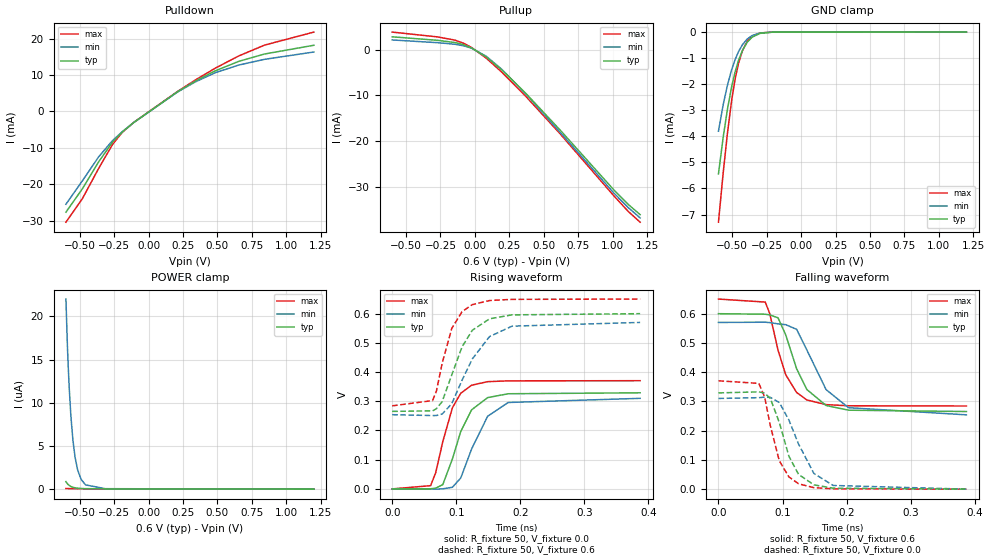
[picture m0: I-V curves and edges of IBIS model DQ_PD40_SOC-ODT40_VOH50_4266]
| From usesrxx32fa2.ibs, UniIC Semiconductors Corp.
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| DQ_PD40_SOC-ODT40_VOH50_4266
| (40 Ohm Pulldown, 40 Ohm System ODT Setting, VOH=VDDQ*0.50, 3200-4266Mbps)
[Model]   DQ_PD40_SOC-ODT40_VOH50_4266
Model_type   I/O
Vinl = 90.000mV
Vinh = 210.000mV
Vmeas = 150.000mV
Vref = 0.0mV
Cref = 0.0pF
Rref = 40.000Ohm
|   typ   min   max
|C_comp   0.834pF   0.784pF   0.884pF
C_comp_pullup   0.4170pF   0.3920pF   0.4420pF
C_comp_pulldown   0.4170pF   0.3920pF   0.4420pF
| Note: C_comp changes when the ODT circuit is enabled.
[Model Spec]
| Input threshold voltage corners
Vinl   0.0900V   0.0825V   0.1025V
Vinh   0.2100V   0.2025V   0.2225V
| Measurement voltage corners
Vmeas   0.1500V   0.1425V   0.1625V
| Timing spec test load voltage corners
Vref   0.0000V   0.0000V   0.0000V
| Dynamic Overshoot Parameters from LPDDR4_0P6 Specification
D_overshoot_ampl_h   0.30   NA   NA
D_overshoot_ampl_l   0.30   NA   NA
D_overshoot_area_h   0.1n   NA   NA
D_overshoot_area_l   0.1n   NA   NA
[Voltage Range]   0.6000V   0.5700V   0.6500V
[Pullup Reference]   0.6000V   0.5700V   0.6500V
| Junction Temperature (Ambient temp is 35C typ 95C min -40C max)
[Temperature Range]   50.0   110.0   -40.0
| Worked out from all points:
|   slope of the pulldown table from 0 to 0.09 V, typ, clamps not added: 37.5 ohm
|   slope of the pullup table from 0 to 0.09 V, typ, clamps not added: 50.7 ohm
|   GND clamp passes 1 mA (typ) near -0.45 V on its own axis
|   rising waveform, R_fixture 50, V_fixture 0.0: 20-80 % time 32.4ps typ, 36.9ps min, 27.6ps max; typ from 0 V to 0.329 V
|   falling waveform, R_fixture 50, V_fixture 0.6: 20-80 % time 36.5ps typ, 44.7ps min, 30.1ps max; typ from 0.6 V to 0.265 V
|   rising waveform, R_fixture 50, V_fixture 0.6: 20-80 % time 36.8ps typ, 46.2ps min, 27.6ps max; typ from 0.265 V to 0.6 V
|   falling waveform, R_fixture 50, V_fixture 0.0: 20-80 % time 29.8ps typ, 38.3ps min, 25.6ps max; typ from 0.329 V to 0 V
[Pulldown]
|   Voltage   I(typ)   I(min)   I(max)
-600mV    -27.61mA   -25.44mA   -30.36mA
-481.2mV  -21.24mA   -19.05mA   -23.95mA
-362.4mV  -13.81mA   -12.44mA   -15.62mA
-261.6mV  -8.403mA   -7.984mA   -9.043mA
-191.4mV  -5.65mA    -5.564mA   -5.738mA
-106.8mV  -3.009mA   -3.011mA   -2.967mA
210mV     5.393mA    5.317mA    5.481mA
343.2mV   8.401mA    8.176mA    8.713mA
483.6mV   11.12mA    10.61mA    11.85mA
652.8mV   13.71mA    12.71mA    15.19mA
841.8mV   15.75mA    14.29mA    18.19mA
1.2V      18.15mA    16.3mA     21.76mA
[GND Clamp]
|   Voltage   I(typ)   I(min)   I(max)
-600mV    -5.439mA   -3.802mA   -7.294mA
-565.8mV  -4.041mA   -2.789mA   -5.405mA
-535.2mV  -2.973mA   -2.046mA   -3.901mA
-504.6mV  -2.102mA   -1.448mA   -2.634mA
-479.4mV  -1.532mA   -1.058mA   -1.808mA
-454.2mV  -1.084mA   -747.4uA   -1.192mA
-425.4mV  -700.2uA   -481.1uA   -707uA
-391.2mV  -388.2uA   -265.6uA   -353.3uA
-355.2mV  -191.7uA   -131uA     -153uA
-297.6mV  -49.42uA   -36uA      -31.63uA
-211.2mV  -4.178uA   -3.866uA   -1.653uA
1.2V      0A         0A         0A
[Pullup]
|   Voltage   I(typ)   I(min)   I(max)
-600mV    2.791mA    2.105mA    3.822mA
-270.6mV  2.022mA    1.507mA    2.767mA
-144.6mV  1.539mA    1.164mA    2.066mA
-81.6mV   1.06mA     833.1uA    1.379mA
-24mV     363.8uA    298.2uA    458.9uA
82.2mV    -1.597mA   -1.443mA   -1.864mA
195.6mV   -4.447mA   -4.306mA   -4.93mA
368.4mV   -9.521mA   -9.648mA   -10.17mA
618.6mV   -17.57mA   -18.06mA   -18.39mA
1.007V    -30.6mA    -31.29mA   -31.89mA
1.114V    -33.85mA   -34.55mA   -35.39mA
1.2V      -36.08mA   -36.8mA    -37.73mA
[POWER Clamp]
|   Voltage   I(typ)   I(min)   I(max)
-600mV    870.6nA    22uA       72.65nA
-589.2mV  630.3nA    16.59uA    68.66nA
-583.8mV  538.6nA    14.39uA    66.96nA
-576.6mV  439.3nA    11.87uA    64.76nA
-564mV    312.7nA    8.464uA    61.06nA
-549.6mV  220nA      5.727uA    57.05nA
-533.4mV  154.6nA    3.672uA    52.81nA
-515.4mV  112.1nA    2.248uA    48.4nA
-490.2mV  80.1nA     1.143uA    42.74nA
-457.8mV  60.43nA    496.6nA    36.26nA
-313.8mV  32.76nA    54.76nA    16.39nA
1.2V      0A         0A         0A
[Ramp]
|   typ   min   max
| 20% - 80%
dV/dt_r   197.37m/32.41p   186.01m/36.87p   222.28m/27.64p
dV/dt_f   200.71m/36.55p   189.46m/44.72p   219.39m/30.09p
| 25% - 75%
|dV/dt_r   164.47m/25.64p   155.01m/29.22p   185.23m/21.78p
|dV/dt_f   167.26m/28.85p   157.89m/35.36p   182.82m/23.68p
R_load = 50
[Rising Waveform]
R_fixture = 50
V_fixture = 0.0
|   Time   V(typ)   V(min)   V(max)
0s        149.9uV    129.1uV    73.21uV
60ps      430.6uV    -393.9uV   11.15mV
68ps      2.741mV    -860.7uV   56.09mV
79ps      14.77mV    331.8uV    162mV
94ps      102.7mV    5.584mV    278mV
107ps     196.6mV    37.37mV    327.5mV
124ps     270.9mV    137mV      355.1mV
149ps     312.6mV    248.8mV    367.2mV
181ps     325.8mV    295.9mV    370mV
387ps     329.1mV    310.1mV    370.5mV
[Falling Waveform]
R_fixture   = 50
V_fixture   = 0.6
V_fixture_min = 0.57
V_fixture_max = 0.65
|   Time   V(typ)   V(min)   V(max)
0s        600mV      570mV      650mV
73ps      598.2mV    570.9mV    639.7mV
80ps      595.9mV    569.5mV    600.6mV
93ps      585.8mV    565.2mV    475.3mV
105ps     527.5mV    562.5mV    391.2mV
122ps     411.7mV    546.5mV    330.6mV
138ps     340.6mV    475.7mV    305.1mV
168ps     286.1mV    340.4mV    289.1mV
203ps     270.1mV    278.6mV    285.2mV
387ps     265.5mV    254.2mV    284.4mV
[Rising Waveform]
R_fixture   = 50
V_fixture   = 0.6
V_fixture_min = 0.57
V_fixture_max = 0.65
|   Time   V(typ)   V(min)   V(max)
0s        265.4mV    254.1mV    284.4mV
63ps      267.3mV    251.2mV    302.5mV
69ps      274.6mV    251.3mV    334.7mV
78ps      298.9mV    256.3mV    430.3mV
93ps      390.4mV    291.7mV    549.5mV
109ps     486.2mV    372mV      606.9mV
125ps     543.2mV    444.8mV    631mV
152ps     582.4mV    521.7mV    645mV
187ps     595.9mV    557.2mV    649mV
387ps     600mV      570mV      650mV
[Falling Waveform]
R_fixture = 50
V_fixture = 0.0
|   Time   V(typ)   V(min)   V(max)
0s        329.2mV    310.2mV    370.6mV
63ps      332.7mV    312.9mV    361.7mV
72ps      328.7mV    314.8mV    315.8mV
81ps      310.1mV    313.8mV    216.5mV
95ps      227.9mV    296.3mV    96.9mV
110ps     112.4mV    236.2mV    41.9mV
125ps     50.7mV     154.4mV    18.54mV
149ps     14.81mV    53.63mV    5.217mV
179ps     3.535mV    12.74mV    1.174mV
387ps     204.4uV    205.7uV    91.86uV
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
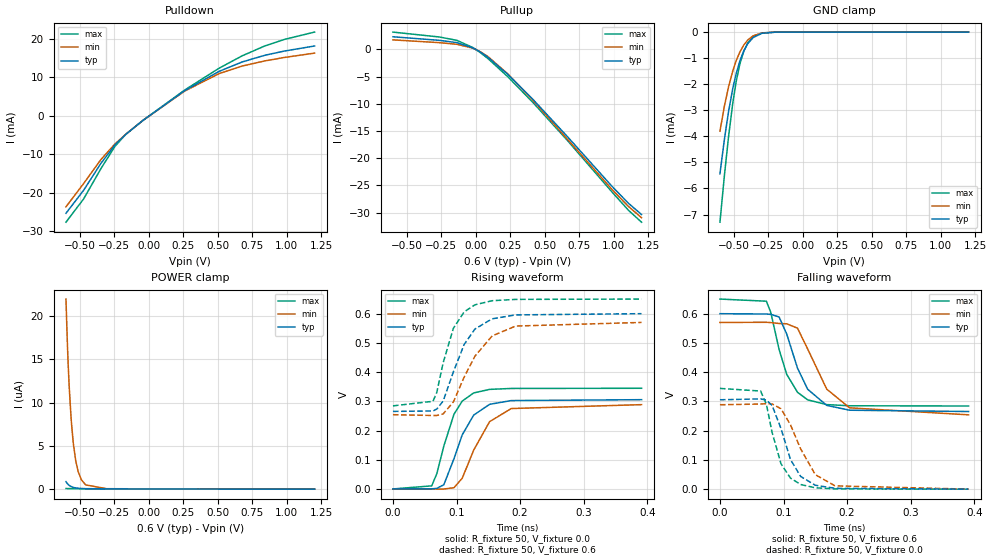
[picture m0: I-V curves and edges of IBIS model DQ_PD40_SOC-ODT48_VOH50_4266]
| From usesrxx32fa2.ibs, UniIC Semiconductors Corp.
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| DQ_PD40_SOC-ODT48_VOH50_4266
| (40 Ohm Pulldown, 48 Ohm System ODT Setting, VOH=VDDQ*0.50, 3200-4266Mbps)
[Model]   DQ_PD40_SOC-ODT48_VOH50_4266
Model_type   I/O
Vinl = 90.000mV
Vinh = 210.000mV
Vmeas = 150.000mV
Vref = 0.0mV
Cref = 0.0pF
Rref = 48.000Ohm
|   typ   min   max
|C_comp   0.834pF   0.784pF   0.884pF
C_comp_pullup   0.4170pF   0.3920pF   0.4420pF
C_comp_pulldown   0.4170pF   0.3920pF   0.4420pF
| Note: C_comp changes when the ODT circuit is enabled.
[Model Spec]
| Input threshold voltage corners
Vinl   0.0900V   0.0825V   0.1025V
Vinh   0.2100V   0.2025V   0.2225V
| Measurement voltage corners
Vmeas   0.1500V   0.1425V   0.1625V
| Timing spec test load voltage corners
Vref   0.0000V   0.0000V   0.0000V
| Dynamic Overshoot Parameters from LPDDR4_0P6 Specification
D_overshoot_ampl_h   0.30   NA   NA
D_overshoot_ampl_l   0.30   NA   NA
D_overshoot_area_h   0.1n   NA   NA
D_overshoot_area_l   0.1n   NA   NA
[Voltage Range]   0.6000V   0.5700V   0.6500V
[Pullup Reference]   0.6000V   0.5700V   0.6500V
| Junction Temperature (Ambient temp is 35C typ 95C min -40C max)
[Temperature Range]   50.0   110.0   -40.0
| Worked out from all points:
|   slope of the pulldown table from 0 to 0.09 V, typ, clamps not added: 37.5 ohm
|   slope of the pullup table from 0 to 0.09 V, typ, clamps not added: 60.5 ohm
|   GND clamp passes 1 mA (typ) near -0.45 V on its own axis
|   rising waveform, R_fixture 50, V_fixture 0.0: 20-80 % time 34.1ps typ, 38.8ps min, 29.5ps max; typ from 0 V to 0.306 V
|   falling waveform, R_fixture 50, V_fixture 0.6: 20-80 % time 36.4ps typ, 44.5ps min, 30ps max; typ from 0.6 V to 0.265 V
|   rising waveform, R_fixture 50, V_fixture 0.6: 20-80 % time 38.2ps typ, 48ps min, 29.5ps max; typ from 0.265 V to 0.6 V
|   falling waveform, R_fixture 50, V_fixture 0.0: 20-80 % time 29.7ps typ, 38.2ps min, 25.5ps max; typ from 0.306 V to 0 V
[Pulldown]
|   Voltage   I(typ)   I(min)   I(max)
-600mV    -25.3mA    -23.62mA   -27.61mA
-472.2mV  -19.33mA   -17.58mA   -21.57mA
-348mV    -12.39mA   -11.39mA   -13.77mA
-245.4mV  -7.543mA   -7.299mA   -7.923mA
-166.2mV  -4.776mA   -4.752mA   -4.766mA
-40.2mV   -1.116mA   -1.117mA   -1.099mA
260.4mV   6.575mA    6.453mA    6.729mA
508.8mV   11.56mA    10.98mA    12.38mA
676.2mV   14.01mA    12.94mA    15.6mA
838.2mV   15.72mA    14.26mA    18.14mA
982.2mV   16.84mA    15.17mA    19.87mA
1.2V      18.15mA    16.3mA     21.76mA
[GND Clamp]
|   Voltage   I(typ)   I(min)   I(max)
-600mV    -5.439mA   -3.802mA   -7.294mA
-567.6mV  -4.11mA    -2.837mA   -5.5mA
-537mV    -3.03mA    -2.085mA   -3.984mA
-506.4mV  -2.147mA   -1.48mA    -2.701mA
-483mV    -1.606mA   -1.108mA   -1.914mA
-456mV    -1.113mA   -767.4uA   -1.229mA
-427.2mV  -720.9uA   -495.1uA   -731.4uA
-398.4mV  -442.5uA   -303.2uA   -412.2uA
-358.8mV  -206.5uA   -141.1uA   -167.7uA
-295.8mV  -46.87uA   -34.39uA   -30.01uA
-196.8mV  -2.661uA   -2.56uA    -930.3nA
1.2V      0A         0A         0A
[Pullup]
|   Voltage   I(typ)   I(min)   I(max)
-600mV    2.327mA    1.755mA    3.187mA
-263.4mV  1.669mA    1.244mA    2.284mA
-137.4mV  1.249mA    947.7uA    1.674mA
-22.2mV   282.6uA    232uA      356.7uA
28.2mV    -409.2uA   -351.4uA   -496.8uA
89.4mV    -1.476mA   -1.34mA    -1.715mA
231.6mV   -4.578mA   -4.498mA   -5.021mA
417mV     -9.279mA   -9.462mA   -9.848mA
663.6mV   -16.04mA   -16.5mA    -16.75mA
987.6mV   -25.21mA   -25.79mA   -26.25mA
1.106V    -28.3mA    -28.89mA   -29.59mA
1.2V      -30.35mA   -30.94mA   -31.76mA
[POWER Clamp]
|   Voltage   I(typ)   I(min)   I(max)
-600mV    870.6nA    21.99uA    72.65nA
-589.2mV  630.3nA    16.59uA    68.66nA
-583.8mV  538.7nA    14.38uA    66.96nA
-576.6mV  439.5nA    11.87uA    64.76nA
-562.2mV  298.7nA    8.067uA    60.55nA
-547.8mV  210.3nA    5.447uA    56.57nA
-529.8mV  144.2nA    3.329uA    51.9nA
-511.8mV  105.9nA    2.039uA    47.56nA
-488.4mV  78.54nA    1.09uA     41.9nA
-457.8mV  60.53nA    496.8nA    36.26nA
-304.8mV  31.8nA     52.11nA    15.54nA
1.2V      0A         0A         0A
[Ramp]
|   typ   min   max
| 20% - 80%
dV/dt_r   183.29m/34.10p   173.12m/38.82p   206.72m/29.52p
dV/dt_f   200.72m/36.44p   189.48m/44.46p   219.38m/30.02p
| 25% - 75%
|dV/dt_r   152.74m/26.99p   144.26m/30.75p   172.26m/23.28p
|dV/dt_f   167.26m/28.75p   157.90m/35.18p   182.82m/23.65p
R_load = 50
[Rising Waveform]
R_fixture = 50
V_fixture = 0.0
|   Time   V(typ)   V(min)   V(max)
0s        120.8uV    101.4uV    60.2uV
61ps      343.6uV    -302.5uV   10.51mV
69ps      1.882mV    -766.3uV   52.42mV
80ps      14.36mV    -212.7uV   146.6mV
96ps      103.6mV    4.263mV    255.8mV
109ps     185.3mV    36.8mV     300.8mV
127ps     252.8mV    132.9mV    328.7mV
152ps     289.7mV    230.3mV    340.8mV
186ps     302.5mV    275.2mV    344mV
391ps     305.6mV    288.6mV    344.6mV
[Falling Waveform]
R_fixture   = 50
V_fixture   = 0.6
V_fixture_min = 0.57
V_fixture_max = 0.65
|   Time   V(typ)   V(min)   V(max)
0s        600mV      570mV      650mV
73ps      598.9mV    570.6mV    642.7mV
80ps      597.6mV    569.6mV    604mV
93ps      588.8mV    566.5mV    477.9mV
105ps     530.6mV    565.4mV    392.7mV
122ps     413.8mV    550.4mV    331.3mV
138ps     341.6mV    479.2mV    305.4mV
168ps     286.4mV    341.9mV    289.2mV
204ps     270mV      278.1mV    285.2mV
391ps     265.5mV    254.2mV    284.4mV
[Rising Waveform]
R_fixture   = 50
V_fixture   = 0.6
V_fixture_min = 0.57
V_fixture_max = 0.65
|   Time   V(typ)   V(min)   V(max)
0s        265.4mV    254.1mV    284.4mV
63ps      266.8mV    251.5mV    300.1mV
69ps      273.5mV    251.4mV    330.8mV
79ps      301mV      256.9mV    432.2mV
95ps      400.4mV    297.7mV    549.7mV
112ps     494.6mV    382.9mV    606.2mV
129ps     547.5mV    454.7mV    630.4mV
156ps     582.4mV    523.8mV    644.3mV
193ps     595.8mV    557.6mV    648.9mV
391ps     600mV      570mV      650mV
[Falling Waveform]
R_fixture = 50
V_fixture = 0.0
|   Time   V(typ)   V(min)   V(max)
0s        305.7mV    288.7mV    344.6mV
64ps      308.6mV    291.1mV    335.5mV
73ps      304.7mV    292.6mV    290.8mV
82ps      286.5mV    291.4mV    194.3mV
96ps      207.5mV    275.1mV    87.18mV
111ps     101.1mV    219.8mV    37.91mV
127ps     43.48mV    137.5mV    15.92mV
150ps     13.43mV    49.64mV    4.75mV
181ps     3.075mV    11.38mV    1.024mV
391ps     179.7uV    183.6uV    80.44uV
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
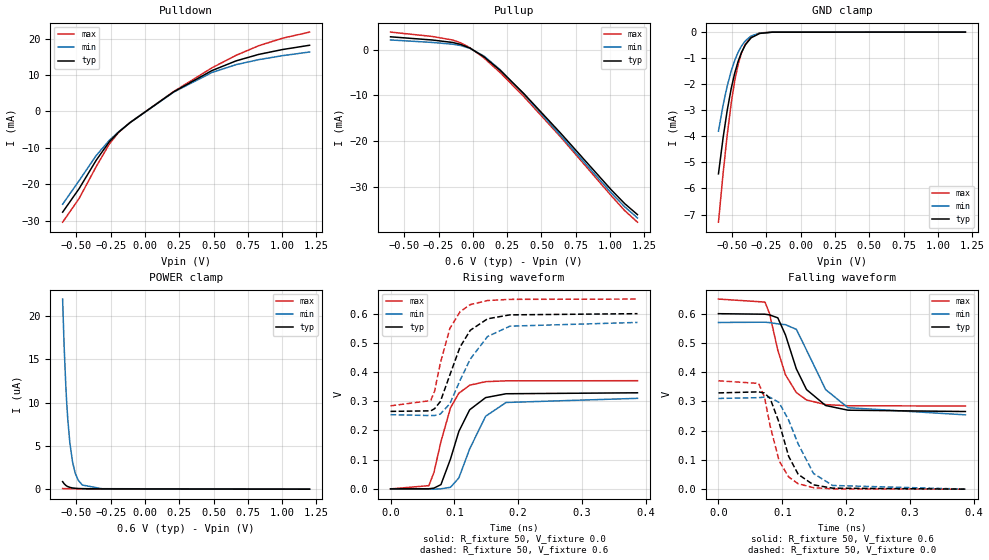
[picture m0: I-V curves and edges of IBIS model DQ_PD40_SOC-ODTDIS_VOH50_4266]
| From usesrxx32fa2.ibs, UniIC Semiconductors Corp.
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| DQ_PD40_SOC-ODTDIS_VOH50_4266
| (40 Ohm Pulldown, SOC ODT disabled setting, VOH=VDDQ*0.50 cal. point, 3200-4266Mbps)
[Model]   DQ_PD40_SOC-ODTDIS_VOH50_4266
Model_type   I/O
Vinl = 90.000mV
Vinh = 210.000mV
Vmeas = 150.000mV
Vref = 0.0mV
Cref = 0.0pF
|   typ   min   max
|C_comp   0.834pF   0.784pF   0.884pF
C_comp_pullup   0.4170pF   0.3920pF   0.4420pF
C_comp_pulldown   0.4170pF   0.3920pF   0.4420pF
| Note: C_comp changes when the ODT circuit is enabled.
[Model Spec]
| Input threshold voltage corners
Vinl   0.0900V   0.0825V   0.1025V
Vinh   0.2100V   0.2025V   0.2225V
| Measurement voltage corners
Vmeas   0.1500V   0.1425V   0.1625V
| Timing spec test load voltage corners
Vref   0.0000V   0.0000V   0.0000V
| Dynamic Overshoot Parameters from LPDDR4_0P6 Specification
D_overshoot_ampl_h   0.30   NA   NA
D_overshoot_ampl_l   0.30   NA   NA
D_overshoot_area_h   0.1n   NA   NA
D_overshoot_area_l   0.1n   NA   NA
[Voltage Range]   0.6000V   0.5700V   0.6500V
[Pullup Reference]   0.6000V   0.5700V   0.6500V
| Junction Temperature (Ambient temp is 35C typ 95C min -40C max)
[Temperature Range]   50.0   110.0   -40.0
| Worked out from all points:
|   slope of the pulldown table from 0 to 0.09 V, typ, clamps not added: 37.5 ohm
|   slope of the pullup table from 0 to 0.09 V, typ, clamps not added: 50.7 ohm
|   GND clamp passes 1 mA (typ) near -0.45 V on its own axis
|   rising waveform, R_fixture 50, V_fixture 0.0: 20-80 % time 32.4ps typ, 36.9ps min, 27.6ps max; typ from 0 V to 0.329 V
|   falling waveform, R_fixture 50, V_fixture 0.6: 20-80 % time 36.5ps typ, 44.7ps min, 30.1ps max; typ from 0.6 V to 0.265 V
|   rising waveform, R_fixture 50, V_fixture 0.6: 20-80 % time 36.8ps typ, 46.2ps min, 27.6ps max; typ from 0.265 V to 0.6 V
|   falling waveform, R_fixture 50, V_fixture 0.0: 20-80 % time 29.8ps typ, 38.3ps min, 25.6ps max; typ from 0.329 V to 0 V
[Pulldown]
|   Voltage   I(typ)   I(min)   I(max)
-600mV    -27.61mA   -25.44mA   -30.36mA
-479.4mV  -21.14mA   -18.95mA   -23.84mA
-355.2mV  -13.37mA   -12.08mA   -15.11mA
-259.8mV  -8.319mA   -7.915mA   -8.942mA
-191.4mV  -5.652mA   -5.565mA   -5.739mA
-108.6mV  -3.062mA   -3.063mA   -3.02mA
210mV     5.393mA    5.317mA    5.481mA
489mV     11.22mA    10.69mA    11.97mA
665.4mV   13.88mA    12.84mA    15.41mA
829.2mV   15.64mA    14.2mA     18.02mA
1.002V    16.97mA    15.29mA    20.07mA
1.2V      18.15mA    16.3mA     21.76mA
[GND Clamp]
|   Voltage   I(typ)   I(min)   I(max)
-600mV    -5.439mA   -3.802mA   -7.294mA
-565.8mV  -4.041mA   -2.789mA   -5.405mA
-537mV    -3.03mA    -2.086mA   -3.985mA
-506.4mV  -2.147mA   -1.48mA    -2.701mA
-481.2mV  -1.568mA   -1.083mA   -1.861mA
-456mV    -1.113mA   -767.4uA   -1.229mA
-430.8mV  -763.1uA   -524uA     -782.6uA
-403.8mV  -488.3uA   -333.4uA   -460.9uA
-362.4mV  -220.8uA   -151.7uA   -182.6uA
-299.4mV  -51.42uA   -37.48uA   -33.44uA
-207.6mV  -3.726uA   -3.456uA   -1.422uA
1.2V      0A         0A         0A
[Pullup]
|   Voltage   I(typ)   I(min)   I(max)
-600mV    2.791mA    2.105mA    3.822mA
-295.8mV  2.093mA    1.56mA     2.865mA
-148.2mV  1.559mA    1.178mA    2.095mA
-90.6mV   1.145mA    893.1uA    1.499mA
-22.2mV   337.6uA    278uA      425.8uA
80.4mV    -1.558mA   -1.404mA   -1.819mA
199.2mV   -4.546mA   -4.409mA   -5.034mA
372mV     -9.633mA   -9.765mA   -10.28mA
636.6mV   -18.17mA   -18.68mA   -19mA
1.009V    -30.66mA   -31.34mA   -31.95mA
1.106V    -33.65mA   -34.34mA   -35.17mA
1.2V      -36.08mA   -36.8mA    -37.73mA
[POWER Clamp]
|   Voltage   I(typ)   I(min)   I(max)
-600mV    870.6nA    21.99uA    72.65nA
-589.2mV  630.2nA    16.59uA    68.66nA
-576.6mV  439.6nA    11.88uA    64.76nA
-569.4mV  360.7nA    9.788uA    62.62nA
-562.2mV  298.5nA    8.066uA    60.54nA
-547.8mV  210.9nA    5.439uA    56.57nA
-528mV    139.5nA    3.169uA    51.46nA
-508.2mV  100.5nA    1.852uA    46.73nA
-486.6mV  77.14nA    1.041uA    41.97nA
-456mV    59.71nA    476.5nA    35.92nA
-313.8mV  32.75nA    54.77nA    16.39nA
1.2V      0A         0A         0A
[Ramp]
|   typ   min   max
| 20% - 80%
dV/dt_r   197.37m/32.41p   186.01m/36.87p   222.28m/27.64p
dV/dt_f   200.71m/36.55p   189.46m/44.72p   219.39m/30.09p
| 25% - 75%
|dV/dt_r   164.47m/25.64p   155.01m/29.22p   185.23m/21.78p
|dV/dt_f   167.26m/28.85p   157.89m/35.36p   182.82m/23.68p
R_load = 50
[Rising Waveform]
R_fixture = 50
V_fixture = 0.0
|   Time   V(typ)   V(min)   V(max)
0s        149.9uV    129.1uV    73.21uV
60ps      430.6uV    -393.9uV   11.15mV
68ps      2.741mV    -860.7uV   56.09mV
79ps      14.77mV    331.8uV    162mV
94ps      102.7mV    5.584mV    278mV
107ps     196.6mV    37.37mV    327.5mV
124ps     270.9mV    137mV      355.1mV
149ps     312.6mV    248.8mV    367.2mV
181ps     325.8mV    295.9mV    370mV
387ps     329.1mV    310.1mV    370.5mV
[Falling Waveform]
R_fixture   = 50
V_fixture   = 0.6
V_fixture_min = 0.57
V_fixture_max = 0.65
|   Time   V(typ)   V(min)   V(max)
0s        600mV      570mV      650mV
73ps      598.2mV    570.9mV    639.7mV
80ps      595.9mV    569.5mV    600.6mV
93ps      585.8mV    565.2mV    475.3mV
105ps     527.5mV    562.5mV    391.2mV
122ps     411.7mV    546.5mV    330.6mV
138ps     340.6mV    475.7mV    305.1mV
168ps     286.1mV    340.4mV    289.1mV
203ps     270.1mV    278.6mV    285.2mV
387ps     265.5mV    254.2mV    284.4mV
[Rising Waveform]
R_fixture   = 50
V_fixture   = 0.6
V_fixture_min = 0.57
V_fixture_max = 0.65
|   Time   V(typ)   V(min)   V(max)
0s        265.4mV    254.1mV    284.4mV
63ps      267.3mV    251.2mV    302.5mV
69ps      274.6mV    251.3mV    334.7mV
78ps      298.9mV    256.3mV    430.3mV
93ps      390.4mV    291.7mV    549.5mV
109ps     486.2mV    372mV      606.9mV
125ps     543.2mV    444.8mV    631mV
152ps     582.4mV    521.7mV    645mV
187ps     595.9mV    557.2mV    649mV
387ps     600mV      570mV      650mV
[Falling Waveform]
R_fixture = 50
V_fixture = 0.0
|   Time   V(typ)   V(min)   V(max)
0s        329.2mV    310.2mV    370.6mV
63ps      332.7mV    312.9mV    361.7mV
72ps      328.7mV    314.8mV    315.8mV
81ps      310.1mV    313.8mV    216.5mV
95ps      227.9mV    296.3mV    96.9mV
110ps     112.4mV    236.2mV    41.9mV
125ps     50.7mV     154.4mV    18.54mV
149ps     14.81mV    53.63mV    5.217mV
179ps     3.535mV    12.74mV    1.174mV
387ps     204.4uV    205.7uV    91.86uV
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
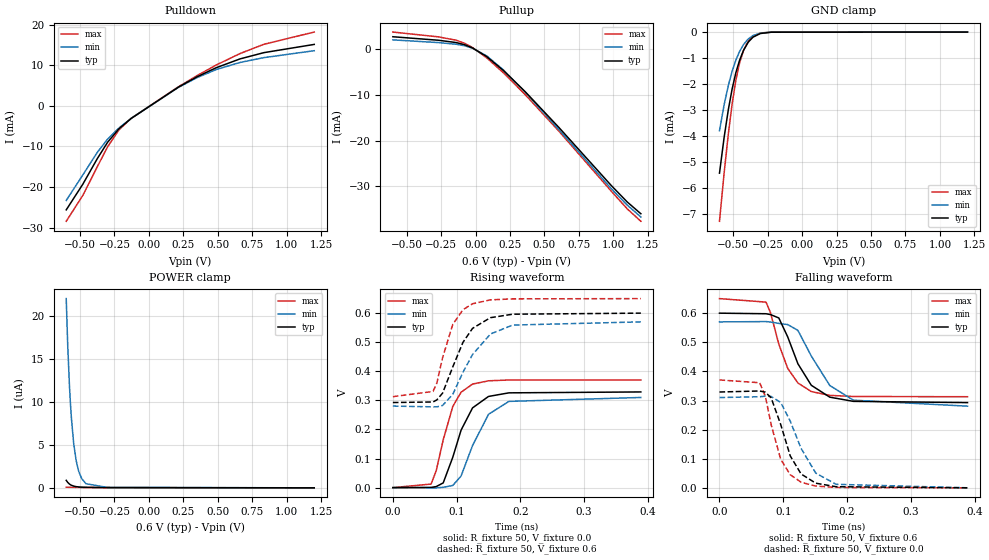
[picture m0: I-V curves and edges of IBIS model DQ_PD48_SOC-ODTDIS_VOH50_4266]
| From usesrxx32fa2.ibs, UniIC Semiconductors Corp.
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| DQ_PD48_SOC-ODTDIS_VOH50_4266
| (48 Ohm Pulldown, SOC ODT disabled setting, VOH=VDDQ*0.50 cal. point, 3200-4266Mbps)
[Model]   DQ_PD48_SOC-ODTDIS_VOH50_4266
Model_type   I/O
Vinl = 90.000mV
Vinh = 210.000mV
Vmeas = 150.000mV
Vref = 0.0mV
Cref = 0.0pF
|   typ   min   max
|C_comp   0.834pF   0.784pF   0.884pF
C_comp_pullup   0.4170pF   0.3920pF   0.4420pF
C_comp_pulldown   0.4170pF   0.3920pF   0.4420pF
| Note: C_comp changes when the ODT circuit is enabled.
[Model Spec]
| Input threshold voltage corners
Vinl   0.0900V   0.0825V   0.1025V
Vinh   0.2100V   0.2025V   0.2225V
| Measurement voltage corners
Vmeas   0.1500V   0.1425V   0.1625V
| Timing spec test load voltage corners
Vref   0.0000V   0.0000V   0.0000V
| Dynamic Overshoot Parameters from LPDDR4_0P6 Specification
D_overshoot_ampl_h   0.30   NA   NA
D_overshoot_ampl_l   0.30   NA   NA
D_overshoot_area_h   0.1n   NA   NA
D_overshoot_area_l   0.1n   NA   NA
[Voltage Range]   0.6000V   0.5700V   0.6500V
[Pullup Reference]   0.6000V   0.5700V   0.6500V
| Junction Temperature (Ambient temp is 35C typ 95C min -40C max)
[Temperature Range]   50.0   110.0   -40.0
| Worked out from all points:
|   slope of the pulldown table from 0 to 0.09 V, typ, clamps not added: 44.5 ohm
|   slope of the pullup table from 0 to 0.09 V, typ, clamps not added: 50.7 ohm
|   GND clamp passes 1 mA (typ) near -0.45 V on its own axis
|   rising waveform, R_fixture 50, V_fixture 0.0: 20-80 % time 32.5ps typ, 37.1ps min, 27.7ps max; typ from 0 V to 0.329 V
|   falling waveform, R_fixture 50, V_fixture 0.6: 20-80 % time 39.6ps typ, 48.3ps min, 32.7ps max; typ from 0.6 V to 0.293 V
|   rising waveform, R_fixture 50, V_fixture 0.6: 20-80 % time 37.3ps typ, 46.3ps min, 27.7ps max; typ from 0.293 V to 0.6 V
|   falling waveform, R_fixture 50, V_fixture 0.0: 20-80 % time 31.4ps typ, 39.2ps min, 27.4ps max; typ from 0.329 V to 0 V
[Pulldown]
|   Voltage   I(typ)   I(min)   I(max)
-600mV    -25.65mA   -23.32mA   -28.46mA
-479.4mV  -19.31mA   -17.02mA   -22.07mA
-375mV    -13.04mA   -11.49mA   -15.04mA
-299.4mV  -8.959mA   -8.191mA   -10.08mA
-216.6mV  -5.621mA   -5.438mA   -5.881mA
-128.4mV  -3.091mA   -3.081mA   -3.064mA
213.6mV   4.611mA    4.541mA    4.697mA
348.6mV   7.158mA    6.954mA    7.448mA
489mV     9.419mA    8.963mA    10.08mA
661.8mV   11.59mA    10.71mA    12.91mA
834.6mV   13.13mA    11.9mA     15.19mA
1.2V      15.16mA    13.61mA    18.21mA
[GND Clamp]
|   Voltage   I(typ)   I(min)   I(max)
-600mV    -5.439mA   -3.802mA   -7.294mA
-565.8mV  -4.041mA   -2.789mA   -5.405mA
-535.2mV  -2.973mA   -2.046mA   -3.902mA
-508.2mV  -2.194mA   -1.512mA   -2.769mA
-481.2mV  -1.568mA   -1.083mA   -1.86mA
-454.2mV  -1.088mA   -747.9uA   -1.192mA
-425.4mV  -702.6uA   -480.7uA   -707uA
-391.2mV  -389.2uA   -265.9uA   -353.1uA
-357mV    -197.6uA   -135.7uA   -159.7uA
-303mV    -56.24uA   -40.87uA   -37.05uA
-223.8mV  -6.148uA   -5.391uA   -2.657uA
1.2V      0A         0A         0A
[Pullup]
|   Voltage   I(typ)   I(min)   I(max)
-600mV    2.791mA    2.105mA    3.822mA
-270.6mV  2.023mA    1.507mA    2.767mA
-139.2mV  1.508mA    1.143mA    2.02mA
-78mV     1.023mA    806.9uA    1.33mA
-22.2mV   337.9uA    277.3uA    425.9uA
82.2mV    -1.597mA   -1.442mA   -1.864mA
201mV     -4.595mA   -4.46mA    -5.086mA
359.4mV   -9.244mA   -9.355mA   -9.884mA
604.2mV   -17.1mA    -17.57mA   -17.91mA
984mV     -29.84mA   -30.53mA   -31.08mA
1.101V    -33.49mA   -34.18mA   -35mA
1.2V      -36.08mA   -36.8mA    -37.73mA
[POWER Clamp]
|   Voltage   I(typ)   I(min)   I(max)
-600mV    870.7nA    21.98uA    72.65nA
-589.2mV  630.1nA    16.59uA    68.66nA
-576.6mV  439.6nA    11.87uA    64.76nA
-569.4mV  360.8nA    9.779uA    62.62nA
-562.2mV  298.7nA    8.065uA    60.55nA
-546mV    201.7nA    5.181uA    56.09nA
-528mV    139.1nA    3.168uA    51.45nA
-510mV    103.3nA    1.942uA    47.14nA
-486.6mV  77.64nA    1.039uA    41.97nA
-456mV    59.93nA    475.7nA    35.93nA
-303mV    31.59nA    51.64nA    15.37nA
1.2V      0A         0A         0A
[Ramp]
|   typ   min   max
| 20% - 80%
dV/dt_r   197.35m/32.51p   186.00m/37.10p   222.27m/27.70p
dV/dt_f   184.34m/39.59p   173.65m/48.26p   202.23m/32.68p
| 25% - 75%
|dV/dt_r   164.46m/25.72p   155.00m/29.39p   185.23m/21.83p
|dV/dt_f   153.62m/31.29p   144.71m/38.17p   168.53m/25.78p
R_load = 50
[Rising Waveform]
R_fixture = 50
V_fixture = 0.0
|   Time   V(typ)   V(min)   V(max)
0s        173.2uV    154.4uV    83.28uV
60ps      848uV      -386.9uV   12.42mV
68ps      3.662mV    -590.1uV   58.27mV
79ps      16.4mV     1.227mV    164.5mV
94ps      104.6mV    7.602mV    279.2mV
107ps     197.7mV    40mV       328.1mV
125ps     274.3mV    144.8mV    356.2mV
150ps     313.6mV    252.1mV    367.4mV
182ps     326mV      296.6mV    370.1mV
389ps     329.1mV    310.1mV    370.5mV
[Falling Waveform]
R_fixture   = 50
V_fixture   = 0.6
V_fixture_min = 0.57
V_fixture_max = 0.65
|   Time   V(typ)   V(min)   V(max)
0s        600mV      570mV      650mV
73ps      598mV      571.1mV    637.9mV
80ps      595.2mV    569.7mV    601.9mV
93ps      583.6mV    564.9mV    493.9mV
107ps     518.6mV    560.8mV    410.4mV
123ps     426.2mV    540.8mV    360.2mV
144ps     352.3mV    452.8mV    330.8mV
173ps     311.5mV    351.6mV    317.6mV
210ps     297.1mV    301.1mV    313.8mV
389ps     292.8mV    280.6mV    313mV
[Rising Waveform]
R_fixture   = 50
V_fixture   = 0.6
V_fixture_min = 0.57
V_fixture_max = 0.65
|   Time   V(typ)   V(min)   V(max)
0s        292.7mV    280.5mV    312.9mV
63ps      294.6mV    277.8mV    330.8mV
69ps      301.7mV    277.8mV    359.7mV
78ps      325.1mV    282.7mV    446.8mV
94ps      415.3mV    320.8mV    561.5mV
110ps     499.8mV    396.9mV    611.9mV
125ps     547.7mV    457.7mV    632.3mV
153ps     584.4mV    528.2mV    645.6mV
188ps     596.4mV    559mV      649.1mV
389ps     600mV      570mV      650mV
[Falling Waveform]
R_fixture = 50
V_fixture = 0.0
|   Time   V(typ)   V(min)   V(max)
0s        329.2mV    310.2mV    370.6mV
63ps      332.8mV    313mV      361.1mV
72ps      328.5mV    314.9mV    314.4mV
81ps      309.3mV    313.9mV    217.4mV
96ps      217.8mV    293.3mV    98.04mV
111ps     109.7mV    229.2mV    45.28mV
128ps     47.68mV    135.5mV    19.22mV
151ps     16.07mV    50.71mV    6.199mV
183ps     3.876mV    12.16mV    1.396mV
389ps     224.3uV    225.2uV    101.5uV
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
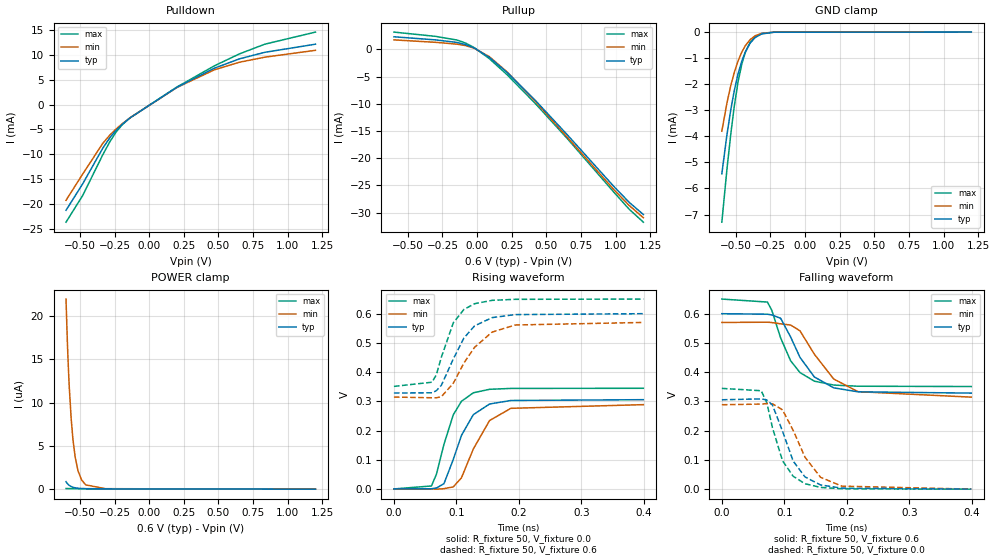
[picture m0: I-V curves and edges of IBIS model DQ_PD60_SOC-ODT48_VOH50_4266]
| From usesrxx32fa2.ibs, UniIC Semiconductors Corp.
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| DQ_PD60_SOC-ODT48_VOH50_4266
| (60 Ohm Pulldown, 48 Ohm System ODT Setting, VOH=VDDQ*0.50, 3200-4266Mbps)
[Model]   DQ_PD60_SOC-ODT48_VOH50_4266
Model_type   I/O
Vinl = 90.000mV
Vinh = 210.000mV
Vmeas = 150.000mV
Vref = 0.0mV
Cref = 0.0pF
Rref = 48.000Ohm
|   typ   min   max
|C_comp   0.834pF   0.784pF   0.884pF
C_comp_pullup   0.4170pF   0.3920pF   0.4420pF
C_comp_pulldown   0.4170pF   0.3920pF   0.4420pF
| Note: C_comp changes when the ODT circuit is enabled.
[Model Spec]
| Input threshold voltage corners
Vinl   0.0900V   0.0825V   0.1025V
Vinh   0.2100V   0.2025V   0.2225V
| Measurement voltage corners
Vmeas   0.1500V   0.1425V   0.1625V
| Timing spec test load voltage corners
Vref   0.0000V   0.0000V   0.0000V
| Dynamic Overshoot Parameters from LPDDR4_0P6 Specification
D_overshoot_ampl_h   0.30   NA   NA
D_overshoot_ampl_l   0.30   NA   NA
D_overshoot_area_h   0.1n   NA   NA
D_overshoot_area_l   0.1n   NA   NA
[Voltage Range]   0.6000V   0.5700V   0.6500V
[Pullup Reference]   0.6000V   0.5700V   0.6500V
| Junction Temperature (Ambient temp is 35C typ 95C min -40C max)
[Temperature Range]   50.0   110.0   -40.0
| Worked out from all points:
|   slope of the pulldown table from 0 to 0.09 V, typ, clamps not added: 55.7 ohm
|   slope of the pullup table from 0 to 0.09 V, typ, clamps not added: 60.5 ohm
|   GND clamp passes 1 mA (typ) near -0.45 V on its own axis
|   rising waveform, R_fixture 50, V_fixture 0.0: 20-80 % time 34.3ps typ, 39.3ps min, 29.6ps max; typ from 0 V to 0.306 V
|   falling waveform, R_fixture 50, V_fixture 0.6: 20-80 % time 43.7ps typ, 53ps min, 36.2ps max; typ from 0.6 V to 0.328 V
|   rising waveform, R_fixture 50, V_fixture 0.6: 20-80 % time 39.9ps typ, 48.6ps min, 30.3ps max; typ from 0.328 V to 0.6 V
|   falling waveform, R_fixture 50, V_fixture 0.0: 20-80 % time 34ps typ, 41.3ps min, 30ps max; typ from 0.306 V to 0 V
[Pulldown]
|   Voltage   I(typ)   I(min)   I(max)
-600mV    -21.23mA   -19.22mA   -23.61mA
-479.4mV  -15.9mA    -13.94mA   -18.25mA
-335.4mV  -8.793mA   -7.814mA   -10.12mA
-283.2mV  -6.646mA   -6.112mA   -7.435mA
-240mV    -5.194mA   -4.934mA   -5.578mA
-196.8mV  -4.008mA   -3.909mA   -4.122mA
-137.4mV  -2.663mA   -2.648mA   -2.642mA
199.2mV   3.451mA    3.406mA    3.504mA
471mV     7.312mA    6.985mA    7.781mA
652.8mV   9.185mA    8.506mA    10.19mA
834.6mV   10.49mA    9.515mA    12.12mA
1.2V      12.12mA    10.89mA    14.55mA
[GND Clamp]
|   Voltage   I(typ)   I(min)   I(max)
-600mV    -5.439mA   -3.802mA   -7.294mA
-564mV    -3.973mA   -2.741mA   -5.311mA
-535.2mV  -2.975mA   -2.046mA   -3.902mA
-510mV    -2.241mA   -1.544mA   -2.838mA
-483mV    -1.605mA   -1.109mA   -1.913mA
-456mV    -1.113mA   -767.3uA   -1.229mA
-430.8mV  -762.9uA   -524.4uA   -782.4uA
-394.8mV  -414.9uA   -283.6uA   -381.8uA
-358.8mV  -206.4uA   -141uA     -167.1uA
-312mV    -70.46uA   -50.33uA   -48.12uA
-223.8mV  -6.283uA   -5.389uA   -2.674uA
1.2V      0A         0A         0A
[Pullup]
|   Voltage   I(typ)   I(min)   I(max)
-600mV    2.327mA    1.755mA    3.187mA
-297.6mV  1.749mA    1.304mA    2.395mA
-142.8mV  1.276mA    964.9uA    1.713mA
-83.4mV   899.7uA    706.2uA    1.174mA
-20.4mV   260.7uA    213.5uA    329uA
89.4mV    -1.476mA   -1.34mA    -1.715mA
217.2mV   -4.237mA   -4.141mA   -4.666mA
418.8mV   -9.327mA   -9.512mA   -9.897mA
654.6mV   -15.79mA   -16.24mA   -16.49mA
985.8mV   -25.16mA   -25.74mA   -26.2mA
1.097V    -28.09mA   -28.67mA   -29.36mA
1.2V      -30.35mA   -30.94mA   -31.76mA
[POWER Clamp]
|   Voltage   I(typ)   I(min)   I(max)
-600mV    870.6nA    21.99uA    72.65nA
-589.2mV  630.1nA    16.59uA    68.66nA
-582mV    511.7nA    13.71uA    66.41nA
-576.6mV  439.1nA    11.87uA    64.76nA
-562.2mV  298.4nA    8.051uA    60.55nA
-549.6mV  219.4nA    5.724uA    57.05nA
-533.4mV  155.3nA    3.674uA    52.81nA
-513.6mV  109.2nA    2.142uA    47.97nA
-488.4mV  78.75nA    1.09uA     42.35nA
-457.8mV  60.5nA     497.5nA    36.26nA
-315.6mV  32.96nA    55.41nA    16.56nA
1.2V      0A         0A         0A
[Ramp]
|   typ   min   max
| 20% - 80%
dV/dt_r   183.26m/34.33p   173.09m/39.27p   206.70m/29.62p
dV/dt_f   162.93m/43.74p   153.15m/52.98p   179.39m/36.21p
| 25% - 75%
|dV/dt_r   152.72m/27.17p   144.24m/31.10p   172.25m/23.38p
|dV/dt_f   135.78m/34.56p   127.63m/41.93p   149.49m/28.57p
R_load = 50
[Rising Waveform]
R_fixture = 50
V_fixture = 0.0
|   Time   V(typ)   V(min)   V(max)
0s        166.3uV    150uV      79.77uV
60ps      646.4uV    -446.3uV   10.21mV
68ps      3.205mV    -749uV     50.23mV
80ps      17.92mV    948.6uV    152.5mV
95ps      101.3mV    7.137mV    254mV
108ps     183.1mV    38.05mV    299.9mV
127ps     254.2mV    136.7mV    329.2mV
153ps     290.8mV    234.1mV    341.1mV
187ps     302.8mV    276mV      344.1mV
399ps     305.6mV    288.6mV    344.6mV
[Falling Waveform]
R_fixture   = 50
V_fixture   = 0.6
V_fixture_min = 0.57
V_fixture_max = 0.65
|   Time   V(typ)   V(min)   V(max)
0s        600mV      570mV      650mV
73ps      598.2mV    570.9mV    639.7mV
80ps      595.7mV    569.7mV    611.1mV
94ps      584.4mV    565.4mV    517.3mV
110ps     520.5mV    561.3mV    439.2mV
125ps     450.8mV    541.5mV    398.7mV
148ps     383.7mV    461.4mV    369.3mV
179ps     346.5mV    376.5mV    356mV
218ps     332.8mV    333.4mV    352mV
399ps     328.5mV    314.7mV    351mV
[Rising Waveform]
R_fixture   = 50
V_fixture   = 0.6
V_fixture_min = 0.57
V_fixture_max = 0.65
|   Time   V(typ)   V(min)   V(max)
0s        328.4mV    314.6mV    351mV
61ps      329.2mV    312.1mV    365.4mV
68ps      336.6mV    312mV      391.5mV
76ps      355.2mV    316mV      451.5mV
95ps      445mV      361.8mV    568.7mV
112ps     516.7mV    431.3mV    614.5mV
129ps     558.2mV    484.8mV    634.1mV
157ps     586.5mV    536.9mV    645.6mV
194ps     596.8mV    561.2mV    649.1mV
399ps     600mV      570mV      650mV
[Falling Waveform]
R_fixture = 50
V_fixture = 0.0
|   Time   V(typ)   V(min)   V(max)
0s        305.7mV    288.7mV    344.6mV
63ps      308.8mV    291mV      336.6mV
72ps      305mV      292.7mV    295.4mV
81ps      287.7mV    291.9mV    210mV
97ps      198.7mV    271.4mV    97.62mV
114ps     96.56mV    201.7mV    44.37mV
133ps     41.95mV    109.4mV    18.67mV
158ps     14.46mV    40.54mV    6.083mV
192ps     3.628mV    10.38mV    1.415mV
399ps     230uV      229.7uV    107.2uV
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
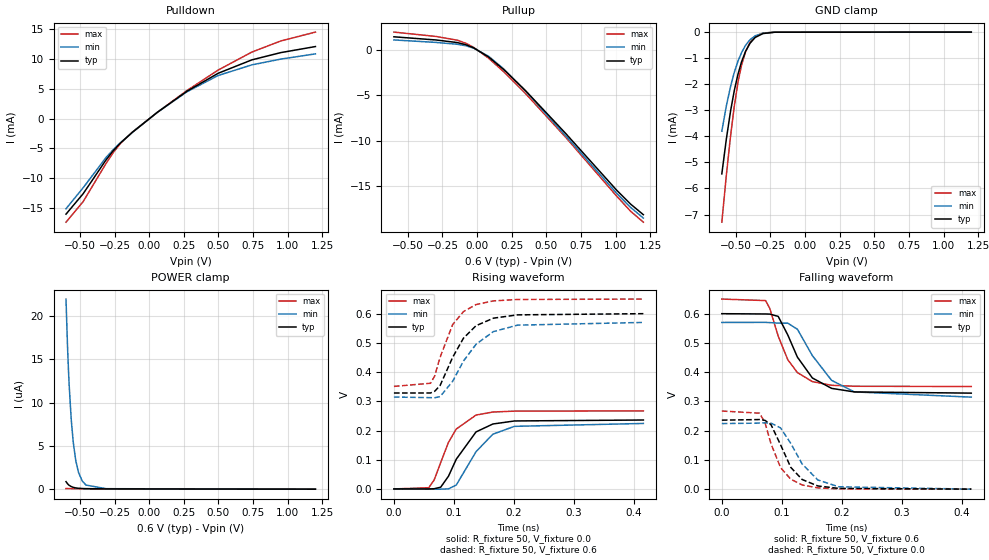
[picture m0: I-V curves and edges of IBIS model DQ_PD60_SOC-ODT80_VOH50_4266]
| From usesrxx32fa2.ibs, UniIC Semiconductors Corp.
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| DQ_PD60_SOC-ODT80_VOH50_4266
| (60 Ohm Pulldown, 80 Ohm System ODT Setting, VOH=VDDQ*0.50, 3200-4266Mbps)
[Model]   DQ_PD60_SOC-ODT80_VOH50_4266
Model_type   I/O
Vinl = 90.000mV
Vinh = 210.000mV
Vmeas = 150.000mV
Vref = 0.0mV
Cref = 0.0pF
Rref = 80.000Ohm
|   typ   min   max
|C_comp   0.834pF   0.784pF   0.884pF
C_comp_pullup   0.4170pF   0.3920pF   0.4420pF
C_comp_pulldown   0.4170pF   0.3920pF   0.4420pF
| Note: C_comp changes when the ODT circuit is enabled.
[Model Spec]
| Input threshold voltage corners
Vinl   0.0900V   0.0825V   0.1025V
Vinh   0.2100V   0.2025V   0.2225V
| Measurement voltage corners
Vmeas   0.1500V   0.1425V   0.1625V
| Timing spec test load voltage corners
Vref   0.0000V   0.0000V   0.0000V
| Dynamic Overshoot Parameters from LPDDR4_0P6 Specification
D_overshoot_ampl_h   0.30   NA   NA
D_overshoot_ampl_l   0.30   NA   NA
D_overshoot_area_h   0.1n   NA   NA
D_overshoot_area_l   0.1n   NA   NA
[Voltage Range]   0.6000V   0.5700V   0.6500V
[Pullup Reference]   0.6000V   0.5700V   0.6500V
| Junction Temperature (Ambient temp is 35C typ 95C min -40C max)
[Temperature Range]   50.0   110.0   -40.0
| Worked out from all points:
|   slope of the pulldown table from 0 to 0.09 V, typ, clamps not added: 55.7 ohm
|   slope of the pullup table from 0 to 0.09 V, typ, clamps not added: 101 ohm
|   GND clamp passes 1 mA (typ) near -0.45 V on its own axis
|   rising waveform, R_fixture 50, V_fixture 0.0: 20-80 % time 41.3ps typ, 44.9ps min, 35.7ps max; typ from 0 V to 0.236 V
|   falling waveform, R_fixture 50, V_fixture 0.6: 20-80 % time 43.4ps typ, 52.4ps min, 36.1ps max; typ from 0.6 V to 0.328 V
|   rising waveform, R_fixture 50, V_fixture 0.6: 20-80 % time 44.9ps typ, 52.6ps min, 35.8ps max; typ from 0.328 V to 0.6 V
|   falling waveform, R_fixture 50, V_fixture 0.0: 20-80 % time 34.6ps typ, 42.4ps min, 30.8ps max; typ from 0.236 V to 0 V
[Pulldown]
|   Voltage   I(typ)   I(min)   I(max)
-600mV    -16.05mA   -15.14mA   -17.4mA
-475.8mV  -12.6mA    -11.6mA    -13.93mA
-312mV    -6.961mA   -6.548mA   -7.571mA
-258mV    -5.364mA   -5.183mA   -5.656mA
-205.8mV  -4.067mA   -4.015mA   -4.134mA
-121.2mV  -2.294mA   -2.299mA   -2.265mA
58.8mV    1.061mA    1.057mA    1.06mA
273mV     4.612mA    4.52mA     4.732mA
498mV     7.628mA    7.255mA    8.165mA
741mV     9.88mA     9.041mA    11.19mA
949.8mV   11.1mA     10.01mA    13.06mA
1.2V      12.12mA    10.89mA    14.55mA
[GND Clamp]
|   Voltage   I(typ)   I(min)   I(max)
-600mV    -5.439mA   -3.802mA   -7.294mA
-567.6mV  -4.11mA    -2.837mA   -5.5mA
-537mV    -3.031mA   -2.085mA   -3.984mA
-510mV    -2.241mA   -1.544mA   -2.838mA
-483mV    -1.608mA   -1.109mA   -1.913mA
-457.8mV  -1.142mA   -788.4uA   -1.267mA
-429mV    -742uA     -509.3uA   -756.6uA
-396.6mV  -428.1uA   -294.7uA   -396.9uA
-358.8mV  -204.6uA   -141.1uA   -167.2uA
-303mV    -56.34uA   -40.78uA   -37uA
-218.4mV  -5.265uA   -4.667uA   -2.174uA
1.2V      0A         0A         0A
[Pullup]
|   Voltage   I(typ)   I(min)   I(max)
-600mV    1.396mA    1.053mA    1.912mA
-295.8mV  1.047mA    780.4uA    1.433mA
-142.8mV  765.2uA    579uA      1.027mA
-79.8mV   521.8uA    410.5uA    679.1uA
-24mV     182.4uA    149.4uA    230.2uA
84mV      -822.3uA   -743.5uA   -958.7uA
193.8mV   -2.211mA   -2.14mA    -2.452mA
346.8mV   -4.455mA   -4.502mA   -4.771mA
638.4mV   -9.173mA   -9.435mA   -9.591mA
1.007V    -15.4mA    -15.74mA   -16.05mA
1.108V    -16.93mA   -17.29mA   -17.71mA
1.2V      -18.09mA   -18.46mA   -18.91mA
[POWER Clamp]
|   Voltage   I(typ)   I(min)   I(max)
-600mV    870.7nA    21.99uA    72.65nA
-589.2mV  630.1nA    16.59uA    68.66nA
-582mV    511.9nA    13.71uA    66.41nA
-576.6mV  439.4nA    11.88uA    64.76nA
-562.2mV  298.6nA    8.053uA    60.55nA
-547.8mV  210.2nA    5.449uA    56.56nA
-529.8mV  144.1nA    3.334uA    51.9nA
-510mV    103.4nA    1.947uA    47.14nA
-483mV    74.6nA     948.3nA    41.22nA
-456mV    59.79nA    475.8nA    35.92nA
-310.2mV  32.36nA    53.68nA    16.04nA
1.2V      0A         0A         0A
[Ramp]
|   typ   min   max
| 20% - 80%
dV/dt_r   141.54m/41.27p   134.48m/44.92p   160.27m/35.74p
dV/dt_f   162.95m/43.39p   153.17m/52.36p   179.40m/36.13p
| 25% - 75%
|dV/dt_r   117.95m/32.72p   112.07m/35.60p   133.56m/28.23p
|dV/dt_f   135.79m/34.33p   127.64m/41.49p   149.50m/28.54p
R_load = 50
[Rising Waveform]
R_fixture = 50
V_fixture = 0.0
|   Time   V(typ)   V(min)   V(max)
0s        90.58uV    74.56uV    46.63uV
58ps      -56.01uV   -24.62uV   4.162mV
67ps      630.6uV    -611.1uV   30.25mV
78ps      5.934mV    -757.7uV   90.34mV
91ps      43.58mV    324.7uV    159.6mV
104ps     101.9mV    13.47mV    205.1mV
137ps     195.3mV    127.7mV    253mV
165ps     222.3mV    187.4mV    263.3mV
201ps     232.7mV    214.3mV    266.4mV
416ps     236mV      224.2mV    267.2mV
[Falling Waveform]
R_fixture   = 50
V_fixture   = 0.6
V_fixture_min = 0.57
V_fixture_max = 0.65
|   Time   V(typ)   V(min)   V(max)
0s        600mV      570mV      650mV
73ps      599mV      570.3mV    644.8mV
80ps      598.6mV    569.5mV    617.8mV
94ps      590.8mV    567.7mV    523.3mV
110ps     527.2mV    567.5mV    442.6mV
126ps     451.6mV    546.9mV    398.6mV
151ps     380.2mV    456.7mV    367.7mV
183ps     344.7mV    372.2mV    355.3mV
221ps     332.5mV    332.6mV    351.9mV
416ps     328.4mV    314.7mV    351mV
[Rising Waveform]
R_fixture   = 50
V_fixture   = 0.6
V_fixture_min = 0.57
V_fixture_max = 0.65
|   Time   V(typ)   V(min)   V(max)
0s        328.4mV    314.6mV    351mV
61ps      328.5mV    312.5mV    361.8mV
68ps      334.3mV    312.2mV    386.5mV
77ps      354.1mV    316mV      450.7mV
98ps      450.7mV    368.7mV    562.7mV
116ps     516.1mV    437.8mV    607.3mV
137ps     558.9mV    495.4mV    631.2mV
166ps     584.6mV    538.7mV    643.8mV
206ps     595.9mV    560.7mV    648.6mV
416ps     600mV      570mV      650mV
[Falling Waveform]
R_fixture = 50
V_fixture = 0.0
|   Time   V(typ)   V(min)   V(max)
0s        236mV      224.3mV    267.2mV
63ps      238.1mV    225.9mV    259.8mV
72ps      235.3mV    226.9mV    227.4mV
82ps      220.6mV    225.9mV    154.9mV
98ps      151.6mV    209.4mV    73.7mV
115ps     74.53mV    156.5mV    34.02mV
134ps     33.01mV    85.94mV    14.41mV
160ps     11.1mV     31.63mV    4.507mV
195ps     2.731mV    8.145mV    991.9uV
416ps     157uV      166.6uV    67.21uV
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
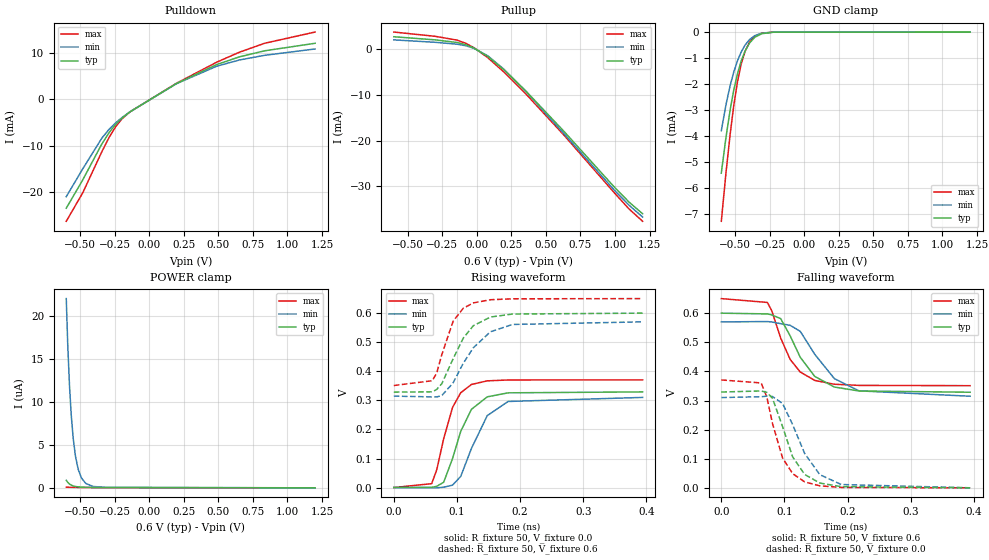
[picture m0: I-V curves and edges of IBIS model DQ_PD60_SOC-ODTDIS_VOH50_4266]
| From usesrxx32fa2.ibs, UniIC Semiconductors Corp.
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| DQ_PD60_SOC-ODTDIS_VOH50_4266
| (60 Ohm Pulldown, SOC ODT disabled setting, VOH=VDDQ*0.50 cal. point, 3200-4266Mbps)
[Model]   DQ_PD60_SOC-ODTDIS_VOH50_4266
Model_type   I/O
Vinl = 90.000mV
Vinh = 210.000mV
Vmeas = 150.000mV
Vref = 0.0mV
Cref = 0.0pF
|   typ   min   max
|C_comp   0.834pF   0.784pF   0.884pF
C_comp_pullup   0.4170pF   0.3920pF   0.4420pF
C_comp_pulldown   0.4170pF   0.3920pF   0.4420pF
| Note: C_comp changes when the ODT circuit is enabled.
[Model Spec]
| Input threshold voltage corners
Vinl   0.0900V   0.0825V   0.1025V
Vinh   0.2100V   0.2025V   0.2225V
| Measurement voltage corners
Vmeas   0.1500V   0.1425V   0.1625V
| Timing spec test load voltage corners
Vref   0.0000V   0.0000V   0.0000V
| Dynamic Overshoot Parameters from LPDDR4_0P6 Specification
D_overshoot_ampl_h   0.30   NA   NA
D_overshoot_ampl_l   0.30   NA   NA
D_overshoot_area_h   0.1n   NA   NA
D_overshoot_area_l   0.1n   NA   NA
[Voltage Range]   0.6000V   0.5700V   0.6500V
[Pullup Reference]   0.6000V   0.5700V   0.6500V
| Junction Temperature (Ambient temp is 35C typ 95C min -40C max)
[Temperature Range]   50.0   110.0   -40.0
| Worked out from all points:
|   slope of the pulldown table from 0 to 0.09 V, typ, clamps not added: 55.6 ohm
|   slope of the pullup table from 0 to 0.09 V, typ, clamps not added: 50.7 ohm
|   GND clamp passes 1 mA (typ) near -0.45 V on its own axis
|   rising waveform, R_fixture 50, V_fixture 0.0: 20-80 % time 32.7ps typ, 37.3ps min, 27.7ps max; typ from 0 V to 0.329 V
|   falling waveform, R_fixture 50, V_fixture 0.6: 20-80 % time 43.9ps typ, 53.4ps min, 36.3ps max; typ from 0.6 V to 0.328 V
|   rising waveform, R_fixture 50, V_fixture 0.6: 20-80 % time 38.6ps typ, 46.7ps min, 28.4ps max; typ from 0.328 V to 0.6 V
|   falling waveform, R_fixture 50, V_fixture 0.0: 20-80 % time 34ps typ, 41.2ps min, 30ps max; typ from 0.329 V to 0 V
[Pulldown]
|   Voltage   I(typ)   I(min)   I(max)
-600mV    -23.55mA   -21.06mA   -26.38mA
-481.2mV  -17.45mA   -15.06mA   -20.25mA
-342.6mV  -9.652mA   -8.396mA   -11.33mA
-288.6mV  -7.134mA   -6.436mA   -8.157mA
-243.6mV  -5.454mA   -5.113mA   -5.967mA
-196.8mV  -4.077mA   -3.952mA   -4.227mA
-139.2mV  -2.724mA   -2.701mA   -2.709mA
197.4mV   3.422mA    3.377mA    3.474mA
489mV     7.524mA    7.167mA    8.038mA
652.8mV   9.185mA    8.506mA    10.19mA
834.6mV   10.49mA    9.515mA    12.12mA
1.2V      12.12mA    10.89mA    14.55mA
[GND Clamp]
|   Voltage   I(typ)   I(min)   I(max)
-600mV    -5.439mA   -3.802mA   -7.294mA
-565.8mV  -4.041mA   -2.789mA   -5.405mA
-535.2mV  -2.973mA   -2.045mA   -3.902mA
-510mV    -2.24mA    -1.545mA   -2.838mA
-483mV    -1.605mA   -1.108mA   -1.914mA
-456mV    -1.114mA   -767.8uA   -1.23mA
-429mV    -742.8uA   -509.3uA   -757.3uA
-396.6mV  -429.3uA   -295.2uA   -396.7uA
-358.8mV  -205.4uA   -141.1uA   -167.6uA
-308.4mV  -64.28uA   -46.29uA   -43.28uA
-222mV    -5.836uA   -5.163uA   -2.495uA
1.2V      0A         0A         0A
[Pullup]
|   Voltage   I(typ)   I(min)   I(max)
-600mV    2.791mA    2.105mA    3.822mA
-299.4mV  2.102mA    1.567mA    2.878mA
-142.8mV  1.529mA    1.157mA    2.05mA
-79.8mV   1.041mA    820uA      1.354mA
-20.4mV   310.6uA    256.2uA    392.9uA
80.4mV    -1.557mA   -1.404mA   -1.819mA
195.6mV   -4.447mA   -4.307mA   -4.93mA
352.2mV   -9.023mA   -9.121mA   -9.658mA
633mV     -18.05mA   -18.56mA   -18.88mA
993mV     -30.14mA   -30.82mA   -31.39mA
1.101V    -33.49mA   -34.18mA   -35mA
1.2V      -36.08mA   -36.8mA    -37.73mA
[POWER Clamp]
|   Voltage   I(typ)   I(min)   I(max)
-600mV    870.6nA    21.99uA    72.65nA
-589.2mV  630.1nA    16.59uA    68.66nA
-576.6mV  439.1nA    11.87uA    64.76nA
-564mV    312.9nA    8.453uA    61.06nA
-549.6mV  219.5nA    5.715uA    57.05nA
-533.4mV  154.6nA    3.672uA    52.81nA
-513.6mV  109nA      2.144uA    47.98nA
-490.2mV  80.15nA    1.144uA    42.74nA
-459.6mV  61.26nA    519.5nA    36.6nA
-405.6mV  45.9nA     157.1nA    27.53nA
-317.4mV  33.15nA    55.98nA    16.74nA
1.2V      0A         0A         0A
[Ramp]
|   typ   min   max
| 20% - 80%
dV/dt_r   197.34m/32.66p   185.98m/37.33p   222.26m/27.74p
dV/dt_f   162.94m/43.94p   153.15m/53.41p   179.40m/36.34p
| 25% - 75%
|dV/dt_r   164.45m/25.85p   154.98m/29.56p   185.22m/21.90p
|dV/dt_f   135.79m/34.73p   127.63m/42.22p   149.50m/28.70p
R_load = 50
[Rising Waveform]
R_fixture = 50
V_fixture = 0.0
|   Time   V(typ)   V(min)   V(max)
0s        202.1uV    184.1uV    95.94uV
60ps      880.3uV    -619.9uV   13.47mV
68ps      4.328mV    -873.9uV   61.04mV
79ps      18.28mV    1.364mV    168.1mV
93ps      99.66mV    8.303mV    275.6mV
106ps     193.5mV    38.46mV    326.3mV
123ps     269.3mV    134.9mV    354.7mV
148ps     312.1mV    247.5mV    367.1mV
181ps     325.9mV    296.2mV    370.1mV
394ps     329.1mV    310.1mV    370.5mV
[Falling Waveform]
R_fixture   = 50
V_fixture   = 0.6
V_fixture_min = 0.57
V_fixture_max = 0.65
|   Time   V(typ)   V(min)   V(max)
0s        600mV      570mV      650mV
73ps      597.4mV    571.2mV    636.8mV
80ps      594mV      569.7mV    607.7mV
94ps      581.3mV    563.9mV    514.5mV
109ps     522.2mV    558.3mV    441.3mV
125ps     448.5mV    537.6mV    397.9mV
148ps     382.7mV    458.6mV    369mV
179ps     346.3mV    375.3mV    355.9mV
218ps     332.7mV    333.2mV    351.9mV
394ps     328.4mV    314.7mV    351mV
[Rising Waveform]
R_fixture   = 50
V_fixture   = 0.6
V_fixture_min = 0.57
V_fixture_max = 0.65
|   Time   V(typ)   V(min)   V(max)
0s        328.4mV    314.6mV    351mV
61ps      329.4mV    311.9mV    367.6mV
68ps      337.7mV    311.8mV    394.6mV
76ps      357.2mV    316.3mV    456.8mV
94ps      443.3mV    360.3mV    572.5mV
110ps     514mV      427.6mV    616.7mV
126ps     556.8mV    481mV      635.3mV
153ps     586.6mV    535.9mV    646.1mV
188ps     596.9mV    561.1mV    649.3mV
394ps     600mV      570mV      650mV
[Falling Waveform]
R_fixture = 50
V_fixture = 0.0
|   Time   V(typ)   V(min)   V(max)
0s        329.2mV    310.2mV    370.6mV
63ps      332.8mV    313mV      360.4mV
72ps      328.1mV    315mV      313mV
81ps      308.1mV    313.9mV    221.3mV
97ps      210.4mV    289.6mV    102.6mV
113ps     106.3mV    217mV      48.81mV
132ps     46.11mV    118mV      20.5mV
156ps     16.49mV    45.28mV    6.982mV
190ps     4.144mV    11.47mV    1.593mV
394ps     251.7uV    253.4uV    115.9uV
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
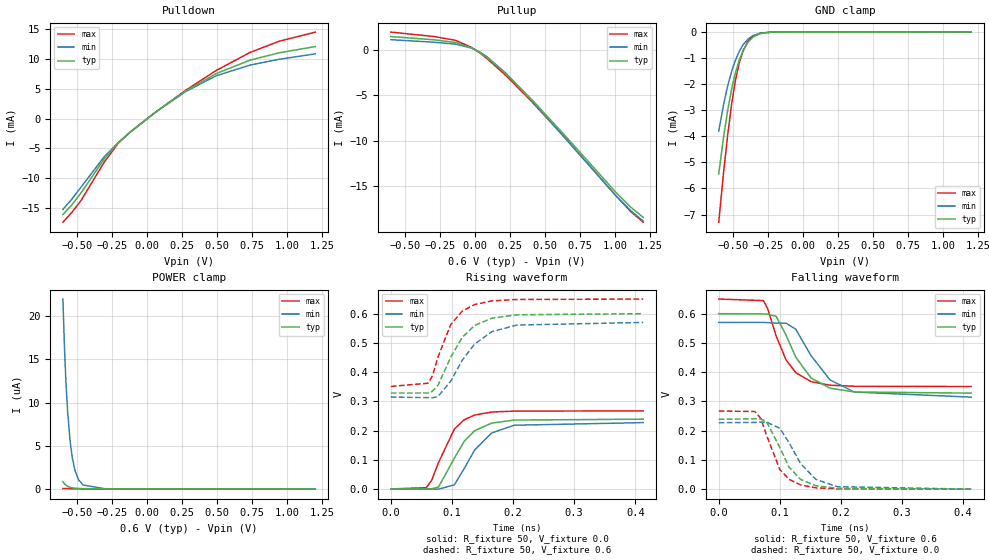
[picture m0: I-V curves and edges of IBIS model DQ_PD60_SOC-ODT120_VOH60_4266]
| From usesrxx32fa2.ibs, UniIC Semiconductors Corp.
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| DQ_PD60_SOC-ODT120_VOH60_4266
| (60 Ohm Pulldown, 120 Ohm System ODT Setting, VOH=VDDQ*0.60, 3200-4266Mbps)
[Model]   DQ_PD60_SOC-ODT120_VOH60_4266
Model_type   I/O
Vinl = 120.000mV
Vinh = 240.000mV
Vmeas = 180.000mV
Vref = 0.0mV
Cref = 0.0pF
Rref = 120.000Ohm
|   typ   min   max
|C_comp   0.834pF   0.784pF   0.884pF
C_comp_pullup   0.4170pF   0.3920pF   0.4420pF
C_comp_pulldown   0.4170pF   0.3920pF   0.4420pF
| Note: C_comp changes when the ODT circuit is enabled.
[Model Spec]
| Input threshold voltage corners
Vinl   0.1200V   0.1110V   0.1350V
Vinh   0.2400V   0.2310V   0.2550V
| Measurement voltage corners
Vmeas   0.1800V   0.1710V   0.1950V
| Timing spec test load voltage corners
Vref   0.0000V   0.0000V   0.0000V
| Dynamic Overshoot Parameters from LPDDR4_0P6 Specification
D_overshoot_ampl_h   0.30   NA   NA
D_overshoot_ampl_l   0.30   NA   NA
D_overshoot_area_h   0.1n   NA   NA
D_overshoot_area_l   0.1n   NA   NA
[Voltage Range]   0.6000V   0.5700V   0.6500V
[Pullup Reference]   0.6000V   0.5700V   0.6500V
| Junction Temperature (Ambient temp is 35C typ 95C min -40C max)
[Temperature Range]   50.0   110.0   -40.0
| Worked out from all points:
|   slope of the pulldown table from 0 to 0.09 V, typ, clamps not added: 55.7 ohm
|   slope of the pullup table from 0 to 0.09 V, typ, clamps not added: 98.7 ohm
|   GND clamp passes 1 mA (typ) near -0.45 V on its own axis
|   rising waveform, R_fixture 50, V_fixture 0.0: 20-80 % time 40.7ps typ, 44.2ps min, 35.7ps max; typ from 0 V to 0.239 V
|   falling waveform, R_fixture 50, V_fixture 0.6: 20-80 % time 43.4ps typ, 52.4ps min, 36.1ps max; typ from 0.6 V to 0.328 V
|   rising waveform, R_fixture 50, V_fixture 0.6: 20-80 % time 44.6ps typ, 52.3ps min, 35.8ps max; typ from 0.328 V to 0.6 V
|   falling waveform, R_fixture 50, V_fixture 0.0: 20-80 % time 34.6ps typ, 42.3ps min, 30.8ps max; typ from 0.239 V to 0 V
[Pulldown]
|   Voltage   I(typ)   I(min)   I(max)
-600mV    -16.12mA   -15.25mA   -17.4mA
-537mV    -14.51mA   -13.55mA   -15.77mA
-472.2mV  -12.53mA   -11.56mA   -13.81mA
-304.8mV  -6.754mA   -6.379mA   -7.299mA
-204mV    -4.031mA   -3.983mA   -4.088mA
-115.8mV  -2.189mA   -2.195mA   -2.159mA
60.6mV    1.093mA    1.089mA    1.093mA
274.8mV   4.639mA    4.546mA    4.761mA
492.6mV   7.566mA    7.202mA    8.089mA
735.6mV   9.842mA    9.011mA    11.14mA
942.6mV   11.07mA    9.98mA     13.01mA
1.2V      12.12mA    10.89mA    14.55mA
[GND Clamp]
|   Voltage   I(typ)   I(min)   I(max)
-600mV    -5.44mA    -3.802mA   -7.294mA
-565.8mV  -4.041mA   -2.789mA   -5.405mA
-537mV    -3.03mA    -2.085mA   -3.984mA
-508.2mV  -2.193mA   -1.511mA   -2.769mA
-481.2mV  -1.57mA    -1.083mA   -1.86mA
-454.2mV  -1.086mA   -747.4uA   -1.192mA
-425.4mV  -704.3uA   -480.6uA   -706.9uA
-391.2mV  -391.2uA   -265.6uA   -353.1uA
-357mV    -199.5uA   -135.7uA   -159.8uA
-303mV    -56.21uA   -40.79uA   -37.01uA
-225.6mV  -4.707uA   -5.69uA    -2.857uA
1.2V      0A         0A         0A
[Pullup]
|   Voltage   I(typ)   I(min)   I(max)
-600mV    1.424mA    1.081mA    1.912mA
-294mV    1.07mA     804.2uA    1.43mA
-139.2mV  774.5uA    593.1uA    1.011mA
-25.8mV   199.8uA    165.1uA    246.5uA
30mV      -268.2uA   -232.7uA   -317.5uA
84mV      -841.3uA   -766.2uA   -958.8uA
220.8mV   -2.643mA   -2.598mA   -2.845mA
399mV     -5.379mA   -5.486mA   -5.603mA
636.6mV   -9.328mA   -9.6mA     -9.561mA
1.009V    -15.71mA   -16.07mA   -16.08mA
1.114V    -17.31mA   -17.68mA   -17.79mA
1.2V      -18.38mA   -18.78mA   -18.91mA
[POWER Clamp]
|   Voltage   I(typ)   I(min)   I(max)
-600mV    870.7nA    21.99uA    72.65nA
-589.2mV  630.1nA    16.59uA    68.66nA
-583.8mV  538.5nA    14.38uA    66.97nA
-576.6mV  439.2nA    11.87uA    64.76nA
-565.8mV  327.7nA    8.875uA    61.58nA
-549.6mV  219.4nA    5.716uA    57.05nA
-533.4mV  154.6nA    3.676uA    52.81nA
-513.6mV  108.9nA    2.142uA    47.98nA
-488.4mV  78.72nA    1.091uA    42.35nA
-456mV    59.7nA     475.2nA    35.93nA
-297.6mV  31.03nA    50.26nA    14.88nA
1.2V      0A         0A         0A
[Ramp]
|   typ   min   max
| 20% - 80%
dV/dt_r   143.20m/40.73p   136.23m/44.17p   160.27m/35.74p
dV/dt_f   162.95m/43.37p   153.17m/52.36p   179.40m/36.13p
| 25% - 75%
|dV/dt_r   119.34m/32.28p   113.53m/35.00p   133.56m/28.23p
|dV/dt_f   135.79m/34.32p   127.64m/41.49p   149.50m/28.54p
R_load = 50
[Rising Waveform]
R_fixture = 50
V_fixture = 0.0
|   Time   V(typ)   V(min)   V(max)
0s        93.21uV    79.48uV    46.63uV
58ps      -54.09uV   -17.94uV   4.162mV
67ps      631.6uV    -607.2uV   30.25mV
78ps      6.096mV    -756.5uV   90.34mV
104ps     105.4mV    14.11mV    205.1mV
120ps     162.9mV    69.44mV    236.5mV
137ps     199mV      132.6mV    253mV
165ps     225.5mV    191.6mV    263.3mV
202ps     235.8mV    218.1mV    266.5mV
413ps     238.8mV    227.1mV    267.2mV
[Falling Waveform]
R_fixture   = 50
V_fixture   = 0.6
V_fixture_min = 0.57
V_fixture_max = 0.65
|   Time   V(typ)   V(min)   V(max)
0s        600mV      570mV      650mV
73ps      599.1mV    570.3mV    644.8mV
80ps      598.6mV    569.5mV    617.8mV
94ps      590.8mV    567.7mV    523.3mV
110ps     527.3mV    567.6mV    442.6mV
126ps     451.6mV    546.9mV    398.6mV
151ps     380.2mV    456.8mV    367.7mV
182ps     345.3mV    373.9mV    355.5mV
222ps     332.3mV    332mV      351.8mV
413ps     328.4mV    314.7mV    351mV
[Rising Waveform]
R_fixture   = 50
V_fixture   = 0.6
V_fixture_min = 0.57
V_fixture_max = 0.65
|   Time   V(typ)   V(min)   V(max)
0s        328.4mV    314.6mV    351mV
61ps      328.5mV    312.5mV    361.8mV
68ps      334.3mV    312.2mV    386.5mV
77ps      354.1mV    316mV      450.7mV
98ps      450.7mV    368.7mV    562.7mV
117ps     519.4mV    441mV      608.9mV
137ps     559.4mV    495.7mV    631.2mV
165ps     584.4mV    538.2mV    643.6mV
206ps     596.1mV    561mV      648.6mV
413ps     600mV      570mV      650mV
[Falling Waveform]
R_fixture = 50
V_fixture = 0.0
|   Time   V(typ)   V(min)   V(max)
0s        238.8mV    227.2mV    267.2mV
59ps      240.8mV    228.2mV    265.6mV
69ps      239.6mV    229.6mV    241.8mV
78ps      231.6mV    229.6mV    185.6mV
100ps     142.5mV    208.1mV    67.26mV
115ps     75.67mV    159.1mV    34.02mV
134ps     33.49mV    87.33mV    14.41mV
159ps     11.73mV    33.41mV    4.706mV
194ps     2.847mV    8.562mV    1.035mV
413ps     162.2uV    172.4uV    67.23uV
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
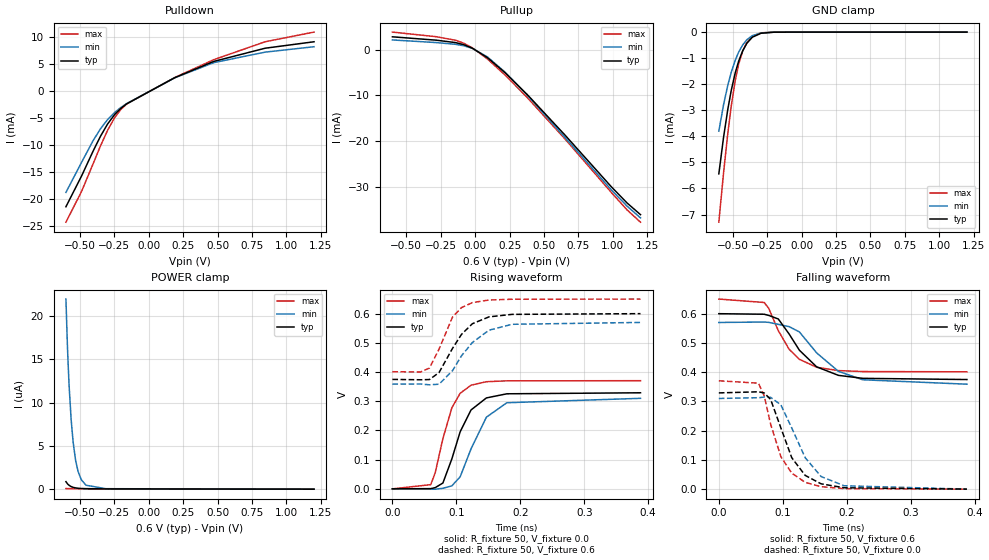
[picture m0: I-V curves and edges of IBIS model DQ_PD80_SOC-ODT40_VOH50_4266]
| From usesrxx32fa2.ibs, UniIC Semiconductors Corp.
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| DQ_PD80_SOC-ODT40_VOH50_4266
| (80 Ohm Pulldown, 40 Ohm System ODT Setting, VOH=VDDQ*0.50, 3200-4266Mbps)
[Model]   DQ_PD80_SOC-ODT40_VOH50_4266
Model_type   I/O
Vinl = 90.000mV
Vinh = 210.000mV
Vmeas = 150.000mV
Vref = 0.0mV
Cref = 0.0pF
Rref = 40.000Ohm
|   typ   min   max
|C_comp   0.834pF   0.784pF   0.884pF
C_comp_pullup   0.4170pF   0.3920pF   0.4420pF
C_comp_pulldown   0.4170pF   0.3920pF   0.4420pF
| Note: C_comp changes when the ODT circuit is enabled.
[Model Spec]
| Input threshold voltage corners
Vinl   0.0900V   0.0825V   0.1025V
Vinh   0.2100V   0.2025V   0.2225V
| Measurement voltage corners
Vmeas   0.1500V   0.1425V   0.1625V
| Timing spec test load voltage corners
Vref   0.0000V   0.0000V   0.0000V
| Dynamic Overshoot Parameters from LPDDR4_0P6 Specification
D_overshoot_ampl_h   0.30   NA   NA
D_overshoot_ampl_l   0.30   NA   NA
D_overshoot_area_h   0.1n   NA   NA
D_overshoot_area_l   0.1n   NA   NA
[Voltage Range]   0.6000V   0.5700V   0.6500V
[Pullup Reference]   0.6000V   0.5700V   0.6500V
| Junction Temperature (Ambient temp is 35C typ 95C min -40C max)
[Temperature Range]   50.0   110.0   -40.0
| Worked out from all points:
|   slope of the pulldown table from 0 to 0.09 V, typ, clamps not added: 75.3 ohm
|   slope of the pullup table from 0 to 0.09 V, typ, clamps not added: 50.7 ohm
|   GND clamp passes 1 mA (typ) near -0.45 V on its own axis
|   rising waveform, R_fixture 50, V_fixture 0.0: 20-80 % time 32.7ps typ, 37.6ps min, 27.7ps max; typ from 0 V to 0.329 V
|   falling waveform, R_fixture 50, V_fixture 0.6: 20-80 % time 48.6ps typ, 58.3ps min, 40.1ps max; typ from 0.6 V to 0.375 V
|   rising waveform, R_fixture 50, V_fixture 0.6: 20-80 % time 39.8ps typ, 45.9ps min, 29.7ps max; typ from 0.375 V to 0.6 V
|   falling waveform, R_fixture 50, V_fixture 0.0: 20-80 % time 36.9ps typ, 43.5ps min, 33.1ps max; typ from 0.329 V to 0 V
[Pulldown]
|   Voltage   I(typ)   I(min)   I(max)
-600mV    -21.37mA   -18.73mA   -24.22mA
-486.6mV  -15.7mA    -13.18mA   -18.54mA
-403.8mV  -11.16mA   -9.221mA   -13.51mA
-349.8mV  -8.393mA   -7.008mA   -10.18mA
-297.6mV  -6.104mA   -5.283mA   -7.266mA
-247.2mV  -4.387mA   -3.998mA   -4.958mA
-204mV    -3.282mA   -3.118mA   -3.489mA
-159mV    -2.389mA   -2.337mA   -2.413mA
190.2mV   2.441mA    2.415mA    2.467mA
472.8mV   5.433mA    5.206mA    5.755mA
845.4mV   7.865mA    7.145mA    9.059mA
1.2V      9.057mA    8.141mA    10.84mA
[GND Clamp]
|   Voltage   I(typ)   I(min)   I(max)
-600mV    -5.439mA   -3.802mA   -7.294mA
-565.8mV  -4.041mA   -2.789mA   -5.405mA
-535.2mV  -2.973mA   -2.045mA   -3.903mA
-510mV    -2.24mA    -1.545mA   -2.839mA
-481.2mV  -1.568mA   -1.083mA   -1.861mA
-456mV    -1.113mA   -767.6uA   -1.23mA
-427.2mV  -721.2uA   -495.3uA   -731.8uA
-396.6mV  -428.4uA   -293uA     -396.8uA
-357mV    -197.1uA   -136.8uA   -160uA
-294mV    -44.67uA   -33.01uA   -28.56uA
-196.8mV  -2.656uA   -2.559uA   -932.7nA
1.2V      0A         0A         0A
[Pullup]
|   Voltage   I(typ)   I(min)   I(max)
-600mV    2.791mA    2.105mA    3.822mA
-281.4mV  2.053mA    1.53mA     2.81mA
-141mV    1.519mA    1.15mA     2.035mA
-81.6mV   1.06mA     832.9uA    1.379mA
-20.4mV   311.1uA    256.1uA    392.9uA
89.4mV    -1.76mA    -1.598mA   -2.045mA
219mV     -5.095mA   -4.981mA   -5.609mA
379.2mV   -9.856mA   -10mA      -10.51mA
654.6mV   -18.77mA   -19.3mA    -19.62mA
989.4mV   -30.02mA   -30.7mA    -31.27mA
1.103V    -33.54mA   -34.23mA   -35.06mA
1.2V      -36.08mA   -36.8mA    -37.73mA
[POWER Clamp]
|   Voltage   I(typ)   I(min)   I(max)
-600mV    870.6nA    21.99uA    72.65nA
-589.2mV  630.2nA    16.59uA    68.66nA
-583.8mV  538.6nA    14.38uA    66.97nA
-576.6mV  439.6nA    11.87uA    64.76nA
-562.2mV  299.2nA    8.051uA    60.55nA
-547.8mV  210.6nA    5.446uA    56.57nA
-529.8mV  143.9nA    3.327uA    51.91nA
-511.8mV  105.9nA    2.045uA    47.56nA
-488.4mV  78.55nA    1.091uA    42.35nA
-454.2mV  58.99nA    454.8nA    35.6nA
-310.2mV  32.36nA    53.65nA    16.04nA
1.2V      0A         0A         0A
[Ramp]
|   typ   min   max
| 20% - 80%
dV/dt_r   197.32m/32.74p   185.96m/37.61p   222.25m/27.69p
dV/dt_f   135.05m/48.58p   126.59m/58.26p   149.25m/40.12p
| 25% - 75%
|dV/dt_r   164.43m/25.91p   154.97m/29.78p   185.21m/21.89p
|dV/dt_f   112.54m/38.38p   105.49m/45.98p   124.38m/31.64p
R_load = 50
[Rising Waveform]
R_fixture = 50
V_fixture = 0.0
|   Time   V(typ)   V(min)   V(max)
0s        233.6uV    215.7uV    109.5uV
60ps      848.3uV    -752.8uV   14.52mV
67ps      4.316mV    -944.1uV   55.44mV
79ps      20.15mV    2.063mV    172.2mV
93ps      102.7mV    10.38mV    277.8mV
106ps     195.6mV    41.43mV    327.4mV
123ps     270.3mV    137.1mV    355.1mV
147ps     311.5mV    245.5mV    367mV
179ps     325.6mV    295mV      370mV
388ps     329.1mV    310.1mV    370.5mV
[Falling Waveform]
R_fixture   = 50
V_fixture   = 0.6
V_fixture_min = 0.57
V_fixture_max = 0.65
|   Time   V(typ)   V(min)   V(max)
0s        600mV      570mV      650mV
71ps      598.1mV    571.5mV    638.3mV
78ps      594.1mV    570.3mV    618.3mV
93ps      581.9mV    563.5mV    542mV
110ps     530.3mV    555.7mV    478.1mV
126ps     475.1mV    537.6mV    444mV
153ps     418.2mV    466mV      416.8mV
187ps     389.2mV    403mV      405.5mV
225ps     379mV      374.1mV    402.2mV
388ps     374.9mV    359mV      401.3mV
[Rising Waveform]
R_fixture   = 50
V_fixture   = 0.6
V_fixture_min = 0.57
V_fixture_max = 0.65
|   Time   V(typ)   V(min)   V(max)
0s        374.9mV    358.8mV    401.2mV
44ps      373.6mV    359.1mV    400.3mV
58ps      374.4mV    356.4mV    413.8mV
73ps      398.5mV    358.5mV    478.7mV
94ps      481mV      404.6mV    588.2mV
108ps     528.8mV    455.4mV    620.6mV
125ps     565.5mV    501.1mV    637.8mV
151ps     589mV      543.3mV    646.7mV
187ps     597.6mV    563.6mV    649.4mV
388ps     600mV      570mV      650mV
[Falling Waveform]
R_fixture = 50
V_fixture = 0.0
|   Time   V(typ)   V(min)   V(max)
0s        329.2mV    310.2mV    370.6mV
62ps      333mV      312.8mV    362.5mV
71ps      328.9mV    315mV      319mV
81ps      306.9mV    313.9mV    222.3mV
97ps      209.7mV    288.4mV    111.3mV
114ps     107.8mV    209.5mV    55.02mV
135ps     47.24mV    107.8mV    23.42mV
160ps     18.36mV    43.23mV    8.573mV
196ps     4.934mV    11.77mV    2.096mV
388ps     286.1uV    299.2uV    143.5uV
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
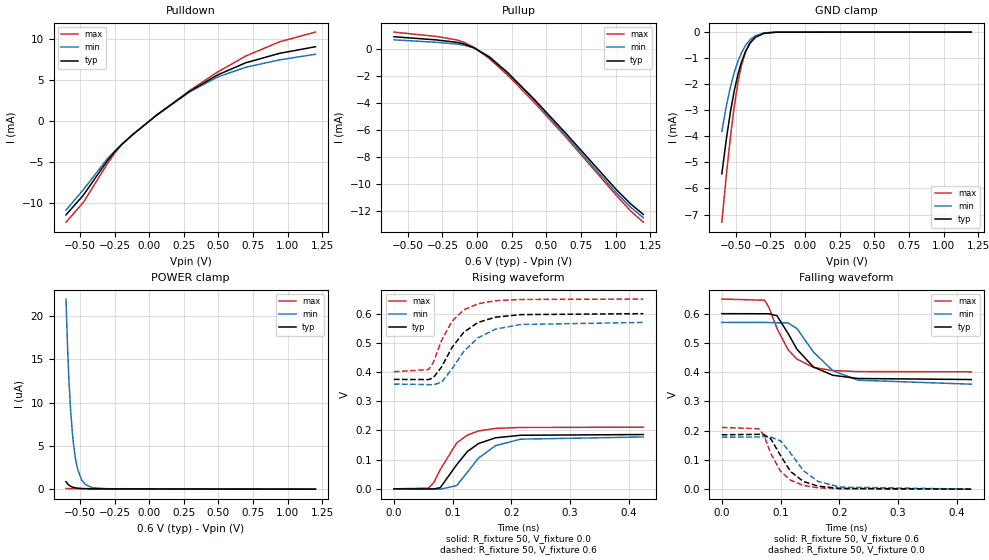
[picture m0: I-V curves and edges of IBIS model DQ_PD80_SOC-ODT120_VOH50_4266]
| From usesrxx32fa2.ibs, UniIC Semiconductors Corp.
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| DQ_PD80_SOC-ODT120_VOH50_4266
| (80 Ohm Pulldown, 120 Ohm System ODT Setting, VOH=VDDQ*0.50, 3200-4266Mbps)
[Model]   DQ_PD80_SOC-ODT120_VOH50_4266
Model_type   I/O
Vinl = 90.000mV
Vinh = 210.000mV
Vmeas = 150.000mV
Vref = 0.0mV
Cref = 0.0pF
Rref = 120.000Ohm
|   typ   min   max
|C_comp   0.834pF   0.784pF   0.884pF
C_comp_pullup   0.4170pF   0.3920pF   0.4420pF
C_comp_pulldown   0.4170pF   0.3920pF   0.4420pF
| Note: C_comp changes when the ODT circuit is enabled.
[Model Spec]
| Input threshold voltage corners
Vinl   0.0900V   0.0825V   0.1025V
Vinh   0.2100V   0.2025V   0.2225V
| Measurement voltage corners
Vmeas   0.1500V   0.1425V   0.1625V
| Timing spec test load voltage corners
Vref   0.0000V   0.0000V   0.0000V
| Dynamic Overshoot Parameters from LPDDR4_0P6 Specification
D_overshoot_ampl_h   0.30   NA   NA
D_overshoot_ampl_l   0.30   NA   NA
D_overshoot_area_h   0.1n   NA   NA
D_overshoot_area_l   0.1n   NA   NA
[Voltage Range]   0.6000V   0.5700V   0.6500V
[Pullup Reference]   0.6000V   0.5700V   0.6500V
| Junction Temperature (Ambient temp is 35C typ 95C min -40C max)
[Temperature Range]   50.0   110.0   -40.0
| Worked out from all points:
|   slope of the pulldown table from 0 to 0.09 V, typ, clamps not added: 75.5 ohm
|   slope of the pullup table from 0 to 0.09 V, typ, clamps not added: 150 ohm
|   GND clamp passes 1 mA (typ) near -0.45 V on its own axis
|   rising waveform, R_fixture 50, V_fixture 0.0: 20-80 % time 45.4ps typ, 49.8ps min, 40ps max; typ from 0 V to 0.186 V
|   falling waveform, R_fixture 50, V_fixture 0.6: 20-80 % time 47.6ps typ, 56.3ps min, 39.8ps max; typ from 0.6 V to 0.375 V
|   rising waveform, R_fixture 50, V_fixture 0.6: 20-80 % time 48.5ps typ, 55.3ps min, 40.2ps max; typ from 0.375 V to 0.6 V
|   falling waveform, R_fixture 50, V_fixture 0.0: 20-80 % time 38ps typ, 45.1ps min, 34.1ps max; typ from 0.186 V to 0 V
[Pulldown]
|   Voltage   I(typ)   I(min)   I(max)
-600mV    -11.43mA   -10.85mA   -12.32mA
-474mV    -9.009mA   -8.345mA   -9.893mA
-303mV    -4.867mA   -4.62mA    -5.233mA
-249mV    -3.752mA   -3.652mA   -3.905mA
-196.8mV  -2.836mA   -2.814mA   -2.855mA
-117.6mV  -1.637mA   -1.642mA   -1.611mA
55.2mV    735.8uA    734.1uA    732.6uA
292.8mV   3.63mA     3.559mA    3.721mA
492.6mV   5.607mA    5.355mA    5.964mA
697.8mV   7.106mA    6.559mA    7.924mA
940.8mV   8.25mA     7.454mA    9.655mA
1.2V      9.057mA    8.141mA    10.84mA
[GND Clamp]
|   Voltage   I(typ)   I(min)   I(max)
-600mV    -5.439mA   -3.802mA   -7.294mA
-565.8mV  -4.041mA   -2.788mA   -5.405mA
-537mV    -3.031mA   -2.087mA   -3.984mA
-510mV    -2.241mA   -1.544mA   -2.838mA
-483mV    -1.606mA   -1.11mA    -1.914mA
-459.6mV  -1.171mA   -808.3uA   -1.307mA
-429mV    -742uA     -511uA     -756.4uA
-394.8mV  -414.9uA   -284.9uA   -382.3uA
-357mV    -197uA     -136.2uA   -159.7uA
-294mV    -44.82uA   -33.15uA   -28.47uA
-202.2mV  -3.155uA   -2.98uA    -1.155uA
1.2V      0A         0A         0A
[Pullup]
|   Voltage   I(typ)   I(min)   I(max)
-600mV    931.5uA    702.4uA    1.276mA
-294mV    697.1uA    519.5uA    954.8uA
-146.4mV  518.2uA    391.4uA    696.9uA
-88.8mV   378.4uA    295.4uA    495.5uA
-20.4mV   104.9uA    86.17uA    132.3uA
87.6mV    -581uA     -526.9uA   -676.4uA
220.8mV   -1.745mA   -1.71mA    -1.92mA
406.2mV   -3.636mA   -3.708mA   -3.862mA
642mV     -6.244mA   -6.429mA   -6.524mA
1.007V    -10.42mA   -10.66mA   -10.85mA
1.11V     -11.47mA   -11.72mA   -12mA
1.2V      -12.24mA   -12.48mA   -12.81mA
[POWER Clamp]
|   Voltage   I(typ)   I(min)   I(max)
-600mV    870.6nA    21.99uA    72.65nA
-589.2mV  630.3nA    16.59uA    68.66nA
-578.4mV  462.3nA    12.46uA    65.31nA
-565.8mV  328.1nA    8.874uA    61.58nA
-549.6mV  219.5nA    5.721uA    57.05nA
-531.6mV  149.5nA    3.496uA    52.35nA
-515.4mV  112.2nA    2.254uA    48.4nA
-486.6mV  77.17nA    1.042uA    41.98nA
-461.4mV  61.98nA    543.9nA    36.94nA
-411mV    46.97nA    175nA      28.34nA
-310.2mV  32.36nA    53.65nA    16.04nA
1.2V      0A         0A         0A
[Ramp]
|   typ   min   max
| 20% - 80%
dV/dt_r   111.53m/45.44p   106.51m/49.82p   126.61m/39.97p
dV/dt_f   135.04m/47.57p   126.62m/56.34p   149.25m/39.75p
| 25% - 75%
|dV/dt_r   92.94m/36.04p   88.76m/39.49p   105.51m/31.63p
|dV/dt_f   112.54m/37.70p   105.52m/44.70p   124.37m/31.45p
R_load = 50
[Rising Waveform]
R_fixture = 50
V_fixture = 0.0
|   Time   V(typ)   V(min)   V(max)
0s        64.53uV    50.91uV    33.91uV
59ps      -452.3uV   -36.09uV   2.428mV
68ps      -284.2uV   -651.9uV   22.03mV
79ps      4.091mV    -1.112mV   66.18mV
107ps     82.77mV    11.04mV    157.2mV
125ps     127.4mV    56.42mV    184.1mV
144ps     155.1mV    105mV      198.3mV
173ps     174.7mV    147.8mV    207mV
216ps     183.5mV    170.2mV    210.3mV
425ps     186mV      177.6mV    211mV
[Falling Waveform]
R_fixture   = 50
V_fixture   = 0.6
V_fixture_min = 0.57
V_fixture_max = 0.65
|   Time   V(typ)   V(min)   V(max)
0s        600mV      570mV      650mV
73ps      599.8mV    570.2mV    646mV
80ps      599.6mV    569.7mV    622.9mV
94ps      593mV      568.7mV    549.2mV
113ps     531.9mV    568.4mV    476.5mV
128ps     478.3mV    549.1mV    444.5mV
156ps     417.9mV    469.1mV    416.3mV
189ps     389.5mV    405.2mV    405.6mV
232ps     378.4mV    372.6mV    402.1mV
425ps     374.9mV    359mV      401.3mV
[Rising Waveform]
R_fixture   = 50
V_fixture   = 0.6
V_fixture_min = 0.57
V_fixture_max = 0.65
|   Time   V(typ)   V(min)   V(max)
0s        374.9mV    358.8mV    401.2mV
59ps      374.2mV    357mV      408.5mV
67ps      380.3mV    356.5mV    432.5mV
81ps      416.8mV    364.6mV    507.5mV
99ps      484.2mV    411.2mV    574.3mV
119ps     536.2mV    470.6mV    612.7mV
143ps     569.7mV    516.9mV    633.8mV
173ps     588mV      546.9mV    644.2mV
216ps     596.7mV    563mV      648.7mV
425ps     600mV      570mV      650mV
[Falling Waveform]
R_fixture = 50
V_fixture = 0.0
|   Time   V(typ)   V(min)   V(max)
0s        186mV      177.7mV    211.1mV
63ps      187.5mV    178.6mV    206.6mV
72ps      185.8mV    179.3mV    183.4mV
83ps      173.5mV    178.6mV    123.5mV
100ps     115.3mV    165mV      61.19mV
117ps     60.54mV    123.7mV    30.81mV
139ps     26.32mV    63.24mV    12.71mV
164ps     10.35mV    26.52mV    4.722mV
202ps     2.618mV    7.113mV    1.091mV
425ps     138.1uV    151.3uV    62.45uV
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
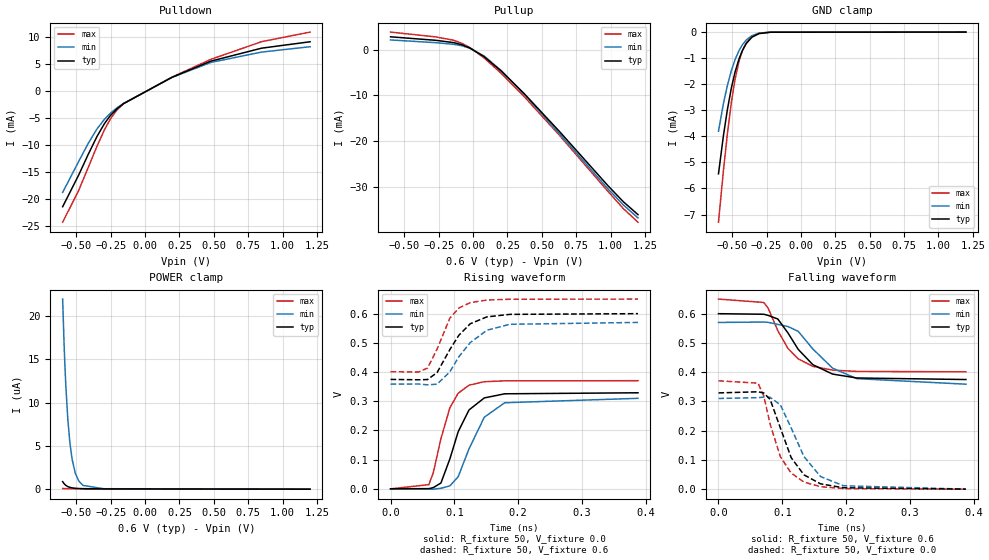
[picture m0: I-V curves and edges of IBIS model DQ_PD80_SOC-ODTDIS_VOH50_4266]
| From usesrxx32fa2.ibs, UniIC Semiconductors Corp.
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| DQ_PD80_SOC-ODTDIS_VOH50_4266
| (80 Ohm Pulldown, SOC ODT disabled setting, VOH=VDDQ*0.50 cal. point, 3200-4266Mbps)
[Model]   DQ_PD80_SOC-ODTDIS_VOH50_4266
Model_type   I/O
Vinl = 90.000mV
Vinh = 210.000mV
Vmeas = 150.000mV
Vref = 0.0mV
Cref = 0.0pF
|   typ   min   max
|C_comp   0.834pF   0.784pF   0.884pF
C_comp_pullup   0.4170pF   0.3920pF   0.4420pF
C_comp_pulldown   0.4170pF   0.3920pF   0.4420pF
| Note: C_comp changes when the ODT circuit is enabled.
[Model Spec]
| Input threshold voltage corners
Vinl   0.0900V   0.0825V   0.1025V
Vinh   0.2100V   0.2025V   0.2225V
| Measurement voltage corners
Vmeas   0.1500V   0.1425V   0.1625V
| Timing spec test load voltage corners
Vref   0.0000V   0.0000V   0.0000V
| Dynamic Overshoot Parameters from LPDDR4_0P6 Specification
D_overshoot_ampl_h   0.30   NA   NA
D_overshoot_ampl_l   0.30   NA   NA
D_overshoot_area_h   0.1n   NA   NA
D_overshoot_area_l   0.1n   NA   NA
[Voltage Range]   0.6000V   0.5700V   0.6500V
[Pullup Reference]   0.6000V   0.5700V   0.6500V
| Junction Temperature (Ambient temp is 35C typ 95C min -40C max)
[Temperature Range]   50.0   110.0   -40.0
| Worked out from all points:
|   slope of the pulldown table from 0 to 0.09 V, typ, clamps not added: 75.3 ohm
|   slope of the pullup table from 0 to 0.09 V, typ, clamps not added: 50.8 ohm
|   GND clamp passes 1 mA (typ) near -0.45 V on its own axis
|   rising waveform, R_fixture 50, V_fixture 0.0: 20-80 % time 32.7ps typ, 37.6ps min, 27.7ps max; typ from 0 V to 0.329 V
|   falling waveform, R_fixture 50, V_fixture 0.6: 20-80 % time 48.6ps typ, 58.3ps min, 40.1ps max; typ from 0.6 V to 0.375 V
|   rising waveform, R_fixture 50, V_fixture 0.6: 20-80 % time 39.8ps typ, 45.9ps min, 29.7ps max; typ from 0.375 V to 0.6 V
|   falling waveform, R_fixture 50, V_fixture 0.0: 20-80 % time 36.9ps typ, 43.5ps min, 33ps max; typ from 0.329 V to 0 V
[Pulldown]
|   Voltage   I(typ)   I(min)   I(max)
-600mV    -21.37mA   -18.73mA   -24.22mA
-484.8mV  -15.6mA    -13.09mA   -18.44mA
-412.8mV  -11.65mA   -9.626mA   -14.07mA
-349.8mV  -8.393mA   -7.01mA    -10.18mA
-295.8mV  -6.034mA   -5.234mA   -7.174mA
-252.6mV  -4.547mA   -4.12mA    -5.177mA
-205.8mV  -3.323mA   -3.152mA   -3.542mA
-157.2mV  -2.358mA   -2.307mA   -2.377mA
195.6mV   2.507mA    2.478mA    2.534mA
478.2mV   5.482mA    5.247mA    5.812mA
847.2mV   7.873mA    7.151mA    9.072mA
1.2V      9.057mA    8.141mA    10.84mA
[GND Clamp]
|   Voltage   I(typ)   I(min)   I(max)
-600mV    -5.439mA   -3.802mA   -7.294mA
-564mV    -3.973mA   -2.741mA   -5.311mA
-535.2mV  -2.973mA   -2.046mA   -3.902mA
-506.4mV  -2.147mA   -1.48mA    -2.701mA
-479.4mV  -1.532mA   -1.058mA   -1.809mA
-450.6mV  -1.029mA   -709.7uA   -1.119mA
-425.4mV  -700uA     -481.2uA   -708uA
-398.4mV  -442.3uA   -304uA     -412uA
-357mV    -196.8uA   -136.6uA   -159.8uA
-304.8mV  -58.63uA   -42.65uA   -38.93uA
-222mV    -5.877uA   -5.145uA   -2.507uA
1.2V      0A         0A         0A
[Pullup]
|   Voltage   I(typ)   I(min)   I(max)
-600mV    2.791mA    2.105mA    3.822mA
-270.6mV  2.022mA    1.507mA    2.767mA
-142.8mV  1.529mA    1.157mA    2.05mA
-79.8mV   1.042mA    819.2uA    1.355mA
-22.2mV   338.2uA    277.3uA    426uA
82.2mV    -1.598mA   -1.442mA   -1.864mA
206.4mV   -4.744mA   -4.615mA   -5.242mA
370.2mV   -9.577mA   -9.707mA   -10.22mA
625.8mV   -17.81mA   -18.31mA   -18.64mA
984mV     -29.84mA   -30.53mA   -31.08mA
1.094V    -33.28mA   -33.97mA   -34.78mA
1.2V      -36.08mA   -36.8mA    -37.73mA
[POWER Clamp]
|   Voltage   I(typ)   I(min)   I(max)
-600mV    870.5nA    21.98uA    72.65nA
-589.2mV  630.2nA    16.59uA    68.66nA
-583.8mV  538.6nA    14.38uA    66.97nA
-576.6mV  439.3nA    11.88uA    64.76nA
-562.2mV  298.7nA    8.049uA    60.55nA
-547.8mV  210.7nA    5.443uA    56.57nA
-531.6mV  149.3nA    3.493uA    52.36nA
-508.2mV  100.6nA    1.854uA    46.73nA
-483mV    74.39nA    946.2nA    41.23nA
-452.4mV  58.3nA     436.7nA    35.27nA
-303mV    31.59nA    51.63nA    15.37nA
1.2V      0A         0A         0A
[Ramp]
|   typ   min   max
| 20% - 80%
dV/dt_r   197.32m/32.74p   185.96m/37.61p   222.25m/27.68p
dV/dt_f   135.05m/48.58p   126.59m/58.26p   149.26m/40.12p
| 25% - 75%
|dV/dt_r   164.43m/25.91p   154.97m/29.78p   185.21m/21.87p
|dV/dt_f   112.54m/38.38p   105.49m/45.98p   124.38m/31.67p
R_load = 50
[Rising Waveform]
R_fixture = 50
V_fixture = 0.0
|   Time   V(typ)   V(min)   V(max)
0s        233.6uV    215.7uV    109.5uV
60ps      848.3uV    -752.8uV   14.52mV
67ps      4.316mV    -944.1uV   55.44mV
79ps      20.15mV    2.063mV    172.2mV
93ps      102.7mV    10.38mV    277.9mV
106ps     195.6mV    41.43mV    327.5mV
123ps     270.3mV    137.1mV    355.1mV
147ps     311.5mV    245.5mV    367mV
179ps     325.6mV    295mV      370mV
388ps     329.1mV    310.1mV    370.5mV
[Falling Waveform]
R_fixture   = 50
V_fixture   = 0.6
V_fixture_min = 0.57
V_fixture_max = 0.65
|   Time   V(typ)   V(min)   V(max)
0s        600mV      570mV      650mV
71ps      598.1mV    571.5mV    638.3mV
78ps      594.1mV    570.3mV    618.3mV
93ps      581.9mV    563.5mV    542mV
109ps     534mV      556.1mV    481mV
125ps     478.1mV    539.6mV    445.6mV
148ps     425.6mV    479.3mV    420mV
179ps     393.5mV    413.7mV    407.1mV
217ps     380.2mV    377.9mV    402.7mV
388ps     374.9mV    359mV      401.3mV
[Rising Waveform]
R_fixture   = 50
V_fixture   = 0.6
V_fixture_min = 0.57
V_fixture_max = 0.65
|   Time   V(typ)   V(min)   V(max)
0s        374.9mV    358.8mV    401.2mV
44ps      373.6mV    359.1mV    400.3mV
58ps      374.4mV    356.4mV    413.8mV
73ps      398.5mV    358.5mV    478.7mV
93ps      477.2mV    401mV      584.8mV
107ps     525.8mV    452.2mV    619.1mV
125ps     565.5mV    501.1mV    637.8mV
151ps     589mV      543.3mV    646.6mV
187ps     597.6mV    563.6mV    649.4mV
388ps     600mV      570mV      650mV
[Falling Waveform]
R_fixture = 50
V_fixture = 0.0
|   Time   V(typ)   V(min)   V(max)
0s        329.2mV    310.2mV    370.6mV
62ps      333mV      312.8mV    362.5mV
71ps      328.9mV    315mV      319mV
81ps      306.9mV    313.9mV    222.3mV
97ps      209.7mV    288.4mV    111.2mV
114ps     107.8mV    209.5mV    55.11mV
134ps     49.11mV    111.7mV    24.4mV
160ps     18.36mV    43.23mV    8.607mV
196ps     4.934mV    11.77mV    2.13mV
388ps     286.1uV    299.2uV    137.2uV
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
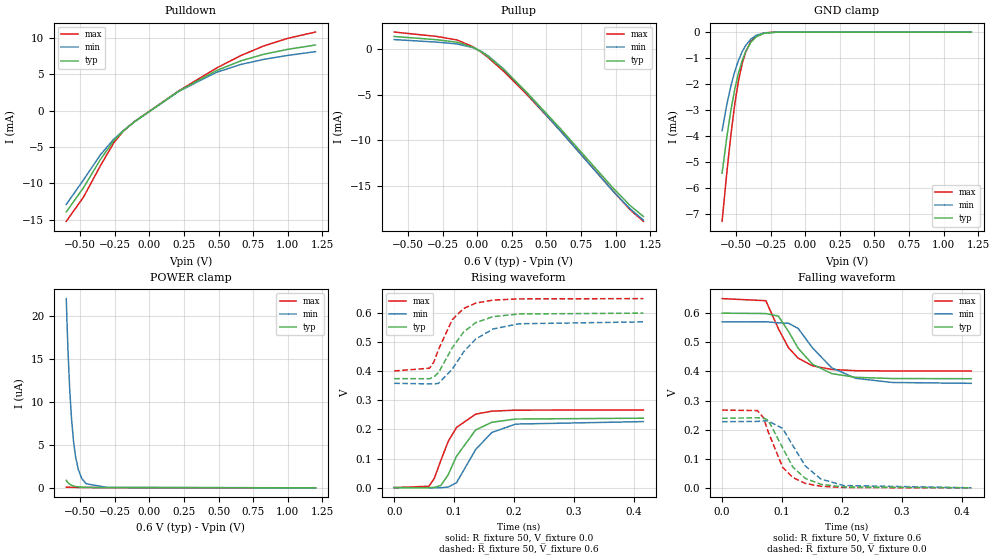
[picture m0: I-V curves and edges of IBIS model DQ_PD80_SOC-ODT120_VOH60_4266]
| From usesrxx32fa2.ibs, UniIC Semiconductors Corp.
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| DQ_PD80_SOC-ODT120_VOH60_4266
| (80 Ohm Pulldown, 120 Ohm System ODT Setting, VOH=VDDQ*0.60, 3200-4266Mbps)
[Model]   DQ_PD80_SOC-ODT120_VOH60_4266
Model_type   I/O
Vinl = 120.000mV
Vinh = 240.000mV
Vmeas = 180.000mV
Vref = 0.0mV
Cref = 0.0pF
Rref = 120.000Ohm
|   typ   min   max
|C_comp   0.834pF   0.784pF   0.884pF
C_comp_pullup   0.4170pF   0.3920pF   0.4420pF
C_comp_pulldown   0.4170pF   0.3920pF   0.4420pF
| Note: C_comp changes when the ODT circuit is enabled.
[Model Spec]
| Input threshold voltage corners
Vinl   0.1200V   0.1110V   0.1350V
Vinh   0.2400V   0.2310V   0.2550V
| Measurement voltage corners
Vmeas   0.1800V   0.1710V   0.1950V
| Timing spec test load voltage corners
Vref   0.0000V   0.0000V   0.0000V
| Dynamic Overshoot Parameters from LPDDR4_0P6 Specification
D_overshoot_ampl_h   0.30   NA   NA
D_overshoot_ampl_l   0.30   NA   NA
D_overshoot_area_h   0.1n   NA   NA
D_overshoot_area_l   0.1n   NA   NA
[Voltage Range]   0.6000V   0.5700V   0.6500V
[Pullup Reference]   0.6000V   0.5700V   0.6500V
| Junction Temperature (Ambient temp is 35C typ 95C min -40C max)
[Temperature Range]   50.0   110.0   -40.0
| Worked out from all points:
|   slope of the pulldown table from 0 to 0.09 V, typ, clamps not added: 75.5 ohm
|   slope of the pullup table from 0 to 0.09 V, typ, clamps not added: 98.7 ohm
|   GND clamp passes 1 mA (typ) near -0.45 V on its own axis
|   rising waveform, R_fixture 50, V_fixture 0.0: 20-80 % time 40.8ps typ, 44.3ps min, 35.6ps max; typ from 0 V to 0.239 V
|   falling waveform, R_fixture 50, V_fixture 0.6: 20-80 % time 47.8ps typ, 56.8ps min, 39.9ps max; typ from 0.6 V to 0.375 V
|   rising waveform, R_fixture 50, V_fixture 0.6: 20-80 % time 45.6ps typ, 52.2ps min, 36.4ps max; typ from 0.375 V to 0.6 V
|   falling waveform, R_fixture 50, V_fixture 0.0: 20-80 % time 37.8ps typ, 45.1ps min, 34ps max; typ from 0.239 V to 0 V
[Pulldown]
|   Voltage   I(typ)   I(min)   I(max)
-600mV    -13.91mA   -12.88mA   -15.2mA
-475.8mV  -10.59mA   -9.506mA   -11.88mA
-353.4mV  -6.703mA   -6.048mA   -7.554mA
-258mV    -4.132mA   -3.929mA   -4.43mA
-187.8mV  -2.757mA   -2.718mA   -2.786mA
-106.8mV  -1.497mA   -1.499mA   -1.47mA
213.6mV   2.722mA    2.687mA    2.758mA
485.4mV   5.545mA    5.302mA    5.888mA
661.8mV   6.883mA    6.387mA    7.609mA
827.4mV   7.784mA    7.081mA    8.935mA
1V        8.46mA     7.628mA    9.975mA
1.2V      9.057mA    8.141mA    10.84mA
[GND Clamp]
|   Voltage   I(typ)   I(min)   I(max)
-600mV    -5.44mA    -3.802mA   -7.294mA
-565.8mV  -4.041mA   -2.789mA   -5.405mA
-535.2mV  -2.974mA   -2.046mA   -3.902mA
-508.2mV  -2.193mA   -1.512mA   -2.769mA
-483mV    -1.605mA   -1.109mA   -1.915mA
-454.2mV  -1.085mA   -747.8uA   -1.192mA
-429mV    -741.5uA   -509.2uA   -757uA
-393mV    -401.3uA   -275.4uA   -367.1uA
-357mV    -197uA     -136.3uA   -159.9uA
-297.6mV  -49.18uA   -35.88uA   -31.66uA
-204mV    -3.333uA   -3.118uA   -1.232uA
1.2V      0A         0A         0A
[Pullup]
|   Voltage   I(typ)   I(min)   I(max)
-600mV    1.424mA    1.081mA    1.912mA
-292.2mV  1.067mA    802.4uA    1.427mA
-146.4mV  795.8uA    607.5uA    1.042mA
-29.4mV   224.7uA    186.2uA    279.1uA
24.6mV    -217.2uA   -187.4uA   -258.1uA
78.6mV    -779.4uA   -706.8uA   -891.3uA
192mV     -2.234mA   -2.171mA   -2.426mA
350.4mV   -4.606mA   -4.669mA   -4.828mA
602.4mV   -8.747mA   -9.001mA   -8.977mA
978.6mV   -15.21mA   -15.56mA   -15.54mA
1.103V    -17.16mA   -17.52mA   -17.63mA
1.2V      -18.38mA   -18.78mA   -18.91mA
[POWER Clamp]
|   Voltage   I(typ)   I(min)   I(max)
-600mV    870.6nA    21.99uA    72.65nA
-594.6mV  739.5nA    19.11uA    70.4nA
-587.4mV  597.7nA    15.82uA    68.09nA
-574.8mV  417.7nA    11.31uA    64.22nA
-562.2mV  298.6nA    8.057uA    60.54nA
-547.8mV  210.4nA    5.445uA    56.57nA
-533.4mV  154.6nA    3.675uA    52.81nA
-513.6mV  109.1nA    2.142uA    47.98nA
-488.4mV  78.67nA    1.089uA    42.35nA
-456mV    59.73nA    475.4nA    35.93nA
-308.4mV  32.15nA    53.09nA    15.87nA
1.2V      0A         0A         0A
[Ramp]
|   typ   min   max
| 20% - 80%
dV/dt_r   143.19m/40.77p   136.22m/44.33p   160.26m/35.59p
dV/dt_f   135.04m/47.80p   126.62m/56.78p   149.25m/39.92p
| 25% - 75%
|dV/dt_r   119.33m/32.30p   113.52m/35.11p   133.55m/28.15p
|dV/dt_f   112.54m/37.83p   105.52m/45.01p   124.38m/31.57p
R_load = 50
[Rising Waveform]
R_fixture = 50
V_fixture = 0.0
|   Time   V(typ)   V(min)   V(max)
0s        109.8uV    97.18uV    53.03uV
58ps      -142uV     -147.7uV   4.836mV
67ps      1.058mV    -624.2uV   32.35mV
78ps      7.576mV    -155.9uV   94.26mV
90ps      43.87mV    1.778mV    158.2mV
104ps     108mV      16.88mV    207mV
136ps     198.4mV    131.2mV    252.8mV
163ps     224.8mV    189.8mV    263mV
203ps     236mV      218.6mV    266.5mV
416ps     238.8mV    227.1mV    267.2mV
[Falling Waveform]
R_fixture   = 50
V_fixture   = 0.6
V_fixture_min = 0.57
V_fixture_max = 0.65
|   Time   V(typ)   V(min)   V(max)
0s        600mV      570mV      650mV
73ps      598.7mV    570.5mV    642.8mV
94ps      589.7mV    566.8mV    546.4mV
111ps     536.6mV    565.2mV    480.7mV
127ps     479.3mV    547.5mV    445.4mV
151ps     424.4mV    480.4mV    419.1mV
183ps     392.4mV    412.3mV    406.6mV
223ps     379.6mV    376.3mV    402.4mV
284ps     375.5mV    361.9mV    401.4mV
416ps     374.9mV    359mV      401.3mV
[Rising Waveform]
R_fixture   = 50
V_fixture   = 0.6
V_fixture_min = 0.57
V_fixture_max = 0.65
|   Time   V(typ)   V(min)   V(max)
0s        374.9mV    358.8mV    401.2mV
59ps      374.5mV    356.8mV    410.7mV
66ps      380.3mV    356.3mV    431.1mV
74ps      395.7mV    358.7mV    475.1mV
97ps      481.3mV    407.5mV    577.9mV
116ps     535.2mV    467.3mV    616.1mV
136ps     567.3mV    510.7mV    634.5mV
165ps     587.9mV    545.5mV    644.9mV
208ps     597.1mV    563.5mV    649mV
416ps     600mV      570mV      650mV
[Falling Waveform]
R_fixture = 50
V_fixture = 0.0
|   Time   V(typ)   V(min)   V(max)
0s        238.8mV    227.2mV    267.2mV
59ps      240.9mV    228.2mV    265.4mV
69ps      239.6mV    229.7mV    240.5mV
77ps      232.3mV    229.8mV    192mV
101ps     137.6mV    204mV      70.8mV
118ps     71.62mV    145.5mV    35.54mV
139ps     32.11mV    75.02mV    15.24mV
165ps     12.12mV    30.04mV    5.39mV
203ps     3.098mV    7.974mV    1.247mV
416ps     185.1uV    199.7uV    82.36uV
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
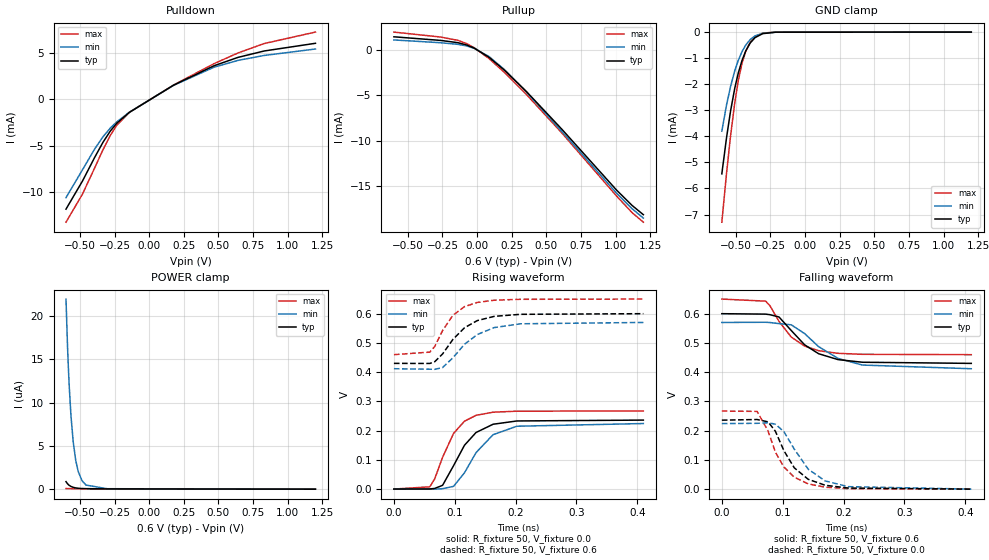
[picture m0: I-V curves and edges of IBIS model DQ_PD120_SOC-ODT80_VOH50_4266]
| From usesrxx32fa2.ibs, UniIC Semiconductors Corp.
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| DQ_PD120_SOC-ODT80_VOH50_4266
| (120 Ohm Pulldown, 80 Ohm System ODT Setting, VOH=VDDQ*0.50, 3200-4266Mbps)
[Model]   DQ_PD120_SOC-ODT80_VOH50_4266
Model_type   I/O
Vinl = 90.000mV
Vinh = 210.000mV
Vmeas = 150.000mV
Vref = 0.0mV
Cref = 0.0pF
Rref = 80.000Ohm
|   typ   min   max
|C_comp   0.834pF   0.784pF   0.884pF
C_comp_pullup   0.4170pF   0.3920pF   0.4420pF
C_comp_pulldown   0.4170pF   0.3920pF   0.4420pF
| Note: C_comp changes when the ODT circuit is enabled.
[Model Spec]
| Input threshold voltage corners
Vinl   0.0900V   0.0825V   0.1025V
Vinh   0.2100V   0.2025V   0.2225V
| Measurement voltage corners
Vmeas   0.1500V   0.1425V   0.1625V
| Timing spec test load voltage corners
Vref   0.0000V   0.0000V   0.0000V
| Dynamic Overshoot Parameters from LPDDR4_0P6 Specification
D_overshoot_ampl_h   0.30   NA   NA
D_overshoot_ampl_l   0.30   NA   NA
D_overshoot_area_h   0.1n   NA   NA
D_overshoot_area_l   0.1n   NA   NA
[Voltage Range]   0.6000V   0.5700V   0.6500V
[Pullup Reference]   0.6000V   0.5700V   0.6500V
| Junction Temperature (Ambient temp is 35C typ 95C min -40C max)
[Temperature Range]   50.0   110.0   -40.0
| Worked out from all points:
|   slope of the pulldown table from 0 to 0.09 V, typ, clamps not added: 111 ohm
|   slope of the pullup table from 0 to 0.09 V, typ, clamps not added: 101 ohm
|   GND clamp passes 1 mA (typ) near -0.45 V on its own axis
|   rising waveform, R_fixture 50, V_fixture 0.0: 20-80 % time 41.5ps typ, 45.5ps min, 35.8ps max; typ from 0 V to 0.236 V
|   falling waveform, R_fixture 50, V_fixture 0.6: 20-80 % time 53ps typ, 62.5ps min, 44.7ps max; typ from 0.6 V to 0.43 V
|   rising waveform, R_fixture 50, V_fixture 0.6: 20-80 % time 45.8ps typ, 51ps min, 36.8ps max; typ from 0.43 V to 0.6 V
|   falling waveform, R_fixture 50, V_fixture 0.0: 20-80 % time 41.6ps typ, 47.6ps min, 38ps max; typ from 0.236 V to 0 V
[Pulldown]
|   Voltage   I(typ)   I(min)   I(max)
-600mV    -11.85mA   -10.61mA   -13.26mA
-481.2mV  -8.819mA   -7.605mA   -10.23mA
-393mV    -6.26mA    -5.349mA   -7.394mA
-333.6mV  -4.642mA   -4.044mA   -5.449mA
-279.6mV  -3.405mA   -3.086mA   -3.876mA
-234.6mV  -2.59mA    -2.44mA    -2.81mA
-142.8mV  -1.401mA   -1.387mA   -1.395mA
175.8mV   1.532mA    1.515mA    1.549mA
469.2mV   3.641mA    3.482mA    3.868mA
642mV     4.541mA    4.215mA    5.019mA
831mV     5.231mA    4.748mA    6.035mA
1.2V      6.059mA    5.442mA    7.269mA
[GND Clamp]
|   Voltage   I(typ)   I(min)   I(max)
-600mV    -5.439mA   -3.802mA   -7.294mA
-565.8mV  -4.041mA   -2.789mA   -5.405mA
-537mV    -3.03mA    -2.085mA   -3.984mA
-506.4mV  -2.146mA   -1.48mA    -2.701mA
-481.2mV  -1.569mA   -1.083mA   -1.86mA
-454.2mV  -1.086mA   -747.9uA   -1.192mA
-427.2mV  -720.3uA   -495uA     -731.8uA
-394.8mV  -415uA     -283.9uA   -381.8uA
-360.6mV  -213.3uA   -146.4uA   -174.5uA
-304.8mV  -58.9uA    -42.75uA   -38.92uA
-211.2mV  -4.181uA   -3.798uA   -1.644uA
1.2V      0A         0A         0A
[Pullup]
|   Voltage   I(typ)   I(min)   I(max)
-600mV    1.396mA    1.053mA    1.912mA
-263.4mV  1.001mA    746.2uA    1.37mA
-137.4mV  749.3uA    568.6uA    1.004mA
-76.2mV   503.4uA    397.1uA    653.8uA
-20.4mV   156.2uA    128.4uA    197uA
87.6mV    -863.2uA   -782.8uA   -1.004mA
199.2mV   -2.285mA   -2.217mA   -2.53mA
352.2mV   -4.538mA   -4.59mA    -4.856mA
609.6mV   -8.692mA   -8.938mA   -9.099mA
1.007V    -15.4mA    -15.74mA   -16.05mA
1.119V    -17.08mA   -17.44mA   -17.87mA
1.2V      -18.09mA   -18.46mA   -18.91mA
[POWER Clamp]
|   Voltage   I(typ)   I(min)   I(max)
-600mV    870.7nA    21.99uA    72.65nA
-589.2mV  630.1nA    16.59uA    68.66nA
-583.8mV  538.5nA    14.38uA    66.96nA
-576.6mV  439nA      11.88uA    64.76nA
-564mV    313.1nA    8.457uA    61.06nA
-547.8mV  210.4nA    5.442uA    56.57nA
-529.8mV  144.1nA    3.327uA    51.91nA
-511.8mV  105.9nA    2.042uA    47.56nA
-484.8mV  75.69nA    991.3nA    41.6nA
-456mV    59.75nA    475.7nA    35.93nA
-303mV    31.59nA    51.69nA    15.37nA
1.2V      0A         0A         0A
[Ramp]
|   typ   min   max
| 20% - 80%
dV/dt_r   141.51m/41.55p   134.45m/45.45p   160.26m/35.75p
dV/dt_f   101.96m/53.03p   94.91m/62.45p   114.04m/44.74p
| 25% - 75%
|dV/dt_r   117.92m/32.91p   112.04m/35.99p   133.55m/28.24p
|dV/dt_f   84.97m/42.00p   79.09m/49.47p   95.03m/35.34p
R_load = 50
[Rising Waveform]
R_fixture = 50
V_fixture = 0.0
|   Time   V(typ)   V(min)   V(max)
0s        132.7uV    120.2uV    64.4uV
59ps      437.5uV    -216.7uV   7.737mV
67ps      2.17mV     -281.9uV   34.83mV
80ps      12.91mV    1.381mV    108.7mV
98ps      79.98mV    9.313mV    190.5mV
116ps     150mV      55.8mV     232.3mV
135ps     193.6mV    124.8mV    252.3mV
163ps     221.8mV    186.1mV    263mV
202ps     233mV      215mV      266.5mV
410ps     236mV      224.2mV    267.2mV
[Falling Waveform]
R_fixture   = 50
V_fixture   = 0.6
V_fixture_min = 0.57
V_fixture_max = 0.65
|   Time   V(typ)   V(min)   V(max)
0s        600mV      570mV      650mV
72ps      598.5mV    570.7mV    642.9mV
79ps      596.6mV    569.8mV    627.4mV
94ps      588.7mV    566.1mV    573.5mV
114ps     542.7mV    562mV      520.3mV
136ps     493.7mV    532.1mV    489.3mV
159ps     463.2mV    487.6mV    473.5mV
191ps     443mV      447mV      464.5mV
231ps     434mV      424.4mV    461.1mV
410ps     430.1mV    411.8mV    459.9mV
[Rising Waveform]
R_fixture   = 50
V_fixture   = 0.6
V_fixture_min = 0.57
V_fixture_max = 0.65
|   Time   V(typ)   V(min)   V(max)
0s        430mV      411.7mV    459.9mV
59ps      429.7mV    410.1mV    468.5mV
67ps      435.6mV    409.6mV    487.5mV
80ps      462.3mV    415.7mV    542.3mV
97ps      512.1mV    449.2mV    594.6mV
116ps     551.8mV    495.3mV    624mV
137ps     576.4mV    528.7mV    638.5mV
165ps     590.9mV    552.5mV    646.1mV
208ps     597.8mV    565.4mV    649.2mV
410ps     600mV      570mV      650mV
[Falling Waveform]
R_fixture = 50
V_fixture = 0.0
|   Time   V(typ)   V(min)   V(max)
0s        236mV      224.3mV    267.2mV
58ps      238.2mV    225.2mV    266mV
76ps      230.2mV    227.2mV    198.8mV
88ps      198.1mV    222.2mV    126.6mV
102ps     131.8mV    196.9mV    75.82mV
119ps     73.2mV     137.3mV    41.18mV
142ps     33.78mV    68.35mV    18.13mV
170ps     13.32mV    28.14mV    6.737mV
208ps     3.934mV    8.66mV     1.837mV
410ps     219.3uV    231.7uV    97.36uV
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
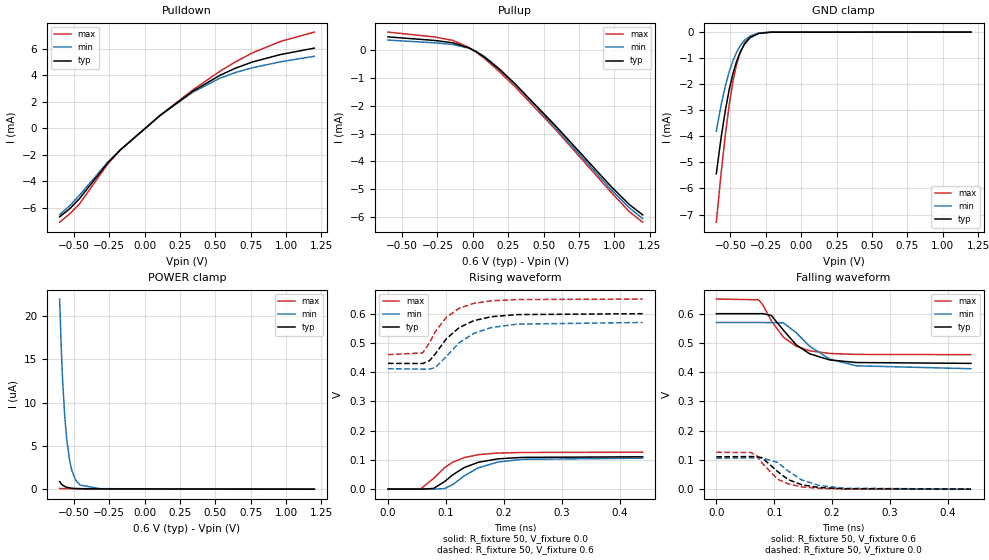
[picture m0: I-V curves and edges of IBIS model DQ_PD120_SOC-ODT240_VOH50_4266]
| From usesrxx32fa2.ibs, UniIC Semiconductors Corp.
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| DQ_PD120_SOC-ODT240_VOH50_4266
| (120 Ohm Pulldown, 240 Ohm System ODT Setting, VOH=VDDQ*0.50, 3200-4266Mbps)
[Model]   DQ_PD120_SOC-ODT240_VOH50_4266
Model_type   I/O
Vinl = 90.000mV
Vinh = 210.000mV
Vmeas = 150.000mV
Vref = 0.0mV
Cref = 0.0pF
Rref = 240.000Ohm
|   typ   min   max
|C_comp   0.834pF   0.784pF   0.884pF
C_comp_pullup   0.4170pF   0.3920pF   0.4420pF
C_comp_pulldown   0.4170pF   0.3920pF   0.4420pF
| Note: C_comp changes when the ODT circuit is enabled.
[Model Spec]
| Input threshold voltage corners
Vinl   0.0900V   0.0825V   0.1025V
Vinh   0.2100V   0.2025V   0.2225V
| Measurement voltage corners
Vmeas   0.1500V   0.1425V   0.1625V
| Timing spec test load voltage corners
Vref   0.0000V   0.0000V   0.0000V
| Dynamic Overshoot Parameters from LPDDR4_0P6 Specification
D_overshoot_ampl_h   0.30   NA   NA
D_overshoot_ampl_l   0.30   NA   NA
D_overshoot_area_h   0.1n   NA   NA
D_overshoot_area_l   0.1n   NA   NA
[Voltage Range]   0.6000V   0.5700V   0.6500V
[Pullup Reference]   0.6000V   0.5700V   0.6500V
| Junction Temperature (Ambient temp is 35C typ 95C min -40C max)
[Temperature Range]   50.0   110.0   -40.0
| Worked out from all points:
|   slope of the pulldown table from 0 to 0.09 V, typ, clamps not added: 112 ohm
|   slope of the pullup table from 0 to 0.09 V, typ, clamps not added: 306 ohm
|   GND clamp passes 1 mA (typ) near -0.45 V on its own axis
|   rising waveform, R_fixture 50, V_fixture 0.0: 20-80 % time 54.7ps typ, 57.4ps min, 47.9ps max; typ from 0 V to 0.11 V
|   falling waveform, R_fixture 50, V_fixture 0.6: 20-80 % time 52.3ps typ, 61.2ps min, 44.3ps max; typ from 0.6 V to 0.43 V
|   rising waveform, R_fixture 50, V_fixture 0.6: 20-80 % time 53ps typ, 58.1ps min, 45.8ps max; typ from 0.43 V to 0.6 V
|   falling waveform, R_fixture 50, V_fixture 0.0: 20-80 % time 42.9ps typ, 49.8ps min, 39.3ps max; typ from 0.111 V to 0 V
[Pulldown]
|   Voltage   I(typ)   I(min)   I(max)
-600mV    -6.68mA    -6.511mA   -7.084mA
-528mV    -6.062mA   -5.838mA   -6.45mA
-461.4mV  -5.326mA   -5.068mA   -5.725mA
-263.4mV  -2.651mA   -2.596mA   -2.741mA
-169.8mV  -1.616mA   -1.618mA   -1.604mA
111mV     986.5uA    980.1uA    989.7uA
339.6mV   2.792mA    2.719mA    2.893mA
532.2mV   4mA        3.784mA    4.309mA
643.8mV   4.549mA    4.221mA    5.03mA
762.6mV   5.013mA    4.578mA    5.701mA
960.6mV   5.574mA    5.025mA    6.564mA
1.2V      6.059mA    5.442mA    7.269mA
[GND Clamp]
|   Voltage   I(typ)   I(min)   I(max)
-600mV    -5.439mA   -3.802mA   -7.294mA
-565.8mV  -4.041mA   -2.789mA   -5.405mA
-535.2mV  -2.973mA   -2.047mA   -3.902mA
-508.2mV  -2.193mA   -1.512mA   -2.769mA
-481.2mV  -1.57mA    -1.083mA   -1.86mA
-457.8mV  -1.144mA   -787.6uA   -1.267mA
-432.6mV  -785.8uA   -539.1uA   -809.2uA
-400.2mV  -457.7uA   -313.3uA   -428.4uA
-360.6mV  -212.3uA   -146.3uA   -174.6uA
-299.4mV  -51.37uA   -37.48uA   -33.45uA
-211.2mV  -4.167uA   -3.815uA   -1.644uA
1.2V      0A         0A         0A
[Pullup]
|   Voltage   I(typ)   I(min)   I(max)
-600mV    465uA      350.7uA    636.6uA
-270.6mV  336.9uA    251.1uA    460.8uA
-141mV    252.9uA    191.6uA    338.7uA
-27.6mV   68.93uA    56.42uA    87.09uA
22.8mV    -64.73uA   -55.34uA   -78.88uA
80.4mV    -258.4uA   -232.9uA   -301.9uA
184.8mV   -688.8uA   -663.5uA   -766.6uA
300mV     -1.233mA   -1.234mA   -1.333mA
580.8mV   -2.704mA   -2.776mA   -2.837mA
978.6mV   -4.91mA    -5.02mA    -5.117mA
1.105V    -5.543mA   -5.66mA    -5.799mA
1.2V      -5.919mA   -6.049mA   -6.179mA
[POWER Clamp]
|   Voltage   I(typ)   I(min)   I(max)
-600mV    870.6nA    21.99uA    72.65nA
-589.2mV  630.2nA    16.59uA    68.66nA
-582mV    511.7nA    13.71uA    66.41nA
-576.6mV  439.3nA    11.87uA    64.76nA
-564mV    313.1nA    8.456uA    61.06nA
-549.6mV  219.2nA    5.717uA    57.05nA
-529.8mV  144.4nA    3.338uA    51.9nA
-513.6mV  109nA      2.144uA    47.98nA
-486.6mV  77.28nA    1.04uA     41.97nA
-456mV    59.86nA    475.7nA    35.93nA
-313.8mV  32.75nA    54.78nA    16.39nA
1.2V      0A         0A         0A
[Ramp]
|   typ   min   max
| 20% - 80%
dV/dt_r   66.27m/54.67p   63.57m/57.37p   75.63m/47.90p
dV/dt_f   101.97m/52.32p   94.94m/61.22p   114.04m/44.26p
| 25% - 75%
|dV/dt_r   55.23m/43.36p   52.98m/45.45p   63.03m/37.90p
|dV/dt_f   84.97m/41.51p   79.11m/48.62p   95.04m/35.04p
R_load = 50
[Rising Waveform]
R_fixture = 50
V_fixture = 0.0
|   Time   V(typ)   V(min)   V(max)
0s        33.96uV    24.08uV    19.79uV
57ps      -62.13uV   113.2uV    1.435mV
79ps      2.283mV    -273.4uV   36.71mV
98ps      26.02mV    1.793mV    73.68mV
112ps     48.9mV     15.68mV    91.97mV
132ps     73.87mV    45.66mV    107.9mV
156ps     91.66mV    72.73mV    117.7mV
190ps     103.4mV    92.47mV    123.3mV
232ps     108.4mV    101.7mV    125.3mV
440ps     110.5mV    106mV      126.1mV
[Falling Waveform]
R_fixture   = 50
V_fixture   = 0.6
V_fixture_min = 0.57
V_fixture_max = 0.65
|   Time   V(typ)   V(min)   V(max)
0s        600mV      570mV      650mV
73ps      600mV      570mV      647.6mV
80ps      600.2mV    569.7mV    631.2mV
95ps      594mV      569.5mV    575.8mV
116ps     543.3mV    568.5mV    519.4mV
138ps     493.6mV    535.2mV    488.8mV
161ps     463mV      488.9mV    473.1mV
196ps     441.8mV    444.8mV    464mV
242ps     433mV      421.8mV    460.8mV
440ps     430.1mV    411.8mV    459.9mV
[Rising Waveform]
R_fixture   = 50
V_fixture   = 0.6
V_fixture_min = 0.57
V_fixture_max = 0.65
|   Time   V(typ)   V(min)   V(max)
0s        430mV      411.7mV    459.9mV
60ps      429.6mV    410.3mV    465.9mV
72ps      439.5mV    410.4mV    501.4mV
82ps      463mV      416mV      539.3mV
101ps     514.5mV    454.1mV    588mV
123ps     552.4mV    500.3mV    618.4mV
148ps     576mV      532.4mV    635.2mV
178ps     589.5mV    552.3mV    644mV
223ps     596.9mV    564.3mV    648.4mV
440ps     600mV      570mV      650mV
[Falling Waveform]
R_fixture = 50
V_fixture = 0.0
|   Time   V(typ)   V(min)   V(max)
0s        110.6mV    106.1mV    126.1mV
60ps      111.5mV    106.6mV    125.2mV
70ps      111mV      107.1mV    113.9mV
79ps      107.6mV    106.9mV    89.3mV
106ps     60.11mV    91.29mV    34.04mV
124ps     32.96mV    62.34mV    18.03mV
147ps     15.43mV    31.92mV    7.971mV
178ps     5.618mV    12.41mV    2.695mV
222ps     1.396mV    3.302mV    606.3uV
440ps     102.4uV    112.9uV    36.23uV
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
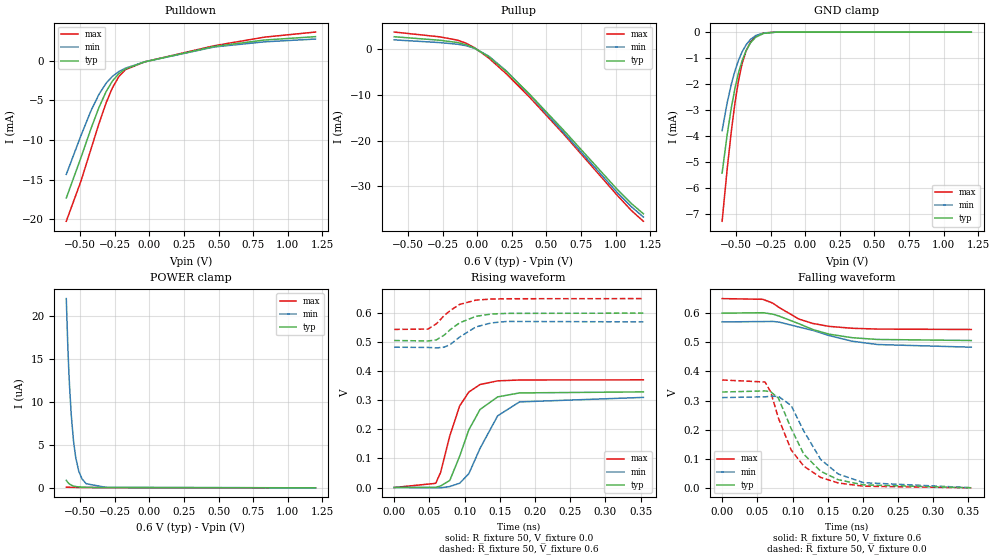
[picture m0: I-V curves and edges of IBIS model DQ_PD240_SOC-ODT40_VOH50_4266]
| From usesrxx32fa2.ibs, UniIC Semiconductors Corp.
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| DQ_PD240_SOC-ODT40_VOH50_4266
| (240 Ohm Pulldown, 40 Ohm System ODT Setting, VOH=VDDQ*0.50, 3200-4266Mbps)
[Model]   DQ_PD240_SOC-ODT40_VOH50_4266
Model_type   I/O
Vinl = 90.000mV
Vinh = 210.000mV
Vmeas = 150.000mV
Vref = 0.0mV
Cref = 0.0pF
Rref = 40.000Ohm
|   typ   min   max
|C_comp   0.834pF   0.784pF   0.884pF
C_comp_pullup   0.4170pF   0.3920pF   0.4420pF
C_comp_pulldown   0.4170pF   0.3920pF   0.4420pF
| Note: C_comp changes when the ODT circuit is enabled.
[Model Spec]
| Input threshold voltage corners
Vinl   0.0900V   0.0825V   0.1025V
Vinh   0.2100V   0.2025V   0.2225V
| Measurement voltage corners
Vmeas   0.1500V   0.1425V   0.1625V
| Timing spec test load voltage corners
Vref   0.0000V   0.0000V   0.0000V
| Dynamic Overshoot Parameters from LPDDR4_0P6 Specification
D_overshoot_ampl_h   0.30   NA   NA
D_overshoot_ampl_l   0.30   NA   NA
D_overshoot_area_h   0.1n   NA   NA
D_overshoot_area_l   0.1n   NA   NA
[Voltage Range]   0.6000V   0.5700V   0.6500V
[Pullup Reference]   0.6000V   0.5700V   0.6500V
| Junction Temperature (Ambient temp is 35C typ 95C min -40C max)
[Temperature Range]   50.0   110.0   -40.0
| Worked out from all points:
|   slope of the pulldown table from 0 to 0.09 V, typ, clamps not added: 227 ohm
|   slope of the pullup table from 0 to 0.09 V, typ, clamps not added: 50.8 ohm
|   GND clamp passes 1 mA (typ) near -0.45 V on its own axis
|   rising waveform, R_fixture 50, V_fixture 0.0: 20-80 % time 33.1ps typ, 38.3ps min, 27.8ps max; typ from 0 V to 0.329 V
|   falling waveform, R_fixture 50, V_fixture 0.6: 20-80 % time 65.4ps typ, 84.2ps min, 52.1ps max; typ from 0.6 V to 0.506 V
|   rising waveform, R_fixture 50, V_fixture 0.6: 20-80 % time 34.9ps typ, 31.8ps min, 31.3ps max; typ from 0.506 V to 0.6 V
|   falling waveform, R_fixture 50, V_fixture 0.0: 20-80 % time 45.9ps typ, 49.5ps min, 42.7ps max; typ from 0.329 V to 0.001 V
[Pulldown]
|   Voltage   I(typ)   I(min)   I(max)
-600mV    -17.3mA    -14.33mA   -20.23mA
-493.8mV  -12.21mA   -9.436mA   -15.16mA
-421.8mV  -8.581mA   -6.325mA   -11.16mA
-364.2mV  -5.913mA   -4.262mA   -7.947mA
-312mV    -3.899mA   -2.849mA   -5.32mA
-267mV    -2.585mA   -1.992mA   -3.445mA
-220.2mV  -1.653mA   -1.384mA   -2.024mA
-173.4mV  -1.066mA   -965.4uA   -1.161mA
-33mV     -163.7uA   -162.3uA   -154.5uA
469.2mV   1.775mA    1.709mA    1.866mA
831mV     2.58mA     2.354mA    2.943mA
1.2V      3.005mA    2.705mA    3.586mA
[GND Clamp]
|   Voltage   I(typ)   I(min)   I(max)
-600mV    -5.439mA   -3.802mA   -7.294mA
-564mV    -3.973mA   -2.741mA   -5.311mA
-533.4mV  -2.918mA   -2.006mA   -3.82mA
-506.4mV  -2.148mA   -1.481mA   -2.701mA
-481.2mV  -1.568mA   -1.083mA   -1.86mA
-456mV    -1.112mA   -767.2uA   -1.23mA
-427.2mV  -721.3uA   -495.1uA   -731.3uA
-394.8mV  -415uA     -284uA     -381.8uA
-357mV    -196.9uA   -135.8uA   -159.9uA
-299.4mV  -51.36uA   -37.53uA   -33.47uA
-207.6mV  -3.725uA   -3.451uA   -1.425uA
1.2V      0A         0A         0A
[Pullup]
|   Voltage   I(typ)   I(min)   I(max)
-600mV    2.791mA    2.105mA    3.822mA
-270.6mV  2.022mA    1.507mA    2.767mA
-141mV    1.518mA    1.15mA     2.035mA
-79.8mV   1.042mA    819.6uA    1.355mA
-20.4mV   311.6uA    255.3uA    392.8uA
84mV      -1.637mA   -1.481mA   -1.909mA
210mV     -4.845mA   -4.719mA   -5.346mA
372mV     -9.632mA   -9.765mA   -10.28mA
627.6mV   -17.87mA   -18.37mA   -18.7mA
1.009V    -30.66mA   -31.34mA   -31.95mA
1.114V    -33.85mA   -34.55mA   -35.39mA
1.2V      -36.08mA   -36.8mA    -37.73mA
[POWER Clamp]
|   Voltage   I(typ)   I(min)   I(max)
-600mV    870.6nA    21.99uA    72.65nA
-589.2mV  630.2nA    16.59uA    68.66nA
-582mV    511.8nA    13.71uA    66.41nA
-576.6mV  440.1nA    11.88uA    64.76nA
-564mV    312.9nA    8.461uA    61.06nA
-547.8mV  210.8nA    5.442uA    56.57nA
-531.6mV  149.5nA    3.503uA    52.35nA
-510mV    103.2nA    1.945uA    47.14nA
-486.6mV  77.15nA    1.04uA     41.97nA
-456mV    59.7nA     475.8nA    35.93nA
-312mV    32.56nA    54.2nA     16.21nA
1.2V      0A         0A         0A
[Ramp]
|   typ   min   max
| 20% - 80%
dV/dt_r   197.25m/33.12p   185.89m/38.25p   222.23m/27.81p
dV/dt_f   56.38m/65.43p   52.06m/84.18p   63.59m/52.14p
| 25% - 75%
|dV/dt_r   164.38m/26.18p   154.91m/30.24p   185.19m/22.04p
|dV/dt_f   46.98m/51.34p   43.38m/64.98p   52.99m/41.11p
R_load = 50
[Rising Waveform]
R_fixture = 50
V_fixture = 0.0
|   Time   V(typ)   V(min)   V(max)
0s        339uV      323.3uV    157.3uV
59ps      1.028mV    -909.1uV   14.43mV
66ps      5.385mV    -1.029mV   52.64mV
79ps      24.6mV     3.496mV    178.1mV
93ps      107.7mV    14.84mV    280.7mV
106ps     198.5mV    47.43mV    328.7mV
122ps     268.7mV    135mV      354.5mV
147ps     311.9mV    246.8mV    367mV
178ps     325.5mV    294.6mV    370mV
354ps     329.1mV    310.1mV    370.5mV
[Falling Waveform]
R_fixture   = 50
V_fixture   = 0.6
V_fixture_min = 0.57
V_fixture_max = 0.65
|   Time   V(typ)   V(min)   V(max)
0s        600mV      570mV      650mV
58ps      601.5mV    571.2mV    647.6mV
72ps      596.7mV    571.6mV    634.3mV
81ps      589.9mV    569.4mV    619.5mV
109ps     563.9mV    552.3mV    579.8mV
129ps     543.7mV    540.9mV    564.6mV
152ps     527.9mV    523.1mV    554.7mV
185ps     515.7mV    503.6mV    548.1mV
221ps     509.7mV    492.3mV    545.4mV
354ps     506.1mV    483.2mV    544mV
[Rising Waveform]
R_fixture   = 50
V_fixture   = 0.6
V_fixture_min = 0.57
V_fixture_max = 0.65
|   Time   V(typ)   V(min)   V(max)
0s        505.9mV    482.8mV    544mV
48ps      504.2mV    482mV      545.2mV
60ps      508.1mV    480.3mV    563.5mV
71ps      524.4mV    482.8mV    591.6mV
80ps      544mV      492.8mV    609.6mV
93ps      566.8mV    517.7mV    630mV
116ps     589mV      552.5mV    644.8mV
138ps     596.9mV    566.4mV    648.5mV
160ps     599.2mV    571.4mV    649.5mV
354ps     600mV      570mV      650mV
[Falling Waveform]
R_fixture = 50
V_fixture = 0.0
|   Time   V(typ)   V(min)   V(max)
0s        329.2mV    310.2mV    370.6mV
61ps      333.1mV    312.7mV    363.6mV
69ps      330.1mV    314.9mV    330mV
80ps      308.3mV    314.3mV    239.1mV
98ps      204.4mV    283.2mV    130.7mV
116ps     115.9mV    195.4mV    74.77mV
140ps     57.14mV    97.72mV    36.06mV
165ps     28.08mV    47.72mV    16.94mV
201ps     10.31mV    17.87mV    5.83mV
354ps     517uV      697.4uV    244.9uV
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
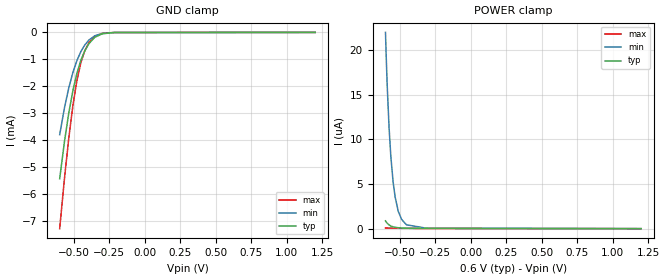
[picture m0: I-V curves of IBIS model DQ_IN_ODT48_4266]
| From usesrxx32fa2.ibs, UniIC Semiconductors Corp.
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| DQ_IN_ODT48_4266 (with 48ohm ODT, 3200-4266Mbps)
[Model]   DQ_IN_ODT48_4266
Model_type   Input
Vinl = 90.000mV
Vinh = 210.000mV
|   typ   min   max
|C_comp   0.802pF   0.757pF   0.855pF
C_comp_power_clamp   0.4010pF   0.3785pF   0.4275pF
C_comp_gnd_clamp   0.4010pF   0.3785pF   0.4275pF
| Note: C_comp changes when the ODT circuit is enabled.
[Model Spec]
| Input threshold voltage corners
Vinl   0.0900V   0.0825V   0.1025V
Vinh   0.2100V   0.2025V   0.2225V
| Dynamic Overshoot Parameters from LPDDR4_0P6 Specification
D_overshoot_ampl_h   0.30   NA   NA
D_overshoot_ampl_l   0.30   NA   NA
D_overshoot_area_h   0.1n   NA   NA
D_overshoot_area_l   0.1n   NA   NA
[Voltage Range]   0.6000V   0.5700V   0.6500V
[POWER Clamp Reference]   0.6000V   0.5700V   0.6500V
| Junction Temperature (Ambient temp is 35C typ 95C min -40C max)
[Temperature Range]   50.0   110.0   -40.0
[Add Submodel]
| Submodel Name   Mode
48ohm_ODT_4266   Non-Driving
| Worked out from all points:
|   GND clamp passes 1 mA (typ) near -0.45 V on its own axis
[GND Clamp]
|   Voltage   I(typ)   I(min)   I(max)
-600mV    -5.439mA   -3.802mA   -7.294mA
-565.8mV  -4.041mA   -2.789mA   -5.405mA
-535.2mV  -2.974mA   -2.047mA   -3.902mA
-506.4mV  -2.152mA   -1.482mA   -2.703mA
-479.4mV  -1.537mA   -1.059mA   -1.808mA
-450.6mV  -1.033mA   -711.1uA   -1.12mA
-423.6mV  -695.4uA   -471.2uA   -684.1uA
-394.8mV  -424.3uA   -288.5uA   -382uA
-353.4mV  -182.8uA   -128.8uA   -147.5uA
-299.4mV  -51.65uA   -38.43uA   -34.14uA
-216.6mV  -5.513uA   -4.976uA   -2.103uA
1.2V      0A         0A         0A
[POWER Clamp]
|   Voltage   I(typ)   I(min)   I(max)
-600mV    870.4nA    21.99uA    72.65nA
-594.6mV  739.5nA    19.12uA    70.4nA
-587.4mV  597.7nA    15.83uA    68.09nA
-574.8mV  418.2nA    11.33uA    64.22nA
-562.2mV  298.4nA    8.054uA    60.55nA
-546mV    202.1nA    5.191uA    56.09nA
-531.6mV  149nA      3.513uA    52.36nA
-510mV    104.3nA    1.943uA    47.15nA
-486.6mV  77.21nA    1.041uA    41.99nA
-452.4mV  58.41nA    435.2nA    35.27nA
-313.8mV  32.8nA     54.25nA    16.41nA
1.2V      0A         0A         0A
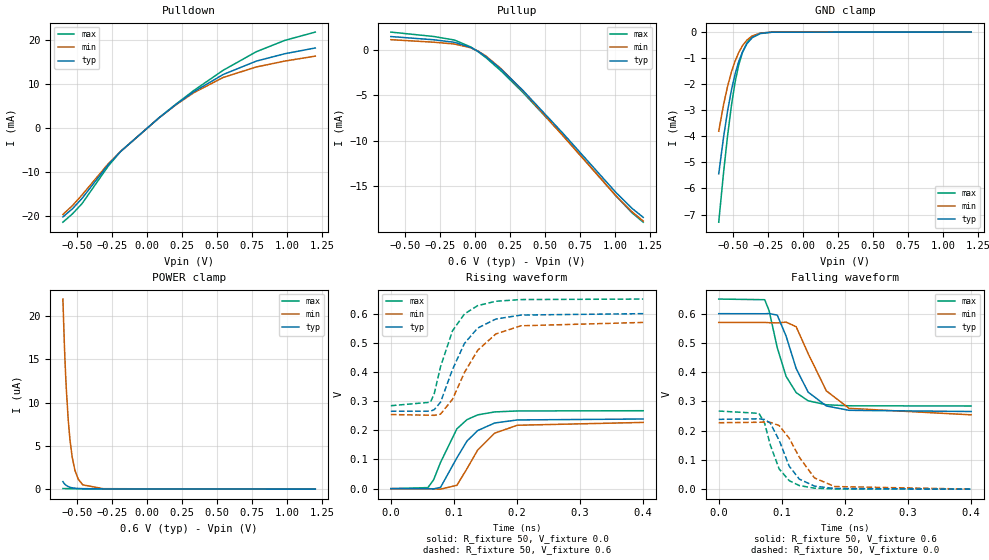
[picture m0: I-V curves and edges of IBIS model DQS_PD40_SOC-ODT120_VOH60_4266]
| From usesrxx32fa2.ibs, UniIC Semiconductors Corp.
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| DQS_PD40_SOC-ODT120_VOH60_4266
| (40 Ohm Pulldown, 120 Ohm System ODT Setting, VOH=VDDQ*0.60, 3200-4266Mbps)
[Model]   DQS_PD40_SOC-ODT120_VOH60_4266
Model_type   I/O
Vinl = 120.000mV
Vinh = 240.000mV
Vmeas = 180.000mV
Vref = 0.0mV
Cref = 0.0pF
Rref = 120.000Ohm
|   typ   min   max
|C_comp   0.849pF   0.799pF   0.899pF
C_comp_pullup   0.4245pF   0.3995pF   0.4495pF
C_comp_pulldown   0.4245pF   0.3995pF   0.4495pF
| Note: C_comp changes when the ODT circuit is enabled.
[Model Spec]
| Input threshold voltage corners
Vinl   0.1200V   0.1110V   0.1350V
Vinh   0.2400V   0.2310V   0.2550V
| Measurement voltage corners
Vmeas   0.1800V   0.1710V   0.1950V
| Timing spec test load voltage corners
Vref   0.0000V   0.0000V   0.0000V
| Dynamic Overshoot Parameters from LPDDR4_0P6 Specification
D_overshoot_ampl_h   0.30   NA   NA
D_overshoot_ampl_l   0.30   NA   NA
D_overshoot_area_h   0.1n   NA   NA
D_overshoot_area_l   0.1n   NA   NA
[Voltage Range]   0.6000V   0.5700V   0.6500V
[Pullup Reference]   0.6000V   0.5700V   0.6500V
| Junction Temperature (Ambient temp is 35C typ 95C min -40C max)
[Temperature Range]   50.0   110.0   -40.0
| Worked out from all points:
|   slope of the pulldown table from 0 to 0.09 V, typ, clamps not added: 37.5 ohm
|   slope of the pullup table from 0 to 0.09 V, typ, clamps not added: 98.8 ohm
|   GND clamp passes 1 mA (typ) near -0.45 V on its own axis
|   rising waveform, R_fixture 50, V_fixture 0.0: 20-80 % time 40.5ps typ, 43.8ps min, 35.6ps max; typ from 0 V to 0.239 V
|   falling waveform, R_fixture 50, V_fixture 0.6: 20-80 % time 36.2ps typ, 44.1ps min, 30ps max; typ from 0.6 V to 0.265 V
|   rising waveform, R_fixture 50, V_fixture 0.6: 20-80 % time 43.4ps typ, 51.4ps min, 35.3ps max; typ from 0.265 V to 0.6 V
|   falling waveform, R_fixture 50, V_fixture 0.0: 20-80 % time 29.9ps typ, 38.7ps min, 26.1ps max; typ from 0.239 V to 0 V
[Pulldown]
|   Voltage   I(typ)   I(min)   I(max)
-600mV    -20.24mA   -19.69mA   -21.44mA
-531.6mV  -18.38mA   -17.67mA   -19.54mA
-463.2mV  -16.02mA   -15.23mA   -17.21mA
-277.8mV  -8.41mA    -8.204mA   -8.74mA
-187.8mV  -5.353mA   -5.348mA   -5.342mA
85.8mV    2.286mA    2.274mA    2.29mA
208.2mV   5.35mA     5.275mA    5.436mA
334.2mV   8.21mA     7.998mA    8.502mA
543mV     12.12mA    11.45mA    13.08mA
778.8mV   15.16mA    13.83mA    17.29mA
982.2mV   16.84mA    15.17mA    19.87mA
1.2V      18.15mA    16.3mA     21.76mA
[GND Clamp]
|   Voltage   I(typ)   I(min)   I(max)
-600mV    -5.44mA    -3.803mA   -7.294mA
-565.8mV  -4.041mA   -2.789mA   -5.405mA
-537mV    -3.03mA    -2.085mA   -3.984mA
-508.2mV  -2.193mA   -1.512mA   -2.769mA
-483mV    -1.605mA   -1.109mA   -1.913mA
-457.8mV  -1.142mA   -787.2uA   -1.268mA
-430.8mV  -762.7uA   -524.7uA   -782.5uA
-398.4mV  -442.1uA   -303.3uA   -412.3uA
-360.6mV  -212.5uA   -146.5uA   -174.5uA
-303mV    -56.14uA   -41.15uA   -36.98uA
-222mV    -5.817uA   -5.175uA   -2.515uA
1.2V      0A         0A         0A
[Pullup]
|   Voltage   I(typ)   I(min)   I(max)
-600mV    1.424mA    1.081mA    1.912mA
-294mV    1.07mA     804.2uA    1.43mA
-146.4mV  795.9uA    607.5uA    1.042mA
-31.2mV   238.8uA    196.5uA    295.1uA
22.8mV    -200.2uA   -172.5uA   -238.5uA
78.6mV    -779.8uA   -706.9uA   -891.3uA
184.8mV   -2.134mA   -2.067mA   -2.323mA
341.4mV   -4.464mA   -4.52mA    -4.686mA
624mV     -9.113mA   -9.379mA   -9.345mA
1.007V    -15.68mA   -16.04mA   -16.05mA
1.119V    -17.38mA   -17.75mA   -17.87mA
1.2V      -18.38mA   -18.78mA   -18.91mA
[POWER Clamp]
|   Voltage   I(typ)   I(min)   I(max)
-600mV    870.6nA    21.99uA    72.65nA
-589.2mV  630.1nA    16.59uA    68.66nA
-583.8mV  538.4nA    14.39uA    66.96nA
-576.6mV  439.4nA    11.87uA    64.76nA
-562.2mV  298.4nA    8.051uA    60.55nA
-549.6mV  219.5nA    5.718uA    57.05nA
-533.4mV  154.5nA    3.675uA    52.81nA
-513.6mV  108.8nA    2.145uA    47.98nA
-490.2mV  80.05nA    1.143uA    42.74nA
-457.8mV  60.46nA    497.2nA    36.26nA
-312mV    32.54nA    54.26nA    16.21nA
1.2V      0A         0A         0A
[Ramp]
|   typ   min   max
| 20% - 80%
dV/dt_r   143.22m/40.52p   136.25m/43.84p   160.28m/35.63p
dV/dt_f   200.71m/36.19p   189.48m/44.07p   219.38m/30.00p
| 25% - 75%
|dV/dt_r   119.35m/32.10p   113.54m/34.74p   133.56m/28.14p
|dV/dt_f   167.26m/28.61p   157.90m/34.91p   182.82m/23.63p
R_load = 50
[Rising Waveform]
R_fixture = 50
V_fixture = 0.0
|   Time   V(typ)   V(min)   V(max)
0s        60.54uV    43uV       33.21uV
59ps      -373.8uV   137.5uV    3.629mV
68ps      -725.6uV   -686.5uV   30.43mV
79ps      4.474mV    -1.725mV   90.14mV
105ps     105.8mV    11.49mV    205.2mV
121ps     163.3mV    68.5mV     236.6mV
138ps     199.2mV    132.3mV    253mV
165ps     225.1mV    190.3mV    263.1mV
201ps     235.6mV    217.4mV    266.4mV
401ps     238.8mV    227.1mV    267.2mV
[Falling Waveform]
R_fixture   = 50
V_fixture   = 0.6
V_fixture_min = 0.57
V_fixture_max = 0.65
|   Time   V(typ)   V(min)   V(max)
0s        600mV      570mV      650mV
73ps      599.8mV    570.1mV    647.8mV
80ps      600.6mV    569.3mV    610.5mV
93ps      595.1mV    568.6mV    483.5mV
107ps     523.6mV    571.1mV    385.8mV
123ps     412.7mV    555.5mV    330.2mV
142ps     331.9mV    463.8mV    302.2mV
171ps     284.5mV    336.1mV    288.6mV
207ps     269.6mV    276.4mV    285.1mV
401ps     265.5mV    254.2mV    284.4mV
[Rising Waveform]
R_fixture   = 50
V_fixture   = 0.6
V_fixture_min = 0.57
V_fixture_max = 0.65
|   Time   V(typ)   V(min)   V(max)
0s        265.4mV    254.1mV    284.4mV
63ps      265.7mV    251.8mV    296.3mV
69ps      271mV      251.4mV    325.8mV
79ps      296.3mV    255.5mV    418mV
98ps      408.7mV    306.4mV    541.2mV
117ps     497.9mV    398.3mV    599mV
138ps     550.6mV    474.3mV    627.5mV
167ps     581.6mV    530.6mV    642.5mV
207ps     595.2mV    558.4mV    648.3mV
401ps     600mV      569.9mV    650mV
[Falling Waveform]
R_fixture = 50
V_fixture = 0.0
|   Time   V(typ)   V(min)   V(max)
0s        238.8mV    227.2mV    267.2mV
64ps      240.6mV    228.8mV    259.3mV
73ps      238.1mV    229.6mV    224.8mV
82ps      225.8mV    228.6mV    150.6mV
96ps      167.2mV    217.5mV    69.3mV
112ps     78.59mV    174.1mV    29.07mV
128ps     34.57mV    109.3mV    12.37mV
152ps     10.48mV    38.8mV     3.517mV
184ps     2.343mV    8.998mV    737.4uV
401ps     132.4uV    138.4uV    54.98uV
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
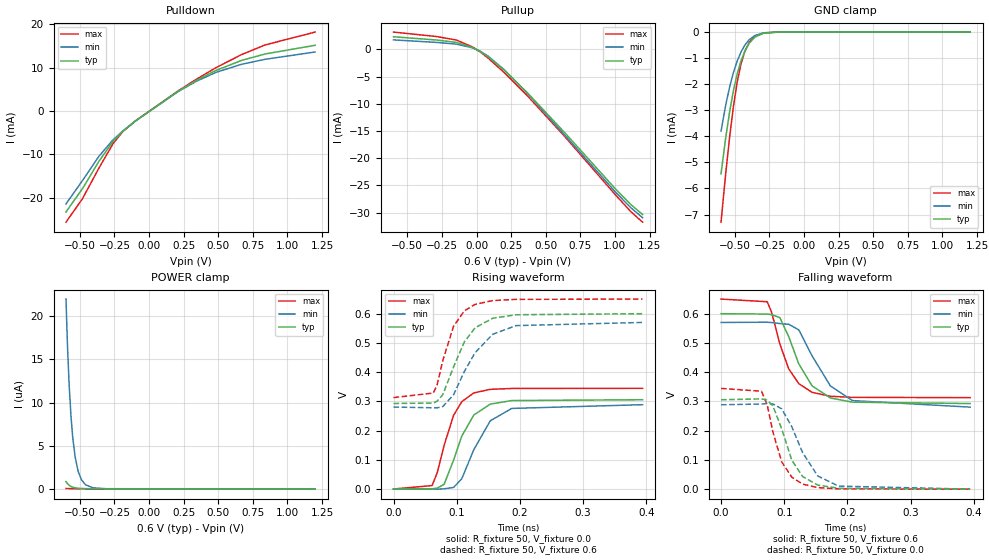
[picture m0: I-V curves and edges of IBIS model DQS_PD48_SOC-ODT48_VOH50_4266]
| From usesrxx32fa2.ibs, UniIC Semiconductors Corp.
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| DQS_PD48_SOC-ODT48_VOH50_4266
| (48 Ohm Pulldown, 48 Ohm System ODT Setting, VOH=VDDQ*0.50, 3200-4266Mbps)
[Model]   DQS_PD48_SOC-ODT48_VOH50_4266
Model_type   I/O
Vinl = 90.000mV
Vinh = 210.000mV
Vmeas = 150.000mV
Vref = 0.0mV
Cref = 0.0pF
Rref = 48.000Ohm
|   typ   min   max
|C_comp   0.849pF   0.799pF   0.899pF
C_comp_pullup   0.4245pF   0.3995pF   0.4495pF
C_comp_pulldown   0.4245pF   0.3995pF   0.4495pF
| Note: C_comp changes when the ODT circuit is enabled.
[Model Spec]
| Input threshold voltage corners
Vinl   0.0900V   0.0825V   0.1025V
Vinh   0.2100V   0.2025V   0.2225V
| Measurement voltage corners
Vmeas   0.1500V   0.1425V   0.1625V
| Timing spec test load voltage corners
Vref   0.0000V   0.0000V   0.0000V
| Dynamic Overshoot Parameters from LPDDR4_0P6 Specification
D_overshoot_ampl_h   0.30   NA   NA
D_overshoot_ampl_l   0.30   NA   NA
D_overshoot_area_h   0.1n   NA   NA
D_overshoot_area_l   0.1n   NA   NA
[Voltage Range]   0.6000V   0.5700V   0.6500V
[Pullup Reference]   0.6000V   0.5700V   0.6500V
| Junction Temperature (Ambient temp is 35C typ 95C min -40C max)
[Temperature Range]   50.0   110.0   -40.0
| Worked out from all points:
|   slope of the pulldown table from 0 to 0.09 V, typ, clamps not added: 44.5 ohm
|   slope of the pullup table from 0 to 0.09 V, typ, clamps not added: 60.5 ohm
|   GND clamp passes 1 mA (typ) near -0.45 V on its own axis
|   rising waveform, R_fixture 50, V_fixture 0.0: 20-80 % time 34.2ps typ, 39ps min, 29.6ps max; typ from 0 V to 0.306 V
|   falling waveform, R_fixture 50, V_fixture 0.6: 20-80 % time 39.4ps typ, 48ps min, 32.6ps max; typ from 0.6 V to 0.293 V
|   rising waveform, R_fixture 50, V_fixture 0.6: 20-80 % time 38.7ps typ, 48.1ps min, 29.7ps max; typ from 0.293 V to 0.6 V
|   falling waveform, R_fixture 50, V_fixture 0.0: 20-80 % time 31.4ps typ, 39.1ps min, 27.3ps max; typ from 0.306 V to 0 V
[Pulldown]
|   Voltage   I(typ)   I(min)   I(max)
-600mV    -23.34mA   -21.49mA   -25.7mA
-481.2mV  -17.97mA   -16.1mA    -20.29mA
-362.4mV  -11.67mA   -10.5mA    -13.23mA
-259.8mV  -7.016mA   -6.67mA    -7.556mA
-191.4mV  -4.761mA   -4.687mA   -4.842mA
-101.4mV  -2.403mA   -2.405mA   -2.371mA
211.8mV   4.574mA    4.506mA    4.659mA
341.4mV   7.031mA    6.836mA    7.306mA
485.4mV   9.367mA    8.919mA    10.01mA
667.2mV   11.65mA    10.76mA    12.99mA
840mV     13.16mA    11.93mA    15.25mA
1.2V      15.16mA    13.61mA    18.21mA
[GND Clamp]
|   Voltage   I(typ)   I(min)   I(max)
-600mV    -5.439mA   -3.802mA   -7.294mA
-565.8mV  -4.041mA   -2.789mA   -5.405mA
-537mV    -3.031mA   -2.086mA   -3.984mA
-510mV    -2.24mA    -1.544mA   -2.839mA
-483mV    -1.605mA   -1.109mA   -1.913mA
-456mV    -1.113mA   -767.7uA   -1.229mA
-427.2mV  -721.3uA   -494.8uA   -731.4uA
-396.6mV  -430.1uA   -293.5uA   -396.8uA
-357mV    -198.3uA   -136.9uA   -160.3uA
-294mV    -44.88uA   -33.19uA   -28.5uA
-196.8mV  -2.671uA   -2.546uA   -938.3nA
1.2V      0A         0A         0A
[Pullup]
|   Voltage   I(typ)   I(min)   I(max)
-600mV    2.327mA    1.755mA    3.187mA
-292.2mV  1.737mA    1.295mA    2.378mA
-144.6mV  1.285mA    971uA      1.725mA
-27.6mV   346.4uA    283.6uA    438.7uA
24.6mV    -353.8uA   -302.6uA   -431.1uA
84mV      -1.373mA   -1.241mA   -1.601mA
199.2mV   -3.817mA   -3.704mA   -4.227mA
368.4mV   -8.002mA   -8.115mA   -8.545mA
634.8mV   -15.23mA   -15.67mA   -15.93mA
1.009V    -25.79mA   -26.37mA   -26.88mA
1.115V    -28.52mA   -29.1mA    -29.82mA
1.2V      -30.35mA   -30.94mA   -31.76mA
[POWER Clamp]
|   Voltage   I(typ)   I(min)   I(max)
-600mV    870.5nA    21.99uA    72.65nA
-589.2mV  630.1nA    16.59uA    68.66nA
-576.6mV  440.2nA    11.88uA    64.76nA
-564mV    313.2nA    8.452uA    61.06nA
-551.4mV  229.3nA    6.008uA    57.54nA
-533.4mV  154.8nA    3.68uA     52.81nA
-511.8mV  106.1nA    2.043uA    47.56nA
-488.4mV  78.55nA    1.09uA     42.35nA
-459.6mV  61.21nA    519.6nA    36.6nA
-405.6mV  45.92nA    157.9nA    27.53nA
-310.2mV  32.36nA    53.66nA    16.04nA
1.2V      0A         0A         0A
[Ramp]
|   typ   min   max
| 20% - 80%
dV/dt_r   183.28m/34.20p   173.10m/39.04p   206.71m/29.57p
dV/dt_f   184.34m/39.44p   173.65m/48.03p   202.23m/32.62p
| 25% - 75%
|dV/dt_r   152.73m/27.06p   144.25m/30.94p   172.26m/23.33p
|dV/dt_f   153.62m/31.16p   144.71m/37.95p   168.53m/25.70p
R_load = 50
[Rising Waveform]
R_fixture = 50
V_fixture = 0.0
|   Time   V(typ)   V(min)   V(max)
0s        141.2uV    123.8uV    68.85uV
61ps      814.2uV    -270.8uV   11.84mV
69ps      2.862mV    -451.4uV   54.65mV
80ps      16mV       732.3uV    149mV
95ps      98.49mV    5.528mV    252.1mV
108ps     181.2mV    35.22mV    298.9mV
127ps     253.3mV    134.6mV    328.9mV
153ps     290.5mV    233.3mV    341.1mV
187ps     302.7mV    275.8mV    344.1mV
394ps     305.6mV    288.6mV    344.6mV
[Falling Waveform]
R_fixture   = 50
V_fixture   = 0.6
V_fixture_min = 0.57
V_fixture_max = 0.65
|   Time   V(typ)   V(min)   V(max)
0s        600mV      570mV      650mV
73ps      598.7mV    570.8mV    640.8mV
80ps      596.9mV    569.7mV    605.2mV
93ps      586.7mV    566.3mV    496.6mV
107ps     521.8mV    563.8mV    411.8mV
123ps     428.4mV    544.8mV    360.8mV
144ps     353.3mV    455.9mV    331.1mV
173ps     311.8mV    353mV      317.7mV
208ps     297.5mV    302.9mV    313.9mV
394ps     292.8mV    280.6mV    313mV
[Rising Waveform]
R_fixture   = 50
V_fixture   = 0.6
V_fixture_min = 0.57
V_fixture_max = 0.65
|   Time   V(typ)   V(min)   V(max)
0s        292.7mV    280.5mV    312.9mV
63ps      294.2mV    278mV      328.5mV
69ps      300.6mV    277.9mV    356.1mV
78ps      323mV      282.2mV    439.7mV
95ps      417.9mV    322.5mV    557mV
112ps     503.1mV    401.9mV    609.4mV
129ps     551.6mV    466.4mV    631.8mV
157ps     584.4mV    529.7mV    644.9mV
194ps     596.3mV    559.2mV    649mV
394ps     600mV      570mV      650mV
[Falling Waveform]
R_fixture = 50
V_fixture = 0.0
|   Time   V(typ)   V(min)   V(max)
0s        305.7mV    288.7mV    344.6mV
64ps      308.7mV    291.1mV    334.9mV
73ps      304.5mV    292.7mV    289.1mV
82ps      285.6mV    291.5mV    195.8mV
96ps      205.7mV    274.7mV    93.33mV
112ps     98.97mV    213.3mV    41.07mV
129ps     43.33mV    125.3mV    17.47mV
153ps     14.04mV    45.03mV    5.363mV
186ps     3.263mV    10.52mV    1.145mV
394ps     198.4uV    202.6uV    87.61uV
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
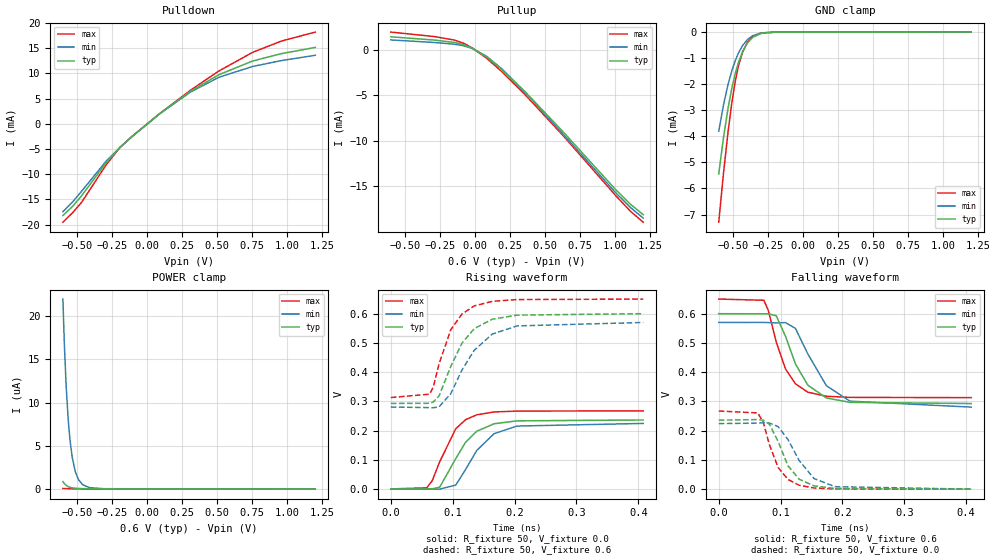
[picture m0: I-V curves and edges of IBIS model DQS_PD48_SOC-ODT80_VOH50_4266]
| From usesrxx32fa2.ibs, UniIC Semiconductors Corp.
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| DQS_PD48_SOC-ODT80_VOH50_4266
| (48 Ohm Pulldown, 80 Ohm System ODT Setting, VOH=VDDQ*0.50, 3200-4266Mbps)
[Model]   DQS_PD48_SOC-ODT80_VOH50_4266
Model_type   I/O
Vinl = 90.000mV
Vinh = 210.000mV
Vmeas = 150.000mV
Vref = 0.0mV
Cref = 0.0pF
Rref = 80.000Ohm
|   typ   min   max
|C_comp   0.849pF   0.799pF   0.899pF
C_comp_pullup   0.4245pF   0.3995pF   0.4495pF
C_comp_pulldown   0.4245pF   0.3995pF   0.4495pF
| Note: C_comp changes when the ODT circuit is enabled.
[Model Spec]
| Input threshold voltage corners
Vinl   0.0900V   0.0825V   0.1025V
Vinh   0.2100V   0.2025V   0.2225V
| Measurement voltage corners
Vmeas   0.1500V   0.1425V   0.1625V
| Timing spec test load voltage corners
Vref   0.0000V   0.0000V   0.0000V
| Dynamic Overshoot Parameters from LPDDR4_0P6 Specification
D_overshoot_ampl_h   0.30   NA   NA
D_overshoot_ampl_l   0.30   NA   NA
D_overshoot_area_h   0.1n   NA   NA
D_overshoot_area_l   0.1n   NA   NA
[Voltage Range]   0.6000V   0.5700V   0.6500V
[Pullup Reference]   0.6000V   0.5700V   0.6500V
| Junction Temperature (Ambient temp is 35C typ 95C min -40C max)
[Temperature Range]   50.0   110.0   -40.0
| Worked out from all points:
|   slope of the pulldown table from 0 to 0.09 V, typ, clamps not added: 44.5 ohm
|   slope of the pullup table from 0 to 0.09 V, typ, clamps not added: 101 ohm
|   GND clamp passes 1 mA (typ) near -0.45 V on its own axis
|   rising waveform, R_fixture 50, V_fixture 0.0: 20-80 % time 41.1ps typ, 44.7ps min, 35.7ps max; typ from 0 V to 0.236 V
|   falling waveform, R_fixture 50, V_fixture 0.6: 20-80 % time 39.3ps typ, 47.5ps min, 32.6ps max; typ from 0.6 V to 0.293 V
|   rising waveform, R_fixture 50, V_fixture 0.6: 20-80 % time 44.1ps typ, 52ps min, 35.4ps max; typ from 0.293 V to 0.6 V
|   falling waveform, R_fixture 50, V_fixture 0.0: 20-80 % time 31.8ps typ, 39.9ps min, 28.1ps max; typ from 0.236 V to 0 V
[Pulldown]
|   Voltage   I(typ)   I(min)   I(max)
-600mV    -18.19mA   -17.43mA   -19.51mA
-529.8mV  -16.33mA   -15.46mA   -17.61mA
-466.8mV  -14.28mA   -13.37mA   -15.57mA
-288.6mV  -7.568mA   -7.289mA   -8.011mA
-193.2mV  -4.681mA   -4.658mA   -4.705mA
-110.4mV  -2.596mA   -2.604mA   -2.564mA
87.6mV    1.964mA    1.953mA    1.971mA
310.8mV   6.479mA    6.321mA    6.697mA
512.4mV   9.753mA    9.245mA    10.49mA
751.8mV   12.46mA    11.38mA    14.17mA
957mV     13.93mA    12.55mA    16.42mA
1.2V      15.16mA    13.61mA    18.21mA
[GND Clamp]
|   Voltage   I(typ)   I(min)   I(max)
-600mV    -5.439mA   -3.802mA   -7.294mA
-565.8mV  -4.041mA   -2.789mA   -5.405mA
-533.4mV  -2.916mA   -2.006mA   -3.82mA
-506.4mV  -2.147mA   -1.48mA    -2.701mA
-479.4mV  -1.532mA   -1.058mA   -1.808mA
-457.8mV  -1.142mA   -787.4uA   -1.267mA
-429mV    -742.9uA   -509.7uA   -756uA
-394.8mV  -415uA     -283.5uA   -381.5uA
-357mV    -197.5uA   -136.2uA   -159.9uA
-295.8mV  -47.02uA   -34.5uA    -29.97uA
-196.8mV  -2.666uA   -2.577uA   -935nA
1.2V      0A         0A         0A
[Pullup]
|   Voltage   I(typ)   I(min)   I(max)
-600mV    1.396mA    1.053mA    1.912mA
-294mV    1.044mA    778.6uA    1.43mA
-146.4mV  775.3uA    586.1uA    1.042mA
-81.6mV   530.9uA    417.2uA    691.4uA
-22.2mV   169.5uA    139.1uA    213.6uA
84mV      -822.5uA   -743.9uA   -958.9uA
193.8mV   -2.211mA   -2.14mA    -2.452mA
355.8mV   -4.594mA   -4.649mA   -4.913mA
631.2mV   -9.053mA   -9.311mA   -9.468mA
1.007V    -15.4mA    -15.74mA   -16.05mA
1.112V    -16.98mA   -17.34mA   -17.76mA
1.2V      -18.09mA   -18.46mA   -18.91mA
[POWER Clamp]
|   Voltage   I(typ)   I(min)   I(max)
-600mV    870.6nA    21.99uA    72.65nA
-589.2mV  630.2nA    16.59uA    68.66nA
-576.6mV  439.5nA    11.87uA    64.76nA
-562.2mV  298.6nA    8.053uA    60.55nA
-549.6mV  219.1nA    5.726uA    57.05nA
-533.4mV  154.6nA    3.676uA    52.81nA
-511.8mV  106nA      2.039uA    47.55nA
-488.4mV  78.66nA    1.089uA    42.36nA
-459.6mV  61.33nA    519.6nA    36.6nA
-411mV    47.01nA    174.9nA    28.34nA
-308.4mV  32.16nA    53.12nA    15.87nA
1.2V      0A         0A         0A
[Ramp]
|   typ   min   max
| 20% - 80%
dV/dt_r   141.54m/41.13p   134.49m/44.72p   160.27m/35.72p
dV/dt_f   184.34m/39.28p   173.66m/47.55p   202.23m/32.56p
| 25% - 75%
|dV/dt_r   117.95m/32.60p   112.07m/35.46p   133.56m/28.20p
|dV/dt_f   153.62m/31.01p   144.72m/37.66p   168.52m/25.70p
R_load = 50
[Rising Waveform]
R_fixture = 50
V_fixture = 0.0
|   Time   V(typ)   V(min)   V(max)
0s        73.09uV    55.73uV    39.23uV
58ps      -13.11uV   176.7uV    3.548mV
67ps      125.4uV    -352.4uV   28.22mV
79ps      5.798mV    -850.5uV   92.77mV
105ps     103.8mV    13.17mV    206.2mV
121ps     160.3mV    67.01mV    237.1mV
139ps     197.6mV    131.9mV    253.8mV
167ps     223.1mV    189.2mV    263.5mV
204ps     233.1mV    215.2mV    266.5mV
408ps     236mV      224.2mV    267.2mV
[Falling Waveform]
R_fixture   = 50
V_fixture   = 0.6
V_fixture_min = 0.57
V_fixture_max = 0.65
|   Time   V(typ)   V(min)   V(max)
0s        600mV      570mV      650mV
73ps      599.6mV    570.2mV    645.9mV
80ps      599.8mV    569.5mV    611.9mV
93ps      592.9mV    568.4mV    502.6mV
108ps     522.4mV    569.5mV    410.9mV
124ps     428.2mV    549.7mV    360.2mV
144ps     355.7mV    462.4mV    331.7mV
174ps     311.9mV    353.7mV    317.7mV
212ps     296.9mV    301mV      313.8mV
408ps     292.8mV    280.6mV    313mV
[Rising Waveform]
R_fixture   = 50
V_fixture   = 0.6
V_fixture_min = 0.57
V_fixture_max = 0.65
|   Time   V(typ)   V(min)   V(max)
0s        292.7mV    280.5mV    312.9mV
63ps      293.1mV    278.3mV    324.5mV
69ps      298.1mV    278mV      351.2mV
78ps      318.4mV    281.1mV    428mV
97ps      419.9mV    326.2mV    545.4mV
115ps     499mV      407.1mV    598.9mV
135ps     549mV      475mV      626.7mV
164ps     581mV      530.1mV    642.3mV
204ps     595mV      558.1mV    648.3mV
408ps     600mV      569.9mV    650mV
[Falling Waveform]
R_fixture = 50
V_fixture = 0.0
|   Time   V(typ)   V(min)   V(max)
0s        236mV      224.3mV    267.2mV
63ps      238.1mV    225.8mV    260.7mV
72ps      235.8mV    226.8mV    229mV
82ps      222mV      225.9mV    151.6mV
96ps      162.9mV    214mV      73.97mV
112ps     79.78mV    169.5mV    33.08mV
130ps     34.08mV    98mV       13.53mV
154ps     11.22mV    36.39mV    4.158mV
188ps     2.517mV    8.572mV    853.2uV
408ps     141uV      147.5uV    60.12uV
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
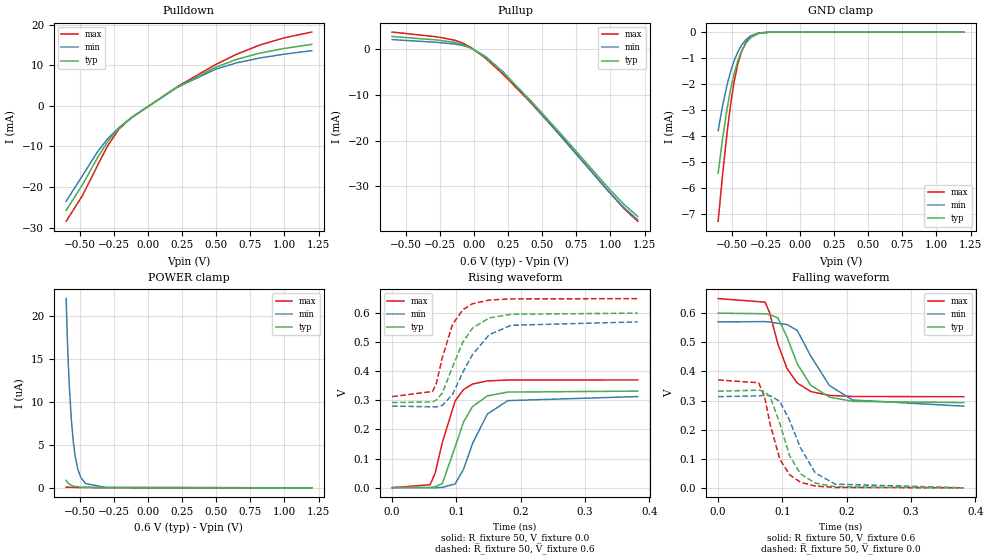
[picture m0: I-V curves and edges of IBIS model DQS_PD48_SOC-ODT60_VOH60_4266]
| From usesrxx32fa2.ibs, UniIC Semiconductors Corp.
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| DQS_PD48_SOC-ODT60_VOH60_4266
| (48 Ohm Pulldown, 60 Ohm System ODT Setting, VOH=VDDQ*0.60, 3200-4266Mbps)
[Model]   DQS_PD48_SOC-ODT60_VOH60_4266
Model_type   I/O
Vinl = 120.000mV
Vinh = 240.000mV
Vmeas = 180.000mV
Vref = 0.0mV
Cref = 0.0pF
Rref = 60.000Ohm
|   typ   min   max
|C_comp   0.849pF   0.799pF   0.899pF
C_comp_pullup   0.4245pF   0.3995pF   0.4495pF
C_comp_pulldown   0.4245pF   0.3995pF   0.4495pF
| Note: C_comp changes when the ODT circuit is enabled.
[Model Spec]
| Input threshold voltage corners
Vinl   0.1200V   0.1110V   0.1350V
Vinh   0.2400V   0.2310V   0.2550V
| Measurement voltage corners
Vmeas   0.1800V   0.1710V   0.1950V
| Timing spec test load voltage corners
Vref   0.0000V   0.0000V   0.0000V
| Dynamic Overshoot Parameters from LPDDR4_0P6 Specification
D_overshoot_ampl_h   0.30   NA   NA
D_overshoot_ampl_l   0.30   NA   NA
D_overshoot_area_h   0.1n   NA   NA
D_overshoot_area_l   0.1n   NA   NA
[Voltage Range]   0.6000V   0.5700V   0.6500V
[Pullup Reference]   0.6000V   0.5700V   0.6500V
| Junction Temperature (Ambient temp is 35C typ 95C min -40C max)
[Temperature Range]   50.0   110.0   -40.0
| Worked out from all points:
|   slope of the pulldown table from 0 to 0.09 V, typ, clamps not added: 44.5 ohm
|   slope of the pullup table from 0 to 0.09 V, typ, clamps not added: 49.6 ohm
|   GND clamp passes 1 mA (typ) near -0.45 V on its own axis
|   rising waveform, R_fixture 50, V_fixture 0.0: 20-80 % time 32ps typ, 36.3ps min, 27.7ps max; typ from 0 V to 0.332 V
|   falling waveform, R_fixture 50, V_fixture 0.6: 20-80 % time 39.6ps typ, 48.2ps min, 32.7ps max; typ from 0.6 V to 0.293 V
|   rising waveform, R_fixture 50, V_fixture 0.6: 20-80 % time 37ps typ, 45.9ps min, 27.7ps max; typ from 0.293 V to 0.6 V
|   falling waveform, R_fixture 50, V_fixture 0.0: 20-80 % time 31.4ps typ, 39.1ps min, 27.4ps max; typ from 0.332 V to 0 V
[Pulldown]
|   Voltage   I(typ)   I(min)   I(max)
-600mV    -25.78mA   -23.53mA   -28.46mA
-481.2mV  -19.52mA   -17.27mA   -22.18mA
-371.4mV  -12.89mA   -11.4mA    -14.79mA
-295.8mV  -8.823mA   -8.095mA   -9.869mA
-213mV    -5.515mA   -5.348mA   -5.738mA
-121.2mV  -2.911mA   -2.905mA   -2.878mA
213.6mV   4.61mA     4.541mA    4.697mA
494.4mV   9.498mA    9.03mA     10.17mA
649.2mV   11.46mA    10.61mA    12.72mA
818.4mV   13mA       11.8mA     15mA
998.4mV   14.17mA    12.75mA    16.78mA
1.2V      15.16mA    13.61mA    18.21mA
[GND Clamp]
|   Voltage   I(typ)   I(min)   I(max)
-600mV    -5.44mA    -3.803mA   -7.293mA
-567.6mV  -4.11mA    -2.838mA   -5.5mA
-535.2mV  -2.973mA   -2.045mA   -3.902mA
-508.2mV  -2.193mA   -1.512mA   -2.769mA
-483mV    -1.606mA   -1.108mA   -1.913mA
-456mV    -1.112mA   -767.5uA   -1.229mA
-429mV    -741.6uA   -509.9uA   -757.1uA
-396.6mV  -428.2uA   -293.2uA   -397uA
-358.8mV  -205uA     -140.8uA   -167.2uA
-303mV    -56.32uA   -40.76uA   -37.15uA
-220.2mV  -5.507uA   -4.907uA   -2.336uA
1.2V      0A         0A         0A
[Pullup]
|   Voltage   I(typ)   I(min)   I(max)
-600mV    2.847mA    2.16mA     3.822mA
-270.6mV  2.073mA    1.558mA    2.767mA
-142.8mV  1.569mA    1.2mA      2.05mA
-85.2mV   1.123mA    889.5uA    1.428mA
-25.8mV   399uA      330uA      491.6uA
82.2mV    -1.634mA   -1.486mA   -1.864mA
211.8mV   -5mA       -4.896mA   -5.399mA
417mV     -11.27mA   -11.5mA    -11.72mA
652.8mV   -19.08mA   -19.63mA   -19.56mA
984mV     -30.4mA    -31.1mA    -31.08mA
1.103V    -34.14mA   -34.85mA   -35.06mA
1.2V      -36.67mA   -37.43mA   -37.73mA
[POWER Clamp]
|   Voltage   I(typ)   I(min)   I(max)
-600mV    870.6nA    21.99uA    72.65nA
-589.2mV  630.3nA    16.59uA    68.66nA
-583.8mV  538.6nA    14.39uA    66.96nA
-576.6mV  439.1nA    11.87uA    64.76nA
-562.2mV  298.7nA    8.058uA    60.55nA
-547.8mV  210.8nA    5.449uA    56.57nA
-533.4mV  154.7nA    3.673uA    52.81nA
-513.6mV  108.8nA    2.141uA    47.98nA
-492mV    81.71nA    1.198uA    43.12nA
-457.8mV  60.42nA    497.2nA    36.26nA
-310.2mV  32.35nA    53.64nA    16.04nA
1.2V      0A         0A         0A
[Ramp]
|   typ   min   max
| 20% - 80%
dV/dt_r   199.04m/31.96p   187.82m/36.27p   222.27m/27.70p
dV/dt_f   184.34m/39.59p   173.63m/48.23p   202.23m/32.68p
| 25% - 75%
|dV/dt_r   165.87m/25.26p   156.52m/28.71p   185.23m/21.83p
|dV/dt_f   153.62m/31.27p   144.69m/38.15p   168.53m/25.78p
R_load = 50
[Rising Waveform]
R_fixture = 50
V_fixture = 0.0
|   Time   V(typ)   V(min)   V(max)
0s        177.8uV    163.1uV    83.28uV
59ps      598.4uV    -307.3uV   9.952mV
67ps      3.254mV    -614.4uV   50.5mV
78ps      14.01mV    955.7uV    154.4mV
98ps      140mV      12.78mV    298.2mV
111ps     225.4mV    62.77mV    337.1mV
125ps     278.8mV    151.5mV    356.2mV
148ps     315.4mV    252.7mV    367mV
180ps     328.7mV    299.3mV    370mV
382ps     331.9mV    313.2mV    370.5mV
[Falling Waveform]
R_fixture   = 50
V_fixture   = 0.6
V_fixture_min = 0.57
V_fixture_max = 0.65
|   Time   V(typ)   V(min)   V(max)
0s        600mV      570mV      650mV
73ps      598mV      571mV      637.9mV
80ps      595.3mV    569.7mV    601.9mV
93ps      583.7mV    565mV      493.9mV
107ps     518.6mV    561mV      410.4mV
123ps     426.2mV    541mV      360.2mV
144ps     352.3mV    452.9mV    330.8mV
173ps     311.7mV    351.7mV    317.6mV
209ps     297.2mV    301.8mV    313.9mV
382ps     292.8mV    280.6mV    313mV
[Rising Waveform]
R_fixture   = 50
V_fixture   = 0.6
V_fixture_min = 0.57
V_fixture_max = 0.65
|   Time   V(typ)   V(min)   V(max)
0s        292.7mV    280.5mV    312.9mV
63ps      294.6mV    277.8mV    330.8mV
69ps      301.7mV    277.8mV    359.7mV
78ps      325.1mV    282.7mV    446.8mV
94ps      415.3mV    320.8mV    561.5mV
110ps     500.6mV    396.8mV    611.9mV
125ps     548.6mV    457.9mV    632.3mV
151ps     583.6mV    525.9mV    645.1mV
185ps     596.1mV    558.2mV    649mV
382ps     600mV      570mV      650mV
[Falling Waveform]
R_fixture = 50
V_fixture = 0.0
|   Time   V(typ)   V(min)   V(max)
0s        332mV      313.3mV    370.6mV
63ps      335.5mV    315.9mV    361.1mV
72ps      331.3mV    317.8mV    314.4mV
81ps      312.3mV    316.8mV    217.4mV
96ps      220.4mV    296.5mV    98.04mV
111ps     111mV      232.3mV    45.28mV
128ps     48.31mV    137.4mV    19.22mV
151ps     16.28mV    51.42mV    6.199mV
182ps     4.046mV    12.85mV    1.458mV
382ps     228.4uV    238uV      101.9uV
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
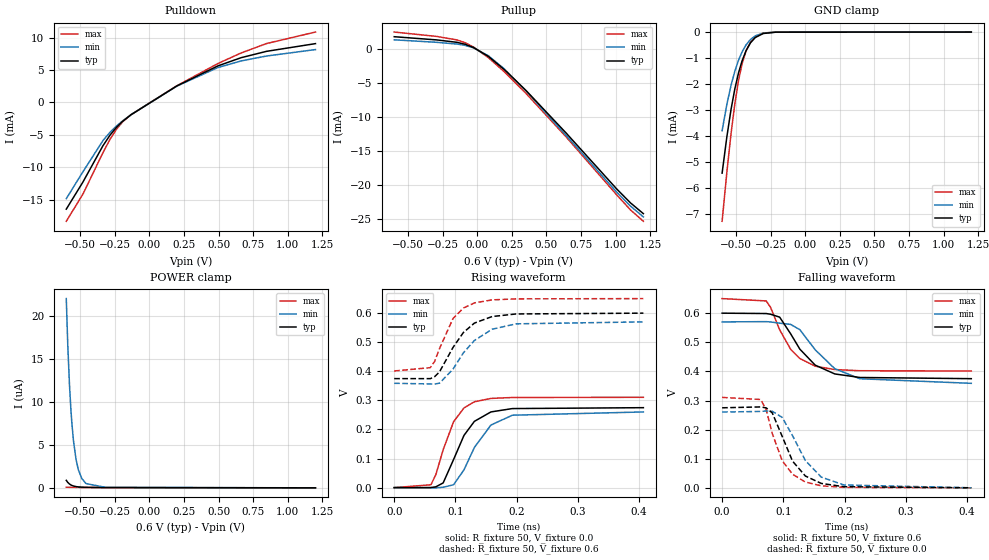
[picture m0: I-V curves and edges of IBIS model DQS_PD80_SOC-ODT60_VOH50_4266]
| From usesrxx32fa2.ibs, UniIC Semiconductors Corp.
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| DQS_PD80_SOC-ODT60_VOH50_4266
| (80 Ohm Pulldown, 60 Ohm System ODT Setting, VOH=VDDQ*0.50, 3200-4266Mbps)
[Model]   DQS_PD80_SOC-ODT60_VOH50_4266
Model_type   I/O
Vinl = 90.000mV
Vinh = 210.000mV
Vmeas = 150.000mV
Vref = 0.0mV
Cref = 0.0pF
Rref = 60.000Ohm
|   typ   min   max
|C_comp   0.849pF   0.799pF   0.899pF
C_comp_pullup   0.4245pF   0.3995pF   0.4495pF
C_comp_pulldown   0.4245pF   0.3995pF   0.4495pF
| Note: C_comp changes when the ODT circuit is enabled.
[Model Spec]
| Input threshold voltage corners
Vinl   0.0900V   0.0825V   0.1025V
Vinh   0.2100V   0.2025V   0.2225V
| Measurement voltage corners
Vmeas   0.1500V   0.1425V   0.1625V
| Timing spec test load voltage corners
Vref   0.0000V   0.0000V   0.0000V
| Dynamic Overshoot Parameters from LPDDR4_0P6 Specification
D_overshoot_ampl_h   0.30   NA   NA
D_overshoot_ampl_l   0.30   NA   NA
D_overshoot_area_h   0.1n   NA   NA
D_overshoot_area_l   0.1n   NA   NA
[Voltage Range]   0.6000V   0.5700V   0.6500V
[Pullup Reference]   0.6000V   0.5700V   0.6500V
| Junction Temperature (Ambient temp is 35C typ 95C min -40C max)
[Temperature Range]   50.0   110.0   -40.0
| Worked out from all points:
|   slope of the pulldown table from 0 to 0.09 V, typ, clamps not added: 75.4 ohm
|   slope of the pullup table from 0 to 0.09 V, typ, clamps not added: 75.7 ohm
|   GND clamp passes 1 mA (typ) near -0.45 V on its own axis
|   rising waveform, R_fixture 50, V_fixture 0.0: 20-80 % time 37.7ps typ, 42.4ps min, 32.5ps max; typ from 0 V to 0.275 V
|   falling waveform, R_fixture 50, V_fixture 0.6: 20-80 % time 48ps typ, 57.1ps min, 39.9ps max; typ from 0.6 V to 0.375 V
|   rising waveform, R_fixture 50, V_fixture 0.6: 20-80 % time 43.3ps typ, 50ps min, 33.9ps max; typ from 0.375 V to 0.6 V
|   falling waveform, R_fixture 50, V_fixture 0.0: 20-80 % time 37.2ps typ, 44.3ps min, 33.3ps max; typ from 0.275 V to 0 V
[Pulldown]
|   Voltage   I(typ)   I(min)   I(max)
-600mV    -16.42mA   -14.81mA   -18.29mA
-479.4mV  -12.24mA   -10.66mA   -14.1mA
-335.4mV  -6.672mA   -5.877mA   -7.738mA
-283.2mV  -5.001mA   -4.567mA   -5.638mA
-236.4mV  -3.8mA     -3.603mA   -4.089mA
-191.4mV  -2.88mA    -2.81mA    -2.954mA
-132mV    -1.888mA   -1.879mA   -1.867mA
199.2mV   2.55mA     2.52mA     2.579mA
496.2mV   5.638mA    5.382mA    6.001mA
663.6mV   6.895mA    6.396mA    7.625mA
847.2mV   7.873mA    7.151mA    9.072mA
1.2V      9.057mA    8.141mA    10.84mA
[GND Clamp]
|   Voltage   I(typ)   I(min)   I(max)
-600mV    -5.439mA   -3.802mA   -7.294mA
-565.8mV  -4.041mA   -2.789mA   -5.405mA
-535.2mV  -2.973mA   -2.045mA   -3.902mA
-508.2mV  -2.193mA   -1.512mA   -2.769mA
-481.2mV  -1.568mA   -1.083mA   -1.86mA
-456mV    -1.115mA   -767.1uA   -1.228mA
-427.2mV  -720.5uA   -494.8uA   -731.3uA
-394.8mV  -414.3uA   -284.1uA   -381.8uA
-360.6mV  -212.7uA   -146.5uA   -174.6uA
-303mV    -56.34uA   -40.79uA   -37.13uA
-211.2mV  -4.171uA   -3.814uA   -1.652uA
1.2V      0A         0A         0A
[Pullup]
|   Voltage   I(typ)   I(min)   I(max)
-600mV    1.862mA    1.404mA    2.549mA
-294mV    1.393mA    1.038mA    1.907mA
-146.4mV  1.034mA    781.5uA    1.389mA
-88.8mV   753.3uA    589.2uA    985.5uA
-27.6mV   276.4uA    226.9uA    350.7uA
80.4mV    -1.043mA   -940.4uA   -1.219mA
193.8mV   -2.95mA    -2.855mA   -3.273mA
352.2mV   -6.056mA   -6.126mA   -6.482mA
643.8mV   -12.36mA   -12.72mA   -12.93mA
1.009V    -20.59mA   -21.06mA   -21.46mA
1.108V    -22.62mA   -23.09mA   -23.66mA
1.2V      -24.19mA   -24.67mA   -25.31mA
[POWER Clamp]
|   Voltage   I(typ)   I(min)   I(max)
-600mV    870.6nA    21.99uA    72.65nA
-589.2mV  630.2nA    16.59uA    68.66nA
-576.6mV  440.3nA    11.88uA    64.76nA
-565.8mV  327.9nA    8.875uA    61.57nA
-558.6mV  272.4nA    7.315uA    59.53nA
-547.8mV  210.7nA    5.44uA     56.57nA
-529.8mV  144.2nA    3.328uA    51.9nA
-513.6mV  108.9nA    2.141uA    47.98nA
-488.4mV  78.55nA    1.09uA     42.36nA
-457.8mV  60.51nA    497nA      36.26nA
-317.4mV  33.15nA    55.95nA    16.74nA
1.2V      0A         0A         0A
[Ramp]
|   typ   min   max
| 20% - 80%
dV/dt_r   164.88m/37.73p   156.12m/42.38p   186.32m/32.50p
dV/dt_f   135.02m/48.01p   126.60m/57.13p   149.25m/39.88p
| 25% - 75%
|dV/dt_r   137.40m/29.87p   130.10m/33.57p   155.27m/25.71p
|dV/dt_f   112.52m/37.98p   105.50m/45.23p   124.37m/31.53p
R_load = 50
[Rising Waveform]
R_fixture = 50
V_fixture = 0.0
|   Time   V(typ)   V(min)   V(max)
0s        149.4uV    134.2uV    71.84uV
60ps      498.7uV    -475uV     9.957mV
68ps      2.885mV    -608.7uV   44.68mV
80ps      16.34mV    1.406mV    130.6mV
97ps      96.83mV    10.01mV    226.7mV
114ps     179.8mV    61.37mV    274.1mV
131ps     228mV      138.3mV    295.3mV
158ps     260.4mV    215.3mV    306.8mV
193ps     271.9mV    249.1mV    310mV
407ps     275mV      260.3mV    310.6mV
[Falling Waveform]
R_fixture   = 50
V_fixture   = 0.6
V_fixture_min = 0.57
V_fixture_max = 0.65
|   Time   V(typ)   V(min)   V(max)
0s        600mV      570mV      650mV
72ps      598.7mV    570.9mV    642mV
79ps      596.4mV    569.9mV    620.5mV
94ps      586.3mV    565.6mV    542.8mV
112ps     528.9mV    561.3mV    475.8mV
127ps     476.4mV    543.2mV    444.2mV
152ps     421.5mV    474.2mV    418mV
184ps     391.3mV    409.3mV    406.3mV
225ps     379.1mV    374.8mV    402.3mV
407ps     375mV      359mV      401.3mV
[Rising Waveform]
R_fixture   = 50
V_fixture   = 0.6
V_fixture_min = 0.57
V_fixture_max = 0.65
|   Time   V(typ)   V(min)   V(max)
0s        374.9mV    358.8mV    401.2mV
59ps      374.8mV    356.6mV    412.6mV
66ps      381.5mV    356.2mV    433.9mV
74ps      398.1mV    359.2mV    478mV
96ps      481.9mV    407.3mV    581.3mV
113ps     533.4mV    463.5mV    617.6mV
131ps     565.8mV    506mV      635.2mV
160ps     588.4mV    544.8mV    645.6mV
199ps     597.2mV    563.2mV    649.1mV
407ps     600mV      570mV      650mV
[Falling Waveform]
R_fixture = 50
V_fixture = 0.0
|   Time   V(typ)   V(min)   V(max)
0s        275mV      260.4mV    310.6mV
63ps      278mV      262.5mV    303.6mV
72ps      274.7mV    264mV      267.9mV
82ps      257.2mV    262.8mV    186.3mV
98ps      177.5mV    242.3mV    94.08mV
115ps     91.86mV    179.4mV    46.76mV
136ps     40.64mV    93.77mV    19.92mV
162ps     15.28mV    36.91mV    7.061mV
199ps     3.959mV    9.879mV    1.679mV
407ps     231.6uV    234.1uV    106.5uV
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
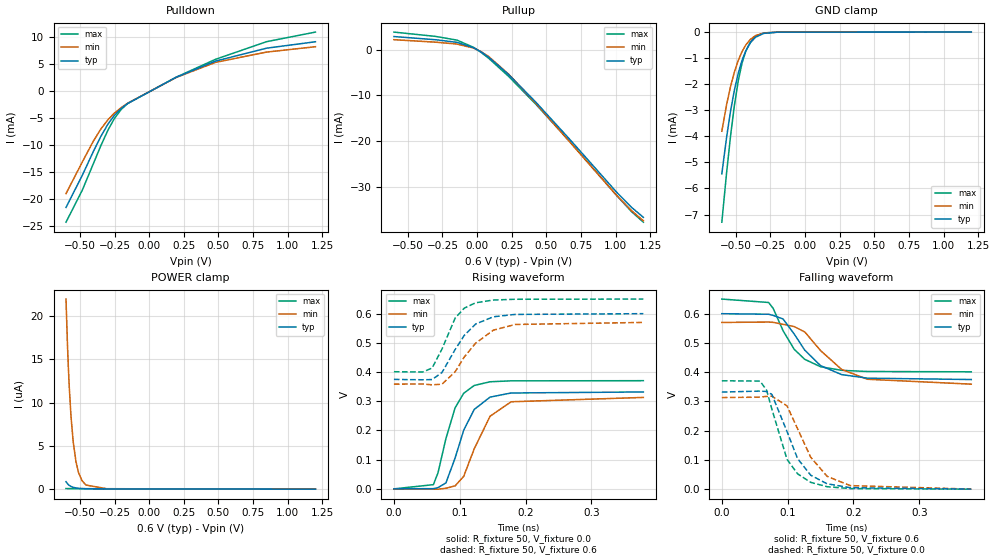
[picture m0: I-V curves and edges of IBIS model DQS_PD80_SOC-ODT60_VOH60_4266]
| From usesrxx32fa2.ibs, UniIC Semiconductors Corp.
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| DQS_PD80_SOC-ODT60_VOH60_4266
| (80 Ohm Pulldown, 60 Ohm System ODT Setting, VOH=VDDQ*0.60, 3200-4266Mbps)
[Model]   DQS_PD80_SOC-ODT60_VOH60_4266
Model_type   I/O
Vinl = 120.000mV
Vinh = 240.000mV
Vmeas = 180.000mV
Vref = 0.0mV
Cref = 0.0pF
Rref = 60.000Ohm
|   typ   min   max
|C_comp   0.849pF   0.799pF   0.899pF
C_comp_pullup   0.4245pF   0.3995pF   0.4495pF
C_comp_pulldown   0.4245pF   0.3995pF   0.4495pF
| Note: C_comp changes when the ODT circuit is enabled.
[Model Spec]
| Input threshold voltage corners
Vinl   0.1200V   0.1110V   0.1350V
Vinh   0.2400V   0.2310V   0.2550V
| Measurement voltage corners
Vmeas   0.1800V   0.1710V   0.1950V
| Timing spec test load voltage corners
Vref   0.0000V   0.0000V   0.0000V
| Dynamic Overshoot Parameters from LPDDR4_0P6 Specification
D_overshoot_ampl_h   0.30   NA   NA
D_overshoot_ampl_l   0.30   NA   NA
D_overshoot_area_h   0.1n   NA   NA
D_overshoot_area_l   0.1n   NA   NA
[Voltage Range]   0.6000V   0.5700V   0.6500V
[Pullup Reference]   0.6000V   0.5700V   0.6500V
| Junction Temperature (Ambient temp is 35C typ 95C min -40C max)
[Temperature Range]   50.0   110.0   -40.0
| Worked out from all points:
|   slope of the pulldown table from 0 to 0.09 V, typ, clamps not added: 75.2 ohm
|   slope of the pullup table from 0 to 0.09 V, typ, clamps not added: 49.6 ohm
|   GND clamp passes 1 mA (typ) near -0.45 V on its own axis
|   rising waveform, R_fixture 50, V_fixture 0.0: 20-80 % time 32.2ps typ, 36.7ps min, 27.7ps max; typ from 0 V to 0.332 V
|   falling waveform, R_fixture 50, V_fixture 0.6: 20-80 % time 48.6ps typ, 58.1ps min, 40.1ps max; typ from 0.6 V to 0.375 V
|   rising waveform, R_fixture 50, V_fixture 0.6: 20-80 % time 39.6ps typ, 45.9ps min, 29.7ps max; typ from 0.375 V to 0.6 V
|   falling waveform, R_fixture 50, V_fixture 0.0: 20-80 % time 37ps typ, 43.5ps min, 33.1ps max; typ from 0.332 V to 0 V
[Pulldown]
|   Voltage   I(typ)   I(min)   I(max)
-600mV    -21.51mA   -18.95mA   -24.22mA
-483mV    -15.61mA   -13.15mA   -18.34mA
-403.8mV  -11.24mA   -9.325mA   -13.51mA
-349.8mV  -8.45mA    -7.079mA   -10.18mA
-295.8mV  -6.071mA   -5.274mA   -7.175mA
-250.8mV  -4.514mA   -4.104mA   -5.103mA
-202.2mV  -3.254mA   -3.096mA   -3.437mA
-155.4mV  -2.33mA    -2.284mA   -2.342mA
193.8mV   2.485mA    2.457mA    2.512mA
478.2mV   5.482mA    5.248mA    5.812mA
847.2mV   7.873mA    7.151mA    9.072mA
1.2V      9.057mA    8.141mA    10.84mA
[GND Clamp]
|   Voltage   I(typ)   I(min)   I(max)
-600mV    -5.44mA    -3.802mA   -7.294mA
-565.8mV  -4.041mA   -2.789mA   -5.405mA
-537mV    -3.031mA   -2.085mA   -3.984mA
-510mV    -2.241mA   -1.544mA   -2.838mA
-481.2mV  -1.569mA   -1.083mA   -1.861mA
-454.2mV  -1.084mA   -747.6uA   -1.191mA
-427.2mV  -721.9uA   -495.1uA   -731.4uA
-393mV    -402.2uA   -274.5uA   -366.9uA
-357mV    -196.8uA   -136.1uA   -159.9uA
-297.6mV  -49.33uA   -36.01uA   -31.75uA
-195mV    -2.53uA    -2.429uA   -868.3nA
1.2V      0A         0A         0A
[Pullup]
|   Voltage   I(typ)   I(min)   I(max)
-600mV    2.847mA    2.16mA     3.822mA
-299.4mV  2.153mA    1.619mA    2.878mA
-144.6mV  1.58mA     1.206mA    2.065mA
-25.8mV   398uA      329.9uA    491.6uA
26.4mV    -466.5uA   -403.1uA   -553.3uA
85.8mV    -1.717mA   -1.566mA   -1.954mA
228mV     -5.464mA   -5.381mA   -5.872mA
424.2mV   -11.5mA    -11.75mA   -11.95mA
665.4mV   -19.51mA   -20.07mA   -19.99mA
1.007V    -31.17mA   -31.86mA   -31.89mA
1.115V    -34.49mA   -35.22mA   -35.44mA
1.2V      -36.67mA   -37.43mA   -37.73mA
[POWER Clamp]
|   Voltage   I(typ)   I(min)   I(max)
-600mV    870.6nA    21.99uA    72.65nA
-589.2mV  630.1nA    16.59uA    68.66nA
-582mV    511.4nA    13.71uA    66.41nA
-576.6mV  439.2nA    11.87uA    64.76nA
-564mV    312.7nA    8.454uA    61.06nA
-547.8mV  210.4nA    5.443uA    56.56nA
-528mV    139.3nA    3.166uA    51.46nA
-510mV    103.3nA    1.943uA    47.14nA
-484.8mV  75.7nA     991.9nA    41.6nA
-456mV    59.66nA    475.8nA    35.93nA
-306.6mV  31.96nA    52.61nA    15.71nA
1.2V      0A         0A         0A
[Ramp]
|   typ   min   max
| 20% - 80%
dV/dt_r   199.01m/32.17p   187.78m/36.70p   222.25m/27.69p
dV/dt_f   135.04m/48.56p   126.56m/58.14p   149.26m/40.11p
| 25% - 75%
|dV/dt_r   165.84m/25.43p   156.48m/29.03p   185.21m/21.88p
|dV/dt_f   112.53m/38.38p   105.47m/45.91p   124.38m/31.68p
R_load = 50
[Rising Waveform]
R_fixture = 50
V_fixture = 0.0
|   Time   V(typ)   V(min)   V(max)
0s        239.6uV    227uV      109.5uV
60ps      851.3uV    -737.1uV   14.52mV
67ps      4.314mV    -931.2uV   55.44mV
79ps      20.4mV     2.067mV    172.2mV
93ps      106mV      10.45mV    277.8mV
106ps     200.7mV    42.83mV    327.3mV
122ps     272mV      137.1mV    354.1mV
146ps     314.2mV    248.6mV    366.8mV
178ps     328.4mV    298.3mV    370mV
379ps     331.9mV    313.2mV    370.5mV
[Falling Waveform]
R_fixture   = 50
V_fixture   = 0.6
V_fixture_min = 0.57
V_fixture_max = 0.65
|   Time   V(typ)   V(min)   V(max)
0s        600mV      570mV      650mV
71ps      598.1mV    571.5mV    638.3mV
78ps      594.2mV    570.3mV    618.3mV
93ps      582mV      563.6mV    542mV
110ps     530.4mV    555.9mV    478.1mV
126ps     475.2mV    537.7mV    444mV
150ps     422.5mV    473.9mV    418.6mV
182ps     391.8mV    409.5mV    406.4mV
221ps     379.6mV    375.9mV    402.4mV
379ps     374.9mV    359.1mV    401.3mV
[Rising Waveform]
R_fixture   = 50
V_fixture   = 0.6
V_fixture_min = 0.57
V_fixture_max = 0.65
|   Time   V(typ)   V(min)   V(max)
0s        374.9mV    358.8mV    401.2mV
44ps      373.6mV    359.2mV    400.3mV
58ps      374.4mV    356.4mV    413.8mV
73ps      398.4mV    358.5mV    478.7mV
93ps      477.1mV    400.9mV    584.8mV
107ps     525.9mV    452mV      619mV
124ps     564.3mV    498.6mV    637.2mV
151ps     589.3mV    543.4mV    646.7mV
184ps     597.4mV    563mV      649.3mV
379ps     600mV      570mV      650mV
[Falling Waveform]
R_fixture = 50
V_fixture = 0.0
|   Time   V(typ)   V(min)   V(max)
0s        332mV      313.3mV    370.6mV
58ps      335.5mV    314.7mV    369.7mV
68ps      334mV      317.4mV    338.7mV
76ps      324.1mV    318.1mV    273.9mV
99ps      197.5mV    285mV      102.2mV
115ps     104.9mV    207mV      52.84mV
135ps     47.84mV    109.4mV    23.41mV
160ps     18.51mV    43.83mV    8.578mV
195ps     5.191mV    12.36mV    2.185mV
379ps     297uV      318.9uV    135.8uV
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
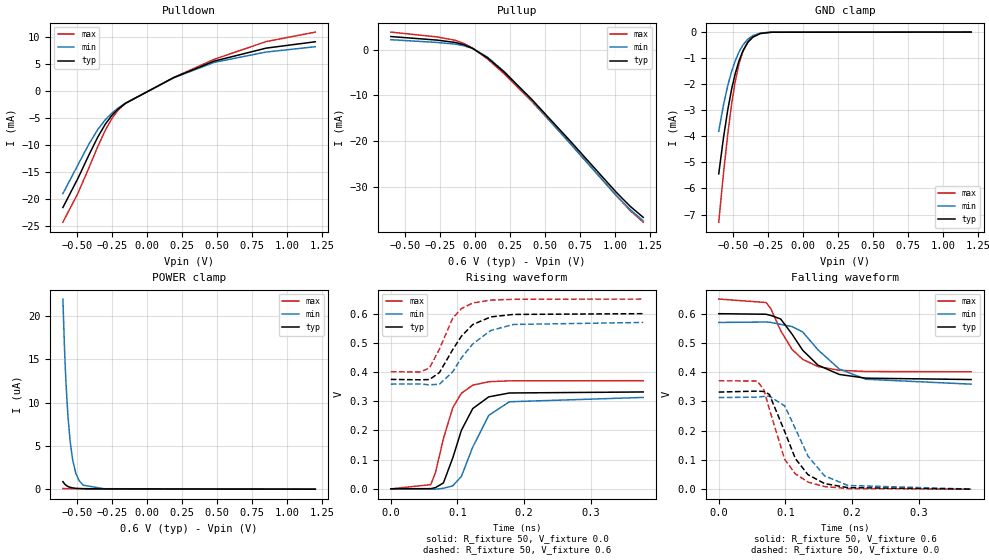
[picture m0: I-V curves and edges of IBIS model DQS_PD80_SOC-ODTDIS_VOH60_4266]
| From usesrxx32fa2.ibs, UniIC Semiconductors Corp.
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| DQS_PD80_SOC-ODTDIS_VOH60_4266
| (80 Ohm Pulldown, SOC ODT disabled setting, VOH=VDDQ*0.60 cal. point, 3200-4266Mbps)
[Model]   DQS_PD80_SOC-ODTDIS_VOH60_4266
Model_type   I/O
Vinl = 120.000mV
Vinh = 240.000mV
Vmeas = 180.000mV
Vref = 0.0mV
Cref = 0.0pF
|   typ   min   max
|C_comp   0.849pF   0.799pF   0.899pF
C_comp_pullup   0.4245pF   0.3995pF   0.4495pF
C_comp_pulldown   0.4245pF   0.3995pF   0.4495pF
| Note: C_comp changes when the ODT circuit is enabled.
[Model Spec]
| Input threshold voltage corners
Vinl   0.1200V   0.1110V   0.1350V
Vinh   0.2400V   0.2310V   0.2550V
| Measurement voltage corners
Vmeas   0.1800V   0.1710V   0.1950V
| Timing spec test load voltage corners
Vref   0.0000V   0.0000V   0.0000V
| Dynamic Overshoot Parameters from LPDDR4_0P6 Specification
D_overshoot_ampl_h   0.30   NA   NA
D_overshoot_ampl_l   0.30   NA   NA
D_overshoot_area_h   0.1n   NA   NA
D_overshoot_area_l   0.1n   NA   NA
[Voltage Range]   0.6000V   0.5700V   0.6500V
[Pullup Reference]   0.6000V   0.5700V   0.6500V
| Junction Temperature (Ambient temp is 35C typ 95C min -40C max)
[Temperature Range]   50.0   110.0   -40.0
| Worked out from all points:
|   slope of the pulldown table from 0 to 0.09 V, typ, clamps not added: 75.2 ohm
|   slope of the pullup table from 0 to 0.09 V, typ, clamps not added: 49.6 ohm
|   GND clamp passes 1 mA (typ) near -0.45 V on its own axis
|   rising waveform, R_fixture 50, V_fixture 0.0: 20-80 % time 32.2ps typ, 36.7ps min, 27.7ps max; typ from 0 V to 0.332 V
|   falling waveform, R_fixture 50, V_fixture 0.6: 20-80 % time 48.6ps typ, 58.1ps min, 40.1ps max; typ from 0.6 V to 0.375 V
|   rising waveform, R_fixture 50, V_fixture 0.6: 20-80 % time 39.6ps typ, 45.9ps min, 29.7ps max; typ from 0.375 V to 0.6 V
|   falling waveform, R_fixture 50, V_fixture 0.0: 20-80 % time 37ps typ, 43.5ps min, 33.1ps max; typ from 0.332 V to 0 V
[Pulldown]
|   Voltage   I(typ)   I(min)   I(max)
-600mV    -21.51mA   -18.95mA   -24.22mA
-492mV    -16.1mA    -13.61mA   -18.84mA
-416.4mV  -11.92mA   -9.901mA   -14.3mA
-351.6mV  -8.537mA   -7.147mA   -10.29mA
-297.6mV  -6.14mA    -5.327mA   -7.267mA
-250.8mV  -4.514mA   -4.104mA   -5.102mA
-205.8mV  -3.334mA   -3.165mA   -3.541mA
-153.6mV  -2.299mA   -2.254mA   -2.308mA
190.2mV   2.442mA    2.415mA    2.467mA
480mV     5.497mA    5.261mA    5.831mA
849mV     7.88mA     7.157mA    9.084mA
1.2V      9.057mA    8.141mA    10.84mA
[GND Clamp]
|   Voltage   I(typ)   I(min)   I(max)
-600mV    -5.44mA    -3.803mA   -7.294mA
-565.8mV  -4.041mA   -2.789mA   -5.405mA
-535.2mV  -2.974mA   -2.045mA   -3.902mA
-508.2mV  -2.194mA   -1.512mA   -2.769mA
-483mV    -1.607mA   -1.11mA    -1.914mA
-456mV    -1.113mA   -768.4uA   -1.229mA
-427.2mV  -720.6uA   -495.9uA   -731.5uA
-393mV    -401.1uA   -274.6uA   -367.8uA
-357mV    -196.8uA   -136.5uA   -159.9uA
-303mV    -56.33uA   -41.07uA   -37.18uA
-225.6mV  -6.487uA   -5.702uA   -2.83uA
1.2V      0A         0A         0A
[Pullup]
|   Voltage   I(typ)   I(min)   I(max)
-600mV    2.847mA    2.16mA     3.822mA
-270.6mV  2.072mA    1.558mA    2.767mA
-141mV    1.558mA    1.193mA    2.035mA
-78mV     1.049mA    835.5uA    1.329mA
-16.8mV   265.5uA    220.8uA    325.7uA
89.4mV    -1.8mA     -1.646mA   -2.045mA
213.6mV   -5.051mA   -4.949mA   -5.451mA
406.2mV   -10.92mA   -11.14mA   -11.37mA
676.2mV   -19.88mA   -20.45mA   -20.36mA
1.007V    -31.17mA   -31.86mA   -31.89mA
1.11V     -34.34mA   -35.06mA   -35.28mA
1.2V      -36.67mA   -37.43mA   -37.73mA
[POWER Clamp]
|   Voltage   I(typ)   I(min)   I(max)
-600mV    870.6nA    21.99uA    72.65nA
-589.2mV  630.1nA    16.59uA    68.66nA
-582mV    511.4nA    13.71uA    66.41nA
-576.6mV  439.3nA    11.88uA    64.76nA
-564mV    312.6nA    8.455uA    61.06nA
-547.8mV  210.3nA    5.442uA    56.57nA
-529.8mV  144.5nA    3.329uA    51.9nA
-508.2mV  100.6nA    1.855uA    46.72nA
-484.8mV  75.83nA    993.5nA    41.6nA
-454.2mV  58.97nA    456.9nA    35.6nA
-306.6mV  31.96nA    52.6nA     15.71nA
1.2V      0A         0A         0A
[Ramp]
|   typ   min   max
| 20% - 80%
dV/dt_r   199.01m/32.17p   187.78m/36.70p   222.25m/27.69p
dV/dt_f   135.04m/48.56p   126.56m/58.14p   149.25m/40.12p
| 25% - 75%
|dV/dt_r   165.84m/25.43p   156.48m/29.03p   185.21m/21.89p
|dV/dt_f   112.53m/38.38p   105.47m/45.91p   124.37m/31.64p
R_load = 50
[Rising Waveform]
R_fixture = 50
V_fixture = 0.0
|   Time   V(typ)   V(min)   V(max)
0s        239.6uV    227uV      109.5uV
60ps      851.3uV    -737.1uV   14.52mV
67ps      4.314mV    -931.2uV   55.44mV
79ps      20.4mV     2.067mV    172.2mV
93ps      106mV      10.45mV    277.8mV
106ps     200.7mV    42.83mV    327.4mV
123ps     275mV      143.3mV    355.1mV
147ps     315.1mV    251.5mV    367mV
178ps     328.4mV    298.3mV    370mV
379ps     331.9mV    313.2mV    370.5mV
[Falling Waveform]
R_fixture   = 50
V_fixture   = 0.6
V_fixture_min = 0.57
V_fixture_max = 0.65
|   Time   V(typ)   V(min)   V(max)
0s        600mV      570mV      650mV
71ps      598.1mV    571.5mV    638.3mV
78ps      594.2mV    570.3mV    618.3mV
93ps      582mV      563.6mV    542mV
110ps     530.4mV    555.9mV    478.1mV
126ps     475.2mV    537.7mV    444mV
149ps     424.1mV    476.6mV    419.3mV
181ps     392.3mV    410.9mV    406.6mV
221ps     379.6mV    375.9mV    402.4mV
379ps     374.9mV    359.1mV    401.3mV
[Rising Waveform]
R_fixture   = 50
V_fixture   = 0.6
V_fixture_min = 0.57
V_fixture_max = 0.65
|   Time   V(typ)   V(min)   V(max)
0s        374.9mV    358.8mV    401.2mV
44ps      373.6mV    359.2mV    400.3mV
58ps      374.4mV    356.4mV    413.8mV
73ps      398.4mV    358.5mV    478.7mV
93ps      477.1mV    400.9mV    584.8mV
106ps     522.8mV    448.7mV    617.3mV
123ps     562.7mV    496.3mV    636.5mV
150ps     588.8mV    542.3mV    646.5mV
184ps     597.4mV    563mV      649.3mV
379ps     600mV      570mV      650mV
[Falling Waveform]
R_fixture = 50
V_fixture = 0.0
|   Time   V(typ)   V(min)   V(max)
0s        332mV      313.3mV    370.6mV
58ps      335.5mV    314.7mV    369.7mV
68ps      334mV      317.4mV    338.7mV
76ps      324.1mV    318.1mV    273.9mV
99ps      197.5mV    285mV      102.3mV
115ps     104.9mV    207mV      52.85mV
134ps     49.72mV    113.3mV    24.4mV
159ps     19.18mV    45.49mV    8.927mV
194ps     5.386mV    12.81mV    2.269mV
379ps     297uV      318.9uV    146.7uV
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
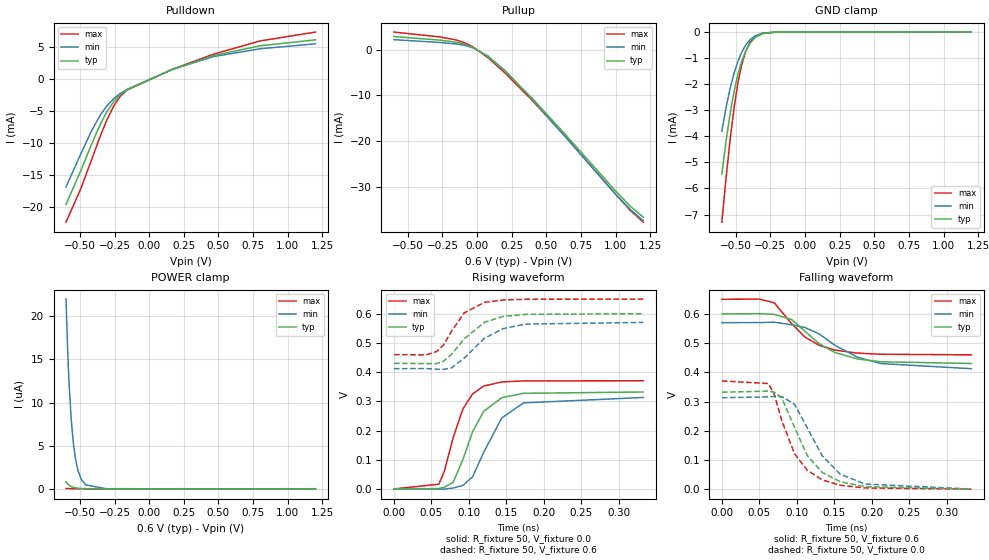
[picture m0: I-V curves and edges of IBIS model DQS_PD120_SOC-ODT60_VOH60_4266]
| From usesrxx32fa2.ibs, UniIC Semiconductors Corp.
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| DQS_PD120_SOC-ODT60_VOH60_4266
| (120 Ohm Pulldown, 60 Ohm System ODT Setting, VOH=VDDQ*0.60, 3200-4266Mbps)
[Model]   DQS_PD120_SOC-ODT60_VOH60_4266
Model_type   I/O
Vinl = 120.000mV
Vinh = 240.000mV
Vmeas = 180.000mV
Vref = 0.0mV
Cref = 0.0pF
Rref = 60.000Ohm
|   typ   min   max
|C_comp   0.849pF   0.799pF   0.899pF
C_comp_pullup   0.4245pF   0.3995pF   0.4495pF
C_comp_pulldown   0.4245pF   0.3995pF   0.4495pF
| Note: C_comp changes when the ODT circuit is enabled.
[Model Spec]
| Input threshold voltage corners
Vinl   0.1200V   0.1110V   0.1350V
Vinh   0.2400V   0.2310V   0.2550V
| Measurement voltage corners
Vmeas   0.1800V   0.1710V   0.1950V
| Timing spec test load voltage corners
Vref   0.0000V   0.0000V   0.0000V
| Dynamic Overshoot Parameters from LPDDR4_0P6 Specification
D_overshoot_ampl_h   0.30   NA   NA
D_overshoot_ampl_l   0.30   NA   NA
D_overshoot_area_h   0.1n   NA   NA
D_overshoot_area_l   0.1n   NA   NA
[Voltage Range]   0.6000V   0.5700V   0.6500V
[Pullup Reference]   0.6000V   0.5700V   0.6500V
| Junction Temperature (Ambient temp is 35C typ 95C min -40C max)
[Temperature Range]   50.0   110.0   -40.0
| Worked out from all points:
|   slope of the pulldown table from 0 to 0.09 V, typ, clamps not added: 111 ohm
|   slope of the pullup table from 0 to 0.09 V, typ, clamps not added: 49.6 ohm
|   GND clamp passes 1 mA (typ) near -0.45 V on its own axis
|   rising waveform, R_fixture 50, V_fixture 0.0: 20-80 % time 32.3ps typ, 37ps min, 27.8ps max; typ from 0 V to 0.332 V
|   falling waveform, R_fixture 50, V_fixture 0.6: 20-80 % time 53.9ps typ, 64.1ps min, 44.8ps max; typ from 0.6 V to 0.43 V
|   rising waveform, R_fixture 50, V_fixture 0.6: 20-80 % time 39.5ps typ, 43.6ps min, 30.5ps max; typ from 0.43 V to 0.6 V
|   falling waveform, R_fixture 50, V_fixture 0.0: 20-80 % time 40.3ps typ, 45.5ps min, 36.9ps max; typ from 0.332 V to 0 V
[Pulldown]
|   Voltage   I(typ)   I(min)   I(max)
-600mV    -19.55mA   -16.82mA   -22.31mA
-492mV    -14.24mA   -11.63mA   -17.04mA
-418.2mV  -10.32mA   -8.209mA   -12.76mA
-357mV    -7.296mA   -5.797mA   -9.157mA
-308.4mV  -5.253mA   -4.291mA   -6.553mA
-254.4mV  -3.515mA   -3.054mA   -4.179mA
-209.4mV  -2.498mA   -2.299mA   -2.755mA
-160.8mV  -1.719mA   -1.655mA   -1.759mA
168.6mV   1.473mA    1.457mA    1.488mA
463.8mV   3.608mA    3.453mA    3.829mA
804mV     5.149mA    4.683mA    5.908mA
1.2V      6.059mA    5.442mA    7.269mA
[GND Clamp]
|   Voltage   I(typ)   I(min)   I(max)
-600mV    -5.44mA    -3.803mA   -7.294mA
-567.6mV  -4.11mA    -2.838mA   -5.5mA
-537mV    -3.03mA    -2.086mA   -3.984mA
-511.8mV  -2.289mA   -1.577mA   -2.908mA
-483mV    -1.606mA   -1.108mA   -1.914mA
-457.8mV  -1.141mA   -787uA     -1.267mA
-427.2mV  -722.7uA   -494.8uA   -731.6uA
-394.8mV  -414.5uA   -284uA     -382.2uA
-358.8mV  -204.6uA   -141.3uA   -167.3uA
-306.6mV  -61.81uA   -44.48uA   -41.26uA
-216.6mV  -4.981uA   -4.438uA   -2.039uA
1.2V      0A         0A         0A
[Pullup]
|   Voltage   I(typ)   I(min)   I(max)
-600mV    2.847mA    2.16mA     3.822mA
-270.6mV  2.072mA    1.558mA    2.767mA
-144.6mV  1.579mA    1.207mA    2.065mA
-88.8mV   1.158mA    914.8uA    1.475mA
-24mV     372.9uA    308.5uA    458.9uA
78.6mV    -1.552mA   -1.408mA   -1.774mA
206.4mV   -4.847mA   -4.736mA   -5.242mA
408mV     -10.98mA   -11.2mA    -11.43mA
640.2mV   -18.66mA   -19.19mA   -19.13mA
991.2mV   -30.64mA   -31.33mA   -31.33mA
1.106V    -34.24mA   -34.96mA   -35.17mA
1.2V      -36.67mA   -37.43mA   -37.73mA
[POWER Clamp]
|   Voltage   I(typ)   I(min)   I(max)
-600mV    870.6nA    21.99uA    72.65nA
-589.2mV  630.1nA    16.59uA    68.66nA
-583.8mV  538.8nA    14.38uA    66.96nA
-576.6mV  440.1nA    11.88uA    64.76nA
-562.2mV  298.5nA    8.052uA    60.55nA
-547.8mV  210.3nA    5.447uA    56.57nA
-533.4mV  154.3nA    3.681uA    52.81nA
-513.6mV  108.9nA    2.145uA    47.98nA
-490.2mV  80.12nA    1.144uA    42.74nA
-457.8mV  60.41nA    496.8nA    36.26nA
-313.8mV  32.74nA    54.74nA    16.39nA
1.2V      0A         0A         0A
[Ramp]
|   typ   min   max
| 20% - 80%
dV/dt_r   198.98m/32.32p   187.74m/36.99p   222.24m/27.79p
dV/dt_f   101.89m/53.91p   94.53m/64.07p   114.03m/44.81p
| 25% - 75%
|dV/dt_r   165.81m/25.57p   156.45m/29.25p   185.20m/21.99p
|dV/dt_f   84.91m/42.58p   78.77m/50.47p   95.02m/35.38p
R_load = 50
[Rising Waveform]
R_fixture = 50
V_fixture = 0.0
|   Time   V(typ)   V(min)   V(max)
0s        284.9uV    275.2uV    129.6uV
60ps      1.414mV    -703.1uV   16.19mV
67ps      5.46mV     -603.1uV   57.94mV
79ps      22.54mV    3.276mV    174.3mV
92ps      100mV      12.02mV    273.4mV
105ps     195.6mV    41.33mV    325.3mV
120ps     266.2mV    126.2mV    352.2mV
144ps     312.4mV    243.1mV    366.3mV
173ps     327.4mV    294.6mV    369.8mV
333ps     331.9mV    313.2mV    370.5mV
[Falling Waveform]
R_fixture   = 50
V_fixture   = 0.6
V_fixture_min = 0.57
V_fixture_max = 0.65
|   Time   V(typ)   V(min)   V(max)
0s        600mV      570mV      650mV
50ps      601.1mV    570.4mV    650.9mV
70ps      598.3mV    571.7mV    638.1mV
93ps      580.9mV    563mV      567.3mV
111ps     540.5mV    553.4mV    520.7mV
130ps     498mV      531.6mV    492.6mV
151ps     467.9mV    492.6mV    476.2mV
181ps     445.9mV    451.9mV    465.9mV
212ps     436.4mV    430.2mV    462mV
333ps     430.2mV    412.5mV    460mV
[Rising Waveform]
R_fixture   = 50
V_fixture   = 0.6
V_fixture_min = 0.57
V_fixture_max = 0.65
|   Time   V(typ)   V(min)   V(max)
0s        430mV      411.7mV    459.9mV
43ps      429mV      412.2mV    459mV
57ps      429.1mV    409.8mV    470.3mV
66ps      437.1mV    409.1mV    492.1mV
77ps      460.7mV    414.4mV    540.1mV
94ps      514.2mV    448.4mV    602.9mV
121ps     570.8mV    516.1mV    638.8mV
146ps     590.6mV    549mV      646.9mV
176ps     597.6mV    564.3mV    649.3mV
333ps     600mV      570mV      650mV
[Falling Waveform]
R_fixture = 50
V_fixture = 0.0
|   Time   V(typ)   V(min)   V(max)
0s        332mV      313.3mV    370.6mV
62ps      335.8mV    315.9mV    361.8mV
70ps      332.3mV    317.9mV    325mV
80ps      312.5mV    317.2mV    235.1mV
97ps      212.1mV    290.9mV    121.6mV
114ps     115.5mV    210.4mV    65.32mV
134ps     57.52mV    114.4mV    31.82mV
158ps     25.67mV    51.65mV    13.59mV
191ps     8.717mV    17.78mV    4.332mV
333ps     416.5uV    555.3uV    188.2uV
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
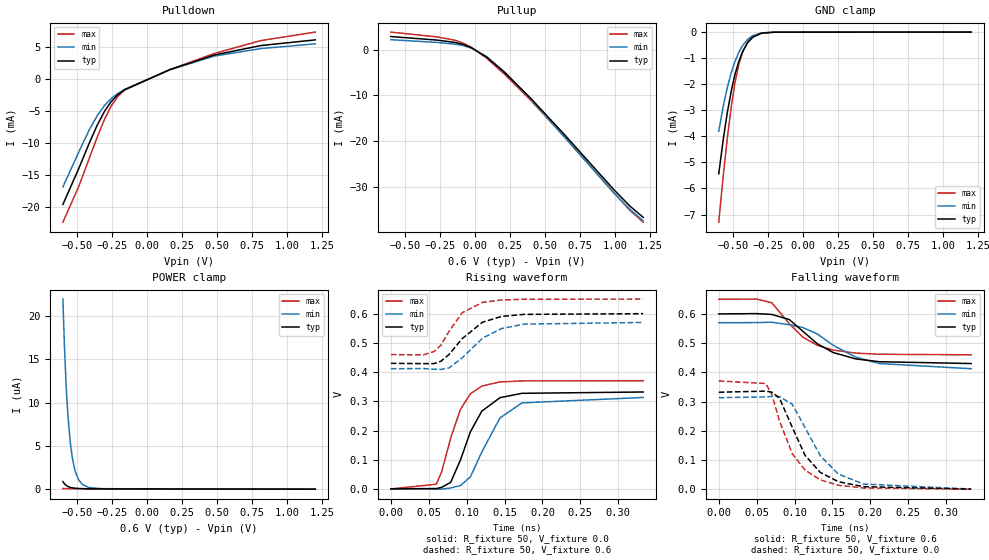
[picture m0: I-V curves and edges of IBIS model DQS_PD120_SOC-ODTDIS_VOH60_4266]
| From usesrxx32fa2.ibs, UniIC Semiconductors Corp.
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| DQS_PD120_SOC-ODTDIS_VOH60_4266
| (120 Ohm Pulldown, SOC ODT disabled setting, VOH=VDDQ*0.60 cal. point, 3200-4266Mbps)
[Model]   DQS_PD120_SOC-ODTDIS_VOH60_4266
Model_type   I/O
Vinl = 120.000mV
Vinh = 240.000mV
Vmeas = 180.000mV
Vref = 0.0mV
Cref = 0.0pF
|   typ   min   max
|C_comp   0.849pF   0.799pF   0.899pF
C_comp_pullup   0.4245pF   0.3995pF   0.4495pF
C_comp_pulldown   0.4245pF   0.3995pF   0.4495pF
| Note: C_comp changes when the ODT circuit is enabled.
[Model Spec]
| Input threshold voltage corners
Vinl   0.1200V   0.1110V   0.1350V
Vinh   0.2400V   0.2310V   0.2550V
| Measurement voltage corners
Vmeas   0.1800V   0.1710V   0.1950V
| Timing spec test load voltage corners
Vref   0.0000V   0.0000V   0.0000V
| Dynamic Overshoot Parameters from LPDDR4_0P6 Specification
D_overshoot_ampl_h   0.30   NA   NA
D_overshoot_ampl_l   0.30   NA   NA
D_overshoot_area_h   0.1n   NA   NA
D_overshoot_area_l   0.1n   NA   NA
[Voltage Range]   0.6000V   0.5700V   0.6500V
[Pullup Reference]   0.6000V   0.5700V   0.6500V
| Junction Temperature (Ambient temp is 35C typ 95C min -40C max)
[Temperature Range]   50.0   110.0   -40.0
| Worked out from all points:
|   slope of the pulldown table from 0 to 0.09 V, typ, clamps not added: 111 ohm
|   slope of the pullup table from 0 to 0.09 V, typ, clamps not added: 49.6 ohm
|   GND clamp passes 1 mA (typ) near -0.45 V on its own axis
|   rising waveform, R_fixture 50, V_fixture 0.0: 20-80 % time 32.3ps typ, 37ps min, 27.8ps max; typ from 0 V to 0.332 V
|   falling waveform, R_fixture 50, V_fixture 0.6: 20-80 % time 53.9ps typ, 64.1ps min, 44.8ps max; typ from 0.6 V to 0.43 V
|   rising waveform, R_fixture 50, V_fixture 0.6: 20-80 % time 39.5ps typ, 43.6ps min, 30.5ps max; typ from 0.43 V to 0.6 V
|   falling waveform, R_fixture 50, V_fixture 0.0: 20-80 % time 40.3ps typ, 45.5ps min, 36.9ps max; typ from 0.332 V to 0 V
[Pulldown]
|   Voltage   I(typ)   I(min)   I(max)
-600mV    -19.55mA   -16.82mA   -22.31mA
-486.6mV  -13.95mA   -11.37mA   -16.74mA
-411mV    -9.95mA    -7.9mA     -12.33mA
-353.4mV  -7.13mA    -5.671mA   -8.954mA
-301.2mV  -4.986mA   -4.099mA   -6.201mA
-256.2mV  -3.563mA   -3.09mA    -4.247mA
-211.2mV  -2.532mA   -2.325mA   -2.801mA
-159mV    -1.695mA   -1.634mA   -1.73mA
165mV     1.443mA    1.428mA    1.457mA
480mV     3.705mA    3.537mA    3.945mA
811.2mV   5.171mA    4.701mA    5.943mA
1.2V      6.059mA    5.442mA    7.269mA
[GND Clamp]
|   Voltage   I(typ)   I(min)   I(max)
-600mV    -5.44mA    -3.803mA   -7.294mA
-565.8mV  -4.041mA   -2.789mA   -5.405mA
-538.8mV  -3.089mA   -2.125mA   -4.068mA
-508.2mV  -2.193mA   -1.512mA   -2.769mA
-483mV    -1.605mA   -1.109mA   -1.914mA
-456mV    -1.112mA   -768.3uA   -1.229mA
-429mV    -741.4uA   -509.9uA   -756.6uA
-393mV    -401.5uA   -274.7uA   -367.1uA
-357mV    -197.3uA   -136.4uA   -159.9uA
-295.8mV  -46.78uA   -34.47uA   -29.95uA
-200.4mV  -2.98uA    -2.817uA   -1.07uA
1.2V      0A         0A         0A
[Pullup]
|   Voltage   I(typ)   I(min)   I(max)
-600mV    2.847mA    2.16mA     3.822mA
-272.4mV  2.078mA    1.562mA    2.774mA
-141mV    1.559mA    1.192mA    2.035mA
-83.4mV   1.105mA    875.3uA    1.404mA
-24mV     373uA      308.4uA    458.9uA
82.2mV    -1.634mA   -1.486mA   -1.864mA
217.2mV   -5.154mA   -5.056mA   -5.556mA
402.6mV   -10.81mA   -11.02mA   -11.26mA
634.8mV   -18.47mA   -19mA      -18.94mA
989.4mV   -30.58mA   -31.27mA   -31.27mA
1.106V    -34.24mA   -34.96mA   -35.17mA
1.2V      -36.67mA   -37.43mA   -37.73mA
[POWER Clamp]
|   Voltage   I(typ)   I(min)   I(max)
-600mV    870.6nA    21.99uA    72.65nA
-589.2mV  630.3nA    16.59uA    68.66nA
-576.6mV  439nA      11.87uA    64.76nA
-564mV    312.9nA    8.462uA    61.06nA
-547.8mV  210.7nA    5.447uA    56.56nA
-531.6mV  149.3nA    3.497uA    52.35nA
-511.8mV  106nA      2.039uA    47.56nA
-488.4mV  78.51nA    1.09uA     42.36nA
-459.6mV  61.17nA    520.5nA    36.6nA
-411mV    46.96nA    174.9nA    28.34nA
-313.8mV  32.74nA    54.78nA    16.39nA
1.2V      0A         0A         0A
[Ramp]
|   typ   min   max
| 20% - 80%
dV/dt_r   198.98m/32.32p   187.74m/36.99p   222.24m/27.79p
dV/dt_f   101.89m/53.91p   94.53m/64.07p   114.03m/44.81p
| 25% - 75%
|dV/dt_r   165.81m/25.57p   156.45m/29.25p   185.20m/21.99p
|dV/dt_f   84.91m/42.58p   78.77m/50.47p   95.02m/35.38p
R_load = 50
[Rising Waveform]
R_fixture = 50
V_fixture = 0.0
|   Time   V(typ)   V(min)   V(max)
0s        284.9uV    275.2uV    129.6uV
60ps      1.414mV    -703.1uV   16.19mV
67ps      5.46mV     -603.1uV   57.94mV
79ps      22.54mV    3.276mV    174.3mV
92ps      100mV      12.02mV    273.4mV
105ps     195.6mV    41.33mV    325.3mV
120ps     266.2mV    126.2mV    352.2mV
144ps     312.4mV    243.1mV    366.3mV
173ps     327.4mV    294.6mV    369.8mV
333ps     331.9mV    313.2mV    370.5mV
[Falling Waveform]
R_fixture   = 50
V_fixture   = 0.6
V_fixture_min = 0.57
V_fixture_max = 0.65
|   Time   V(typ)   V(min)   V(max)
0s        600mV      570mV      650mV
50ps      601.1mV    570.4mV    650.9mV
70ps      598.3mV    571.7mV    638.1mV
93ps      580.9mV    563mV      567.3mV
111ps     540.5mV    553.4mV    520.7mV
130ps     498mV      531.6mV    492.6mV
151ps     467.9mV    492.6mV    476.2mV
181ps     445.9mV    451.9mV    465.9mV
212ps     436.4mV    430.2mV    462mV
333ps     430.2mV    412.5mV    460mV
[Rising Waveform]
R_fixture   = 50
V_fixture   = 0.6
V_fixture_min = 0.57
V_fixture_max = 0.65
|   Time   V(typ)   V(min)   V(max)
0s        430mV      411.7mV    459.9mV
43ps      429mV      412.2mV    459mV
57ps      429.1mV    409.8mV    470.3mV
66ps      437.1mV    409.1mV    492.1mV
77ps      460.7mV    414.4mV    540.1mV
94ps      514.2mV    448.4mV    602.9mV
121ps     570.8mV    516.1mV    638.8mV
146ps     590.6mV    549mV      646.9mV
176ps     597.6mV    564.3mV    649.3mV
333ps     600mV      570mV      650mV
[Falling Waveform]
R_fixture = 50
V_fixture = 0.0
|   Time   V(typ)   V(min)   V(max)
0s        332mV      313.3mV    370.6mV
62ps      335.8mV    315.9mV    361.8mV
70ps      332.3mV    317.9mV    325mV
80ps      312.5mV    317.2mV    235.1mV
97ps      212.1mV    290.9mV    121.6mV
114ps     115.5mV    210.4mV    65.32mV
134ps     57.52mV    114.4mV    31.82mV
158ps     25.67mV    51.65mV    13.59mV
191ps     8.717mV    17.78mV    4.332mV
333ps     416.5uV    555.3uV    188.2uV
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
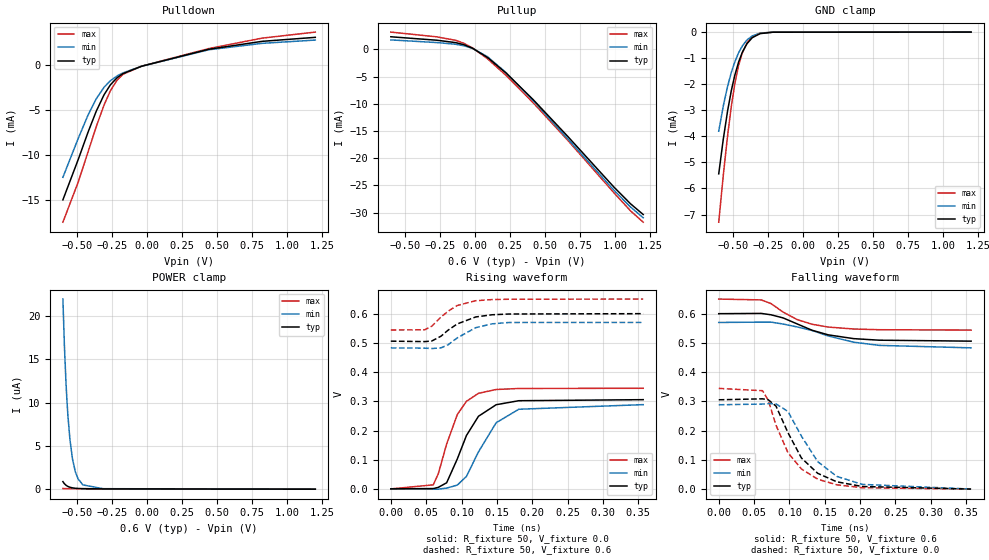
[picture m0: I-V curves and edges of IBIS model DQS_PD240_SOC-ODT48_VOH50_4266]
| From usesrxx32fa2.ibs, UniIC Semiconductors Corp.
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| DQS_PD240_SOC-ODT48_VOH50_4266
| (240 Ohm Pulldown, 48 Ohm System ODT Setting, VOH=VDDQ*0.50, 3200-4266Mbps)
[Model]   DQS_PD240_SOC-ODT48_VOH50_4266
Model_type   I/O
Vinl = 90.000mV
Vinh = 210.000mV
Vmeas = 150.000mV
Vref = 0.0mV
Cref = 0.0pF
Rref = 48.000Ohm
|   typ   min   max
|C_comp   0.849pF   0.799pF   0.899pF
C_comp_pullup   0.4245pF   0.3995pF   0.4495pF
C_comp_pulldown   0.4245pF   0.3995pF   0.4495pF
| Note: C_comp changes when the ODT circuit is enabled.
[Model Spec]
| Input threshold voltage corners
Vinl   0.0900V   0.0825V   0.1025V
Vinh   0.2100V   0.2025V   0.2225V
| Measurement voltage corners
Vmeas   0.1500V   0.1425V   0.1625V
| Timing spec test load voltage corners
Vref   0.0000V   0.0000V   0.0000V
| Dynamic Overshoot Parameters from LPDDR4_0P6 Specification
D_overshoot_ampl_h   0.30   NA   NA
D_overshoot_ampl_l   0.30   NA   NA
D_overshoot_area_h   0.1n   NA   NA
D_overshoot_area_l   0.1n   NA   NA
[Voltage Range]   0.6000V   0.5700V   0.6500V
[Pullup Reference]   0.6000V   0.5700V   0.6500V
| Junction Temperature (Ambient temp is 35C typ 95C min -40C max)
[Temperature Range]   50.0   110.0   -40.0
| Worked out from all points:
|   slope of the pulldown table from 0 to 0.09 V, typ, clamps not added: 228 ohm
|   slope of the pullup table from 0 to 0.09 V, typ, clamps not added: 60.5 ohm
|   GND clamp passes 1 mA (typ) near -0.45 V on its own axis
|   rising waveform, R_fixture 50, V_fixture 0.0: 20-80 % time 34.7ps typ, 40.2ps min, 29.7ps max; typ from 0 V to 0.306 V
|   falling waveform, R_fixture 50, V_fixture 0.6: 20-80 % time 64.2ps typ, 79.8ps min, 52.1ps max; typ from 0.6 V to 0.506 V
|   rising waveform, R_fixture 50, V_fixture 0.6: 20-80 % time 37.3ps typ, 35.7ps min, 32.9ps max; typ from 0.506 V to 0.6 V
|   falling waveform, R_fixture 50, V_fixture 0.0: 20-80 % time 46.2ps typ, 50.1ps min, 42.9ps max; typ from 0.306 V to 0 V
[Pulldown]
|   Voltage   I(typ)   I(min)   I(max)
-600mV    -14.95mA   -12.46mA   -17.42mA
-490.2mV  -10.47mA   -8.145mA   -12.96mA
-420mV    -7.447mA   -5.559mA   -9.623mA
-362.4mV  -5.168mA   -3.793mA   -6.871mA
-306.6mV  -3.343mA   -2.512mA   -4.482mA
-261.6mV  -2.247mA   -1.792mA   -2.914mA
-214.8mV  -1.471mA   -1.27mA    -1.742mA
-171.6mV  -1.003mA   -923.4uA   -1.073mA
-38.4mV   -186.7uA   -185.3uA   -177.8uA
440.4mV   1.688mA    1.632mA    1.765mA
820.2mV   2.563mA    2.341mA    2.917mA
1.2V      3.005mA    2.705mA    3.586mA
[GND Clamp]
|   Voltage   I(typ)   I(min)   I(max)
-600mV    -5.439mA   -3.802mA   -7.294mA
-567.6mV  -4.11mA    -2.837mA   -5.5mA
-537mV    -3.03mA    -2.085mA   -3.984mA
-510mV    -2.24mA    -1.544mA   -2.838mA
-484.8mV  -1.645mA   -1.137mA   -1.967mA
-457.8mV  -1.143mA   -787.4uA   -1.268mA
-430.8mV  -763uA     -524.1uA   -782.7uA
-398.4mV  -442.4uA   -303.3uA   -412.9uA
-360.6mV  -213.7uA   -146.5uA   -174.7uA
-304.8mV  -58.68uA   -42.61uA   -39.13uA
-213mV    -4.461uA   -4.049uA   -1.773uA
1.2V      0A         0A         0A
[Pullup]
|   Voltage   I(typ)   I(min)   I(max)
-600mV    2.327mA    1.755mA    3.187mA
-270.6mV  1.687mA    1.257mA    2.308mA
-137.4mV  1.249mA    947.7uA    1.674mA
-79.8mV   870.4uA    684.8uA    1.133mA
-18.6mV   238.8uA    196.6uA    300.9uA
89.4mV    -1.476mA   -1.34mA    -1.715mA
220.8mV   -4.322mA   -4.23mA    -4.754mA
415.2mV   -9.231mA   -9.412mA   -9.8mA
661.8mV   -15.99mA   -16.45mA   -16.7mA
987.6mV   -25.21mA   -25.79mA   -26.25mA
1.11V     -28.39mA   -28.98mA   -29.69mA
1.2V      -30.35mA   -30.94mA   -31.76mA
[POWER Clamp]
|   Voltage   I(typ)   I(min)   I(max)
-600mV    870.6nA    21.99uA    72.65nA
-589.2mV  630.1nA    16.59uA    68.66nA
-578.4mV  462nA      12.46uA    65.31nA
-571.2mV  378.5nA    10.27uA    63.15nA
-564mV    312.8nA    8.457uA    61.06nA
-549.6mV  219nA      5.715uA    57.05nA
-531.6mV  149.1nA    3.495uA    52.35nA
-511.8mV  106.3nA    2.04uA     47.55nA
-492mV    82.01nA    1.198uA    43.12nA
-457.8mV  60.5nA     497.6nA    36.26nA
-313.8mV  32.76nA    54.8nA     16.39nA
1.2V      0A         0A         0A
[Ramp]
|   typ   min   max
| 20% - 80%
dV/dt_r   183.19m/34.75p   173.01m/40.20p   206.67m/29.69p
dV/dt_f   56.37m/64.21p   52.06m/79.80p   63.59m/52.08p
| 25% - 75%
|dV/dt_r   152.66m/27.48p   144.17m/31.78p   172.23m/23.50p
|dV/dt_f   46.97m/50.59p   43.38m/61.57p   52.99m/41.18p
R_load = 50
[Rising Waveform]
R_fixture = 50
V_fixture = 0.0
|   Time   V(typ)   V(min)   V(max)
0s        283.1uV    269.5uV    131.2uV
60ps      1.253mV    -810.3uV   13.97mV
67ps      5.145mV    -775.2uV   50.88mV
79ps      21.19mV    2.837mV    153.9mV
94ps      102.4mV    12.99mV    254.4mV
107ps     183mV      43.1mV     300.1mV
124ps     248.8mV    126.9mV    327.4mV
149ps     288.3mV    226.6mV    340.4mV
181ps     302mV      272.8mV    343.9mV
357ps     305.6mV    288.6mV    344.6mV
[Falling Waveform]
R_fixture   = 50
V_fixture   = 0.6
V_fixture_min = 0.57
V_fixture_max = 0.65
|   Time   V(typ)   V(min)   V(max)
0s        600mV      570mV      650mV
60ps      601mV      571.2mV    647.1mV
74ps      596.2mV    571.1mV    634.6mV
91ps      585.6mV    564.7mV    605.5mV
111ps     565mV      554.7mV    579.8mV
132ps     543.4mV    542.6mV    563.9mV
155ps     527.6mV    523.8mV    554.3mV
191ps     514.7mV    502.5mV    547.6mV
227ps     509.4mV    491.7mV    545.2mV
357ps     506.1mV    483.2mV    544mV
[Rising Waveform]
R_fixture   = 50
V_fixture   = 0.6
V_fixture_min = 0.57
V_fixture_max = 0.65
|   Time   V(typ)   V(min)   V(max)
0s        505.9mV    482.8mV    544mV
48ps      504.4mV    482mV      545mV
58ps      506.5mV    480.6mV    557.2mV
71ps      522.9mV    482.9mV    588.5mV
81ps      543.5mV    493.5mV    608.3mV
94ps      564.9mV    517.2mV    628.1mV
120ps     588.7mV    552mV      644.3mV
143ps     596.2mV    565.1mV    648.2mV
167ps     598.8mV    569.8mV    649.4mV
357ps     600mV      570mV      650mV
[Falling Waveform]
R_fixture = 50
V_fixture = 0.0
|   Time   V(typ)   V(min)   V(max)
0s        305.7mV    288.7mV    344.6mV
62ps      309mV      291mV      336.8mV
70ps      305.8mV    292.8mV    304.2mV
81ps      284.2mV    291.8mV    218.9mV
98ps      192.9mV    265.5mV    124.4mV
117ps     106.7mV    181.4mV    69.05mV
140ps     54.34mV    94.22mV    34.26mV
167ps     25.33mV    43.85mV    15.15mV
203ps     9.352mV    16.53mV    5.159mV
357ps     476.4uV    632.1uV    212.7uV
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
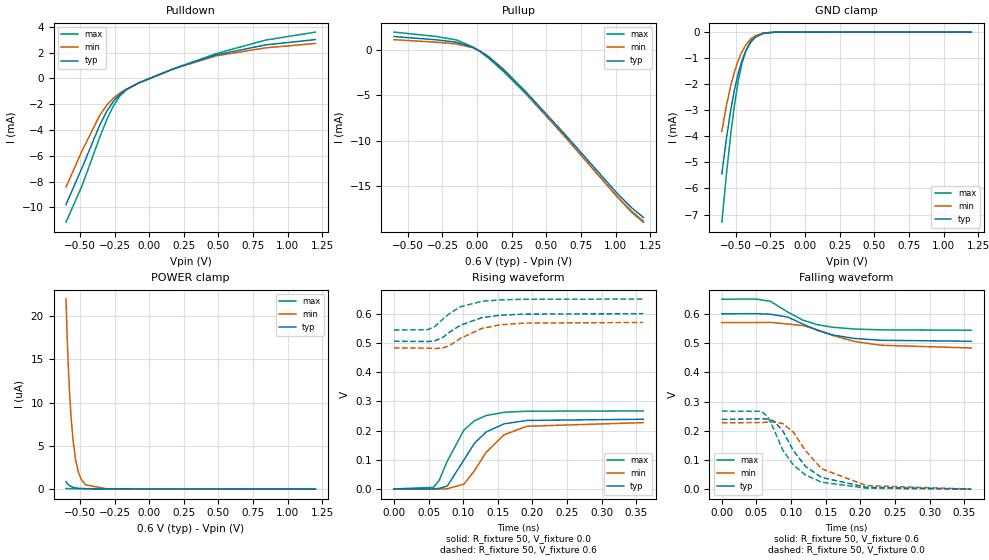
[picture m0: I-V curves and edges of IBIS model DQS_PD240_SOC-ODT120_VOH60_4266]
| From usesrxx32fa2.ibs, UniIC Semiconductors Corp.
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| DQS_PD240_SOC-ODT120_VOH60_4266
| (240 Ohm Pulldown, 120 Ohm System ODT Setting, VOH=VDDQ*0.60, 3200-4266Mbps)
[Model]   DQS_PD240_SOC-ODT120_VOH60_4266
Model_type   I/O
Vinl = 120.000mV
Vinh = 240.000mV
Vmeas = 180.000mV
Vref = 0.0mV
Cref = 0.0pF
Rref = 120.000Ohm
|   typ   min   max
|C_comp   0.849pF   0.799pF   0.899pF
C_comp_pullup   0.4245pF   0.3995pF   0.4495pF
C_comp_pulldown   0.4245pF   0.3995pF   0.4495pF
| Note: C_comp changes when the ODT circuit is enabled.
[Model Spec]
| Input threshold voltage corners
Vinl   0.1200V   0.1110V   0.1350V
Vinh   0.2400V   0.2310V   0.2550V
| Measurement voltage corners
Vmeas   0.1800V   0.1710V   0.1950V
| Timing spec test load voltage corners
Vref   0.0000V   0.0000V   0.0000V
| Dynamic Overshoot Parameters from LPDDR4_0P6 Specification
D_overshoot_ampl_h   0.30   NA   NA
D_overshoot_ampl_l   0.30   NA   NA
D_overshoot_area_h   0.1n   NA   NA
D_overshoot_area_l   0.1n   NA   NA
[Voltage Range]   0.6000V   0.5700V   0.6500V
[Pullup Reference]   0.6000V   0.5700V   0.6500V
| Junction Temperature (Ambient temp is 35C typ 95C min -40C max)
[Temperature Range]   50.0   110.0   -40.0
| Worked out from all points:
|   slope of the pulldown table from 0 to 0.09 V, typ, clamps not added: 229 ohm
|   slope of the pullup table from 0 to 0.09 V, typ, clamps not added: 98.8 ohm
|   GND clamp passes 1 mA (typ) near -0.45 V on its own axis
|   rising waveform, R_fixture 50, V_fixture 0.0: 20-80 % time 41.2ps typ, 44.9ps min, 35.7ps max; typ from 0 V to 0.239 V
|   falling waveform, R_fixture 50, V_fixture 0.6: 20-80 % time 62.1ps typ, 72.8ps min, 52.3ps max; typ from 0.6 V to 0.506 V
|   rising waveform, R_fixture 50, V_fixture 0.6: 20-80 % time 44ps typ, 45.3ps min, 37.9ps max; typ from 0.506 V to 0.6 V
|   falling waveform, R_fixture 50, V_fixture 0.0: 20-80 % time 47.6ps typ, 52.1ps min, 44ps max; typ from 0.239 V to 0 V
[Pulldown]
|   Voltage   I(typ)   I(min)   I(max)
-600mV    -9.779mA   -8.417mA   -11.14mA
-483mV    -6.894mA   -5.596mA   -8.285mA
-357mV    -3.633mA   -2.869mA   -4.574mA
-304.8mV  -2.534mA   -2.065mA   -3.17mA
-256.2mV  -1.752mA   -1.511mA   -2.097mA
-213mV    -1.255mA   -1.146mA   -1.395mA
-166.2mV  -873.7uA   -836.1uA   -896.9uA
-76.2mV   -361.3uA   -359.4uA   -350.1uA
181.2mV   764.2uA    757.9uA    767uA
483.6mV   1.817mA    1.746mA    1.916mA
838.2mV   2.591mA    2.362mA    2.96mA
1.2V      3.005mA    2.705mA    3.586mA
[GND Clamp]
|   Voltage   I(typ)   I(min)   I(max)
-600mV    -5.44mA    -3.803mA   -7.294mA
-565.8mV  -4.041mA   -2.79mA    -5.405mA
-535.2mV  -2.973mA   -2.046mA   -3.902mA
-510mV    -2.24mA    -1.544mA   -2.838mA
-481.2mV  -1.569mA   -1.083mA   -1.86mA
-454.2mV  -1.086mA   -747.4uA   -1.191mA
-425.4mV  -701.5uA   -483uA     -707.3uA
-391.2mV  -388.2uA   -267uA     -353.1uA
-357mV    -197.6uA   -136uA     -159.9uA
-303mV    -56.27uA   -41.16uA   -37.07uA
-222mV    -5.821uA   -5.156uA   -2.498uA
1.2V      0A         0A         0A
[Pullup]
|   Voltage   I(typ)   I(min)   I(max)
-600mV    1.424mA    1.081mA    1.912mA
-294mV    1.07mA     804.2uA    1.43mA
-146.4mV  795.6uA    607.3uA    1.042mA
-29.4mV   226.1uA    186.5uA    279uA
21mV      -183.6uA   -157.9uA   -219uA
82.2mV    -820.5uA   -746.4uA   -936.2uA
190.2mV   -2.209mA   -2.145mA   -2.4mA
350.4mV   -4.606mA   -4.67mA    -4.828mA
643.8mV   -9.451mA   -9.726mA   -9.684mA
1.007V    -15.68mA   -16.04mA   -16.05mA
1.117V    -17.35mA   -17.73mA   -17.84mA
1.2V      -18.38mA   -18.78mA   -18.91mA
[POWER Clamp]
|   Voltage   I(typ)   I(min)   I(max)
-600mV    870.6nA    21.99uA    72.65nA
-589.2mV  630.3nA    16.59uA    68.66nA
-583.8mV  538.6nA    14.38uA    66.96nA
-576.6mV  439nA      11.88uA    64.76nA
-564mV    312.9nA    8.464uA    61.06nA
-549.6mV  219nA      5.717uA    57.05nA
-529.8mV  143.9nA    3.326uA    51.9nA
-510mV    103.1nA    1.944uA    47.14nA
-488.4mV  78.86nA    1.091uA    42.35nA
-457.8mV  60.55nA    496.9nA    36.26nA
-312mV    32.54nA    54.18nA    16.21nA
1.2V      0A         0A         0A
[Ramp]
|   typ   min   max
| 20% - 80%
dV/dt_r   143.16m/41.16p   136.17m/44.91p   160.25m/35.69p
dV/dt_f   56.38m/62.07p   52.06m/72.76p   63.59m/52.31p
| 25% - 75%
|dV/dt_r   119.30m/32.62p   113.47m/35.51p   133.54m/28.26p
|dV/dt_f   46.98m/49.08p   43.38m/57.33p   52.99m/41.35p
R_load = 50
[Rising Waveform]
R_fixture = 50
V_fixture = 0.0
|   Time   V(typ)   V(min)   V(max)
0s        170.9uV    163.2uV    79.09uV
57ps      108.3uV    -352.3uV   5.743mV
65ps      2.103mV    -626.5uV   27.94mV
77ps      9.918mV    849uV      94.98mV
101ps     99.25mV    16.39mV    201.6mV
116ps     155.6mV    61.74mV    233.2mV
133ps     194.9mV    125.2mV    251.4mV
159ps     222.9mV    185.6mV    262.4mV
192ps     234.6mV    214.7mV    266.1mV
360ps     238.8mV    227.1mV    267.2mV
[Falling Waveform]
R_fixture   = 50
V_fixture   = 0.6
V_fixture_min = 0.57
V_fixture_max = 0.65
|   Time   V(typ)   V(min)   V(max)
0s        600mV      570mV      650mV
49ps      600.6mV    570.2mV    650.5mV
70ps      598.6mV    570.9mV    643mV
95ps      589.1mV    565mV      606.2mV
117ps     565.1mV    559.7mV    578.3mV
138ps     543mV      545.8mV    562.9mV
160ps     527.6mV    526.1mV    554mV
192ps     515.5mV    505.2mV    547.9mV
230ps     509.5mV    492.4mV    545.2mV
360ps     506mV      483.2mV    544mV
[Rising Waveform]
R_fixture   = 50
V_fixture   = 0.6
V_fixture_min = 0.57
V_fixture_max = 0.65
|   Time   V(typ)   V(min)   V(max)
0s        505.9mV    482.8mV    544mV
49ps      504.7mV    482mV      545.4mV
59ps      506.9mV    480.9mV    555.9mV
71ps      519.6mV    482.9mV    582.2mV
81ps      537.8mV    491.8mV    601.8mV
96ps      560.5mV    515.6mV    623.5mV
127ps     586.3mV    549.4mV    642.4mV
153ps     594.6mV    561.8mV    647.2mV
187ps     598.4mV    567.6mV    649.2mV
360ps     600mV      570mV      650mV
[Falling Waveform]
R_fixture = 50
V_fixture = 0.0
|   Time   V(typ)   V(min)   V(max)
0s        238.8mV    227.2mV    267.2mV
57ps      240.9mV    228mV      266.5mV
66ps      240.3mV    229.5mV    249mV
75ps      233.5mV    230.1mV    205.2mV
88ps      199.5mV    224.7mV    133.8mV
103ps     132.7mV    195.7mV    83.58mV
121ps     77.48mV    131.3mV    48.27mV
144ps     40.1mV     69.75mV    24.02mV
209ps     6.537mV    12.16mV    3.468mV
360ps     335.2uV    483uV      144.3uV
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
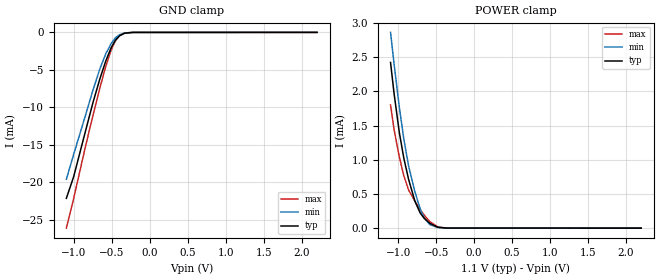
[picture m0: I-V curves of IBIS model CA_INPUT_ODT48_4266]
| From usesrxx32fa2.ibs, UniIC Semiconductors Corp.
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| CA_INPUT_ODT48_4266 (with 48ohm ODT, 3200-4266Mbps)
[Model]   CA_INPUT_ODT48_4266
Model_type   Input
Vinl = 202.500mV
Vinh = 347.500mV
|   typ   min   max
|C_comp   0.662pF   0.610pF   0.728pF
C_comp_power_clamp   0.3310pF   0.3050pF   0.3640pF
C_comp_gnd_clamp   0.3310pF   0.3050pF   0.3640pF
| Note: C_comp changes when the ODT circuit is enabled.
[Model Spec]
| Input threshold voltage corners
Vinl   0.2025V   0.1925V   0.2200V
Vinh   0.3475V   0.3375V   0.3650V
| Dynamic Overshoot Parameters from LPDDR4_0P6 Specification
D_overshoot_ampl_h   0.30   NA   NA
D_overshoot_ampl_l   0.30   NA   NA
D_overshoot_area_h   0.1n   NA   NA
D_overshoot_area_l   0.1n   NA   NA
[Voltage Range]   1.1000V   1.0600V   1.1700V
[POWER Clamp Reference]   1.1000V   1.0600V   1.1700V
| Junction Temperature (Ambient temp is 35C typ 95C min -40C max)
[Temperature Range]   50.0   110.0   -40.0
[Add Submodel]
| Submodel Name   Mode
48ohm_ODT_4266   Non-Driving
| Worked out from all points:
|   GND clamp passes 1 mA (typ) near -0.45 V on its own axis
|   POWER clamp passes 1 mA (typ) near -0.92 V on its own axis
[GND Clamp]
|   Voltage   I(typ)   I(min)   I(max)
-1.1V     -22.11mA   -19.58mA   -26.08mA
-1.004V   -19.23mA   -16.26mA   -22.13mA
-849.2mV  -13.2mA    -11.09mA   -15.24mA
-746.9mV  -9.249mA   -7.592mA   -10.94mA
-657.8mV  -6.159mA   -4.827mA   -7.354mA
-581.9mV  -3.835mA   -2.882mA   -4.564mA
-509.3mV  -2.028mA   -1.464mA   -2.33mA
-456.5mV  -1.084mA   -756.8uA   -1.157mA
-400.4mV  -452.9uA   -313.8uA   -423.9uA
-334.4mV  -119.8uA   -84.87uA   -89.69uA
-228.8mV  -7.265uA   -6.189uA   -3.231uA
2.2V      0A         0A         0A
[POWER Clamp]
|   Voltage   I(typ)   I(min)   I(max)
-1.1V     2.422mA    2.862mA    1.802mA
-1.054V   1.972mA    2.404mA    1.444mA
-984.5mV  1.398mA    1.769mA    1.042mA
-925.1mV  1.022mA    1.301mA    765.1uA
-862.4mV  713.1uA    909.2uA    558uA
-779.9mV  395.5uA    532.8uA    395.6uA
-710.6mV  222.7uA    284uA      272.7uA
-657.8mV  144.8uA    149.2uA    190.3uA
-581.9mV  69.42uA    50.4uA     94.52uA
-476.3mV  13.61uA    7.967uA    16.56uA
-360.8mV  874.5nA    615.6nA    579.1nA
2.2V      0A         0A         0A
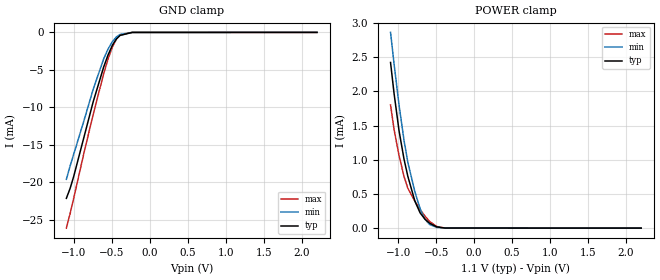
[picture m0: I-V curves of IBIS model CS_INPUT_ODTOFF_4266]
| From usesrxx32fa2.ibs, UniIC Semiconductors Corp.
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| CS_INPUT_ODTOFF_4266 (with no ODT, 3200-4266Mbps)
[Model]   CS_INPUT_ODTOFF_4266
Model_type   Input
Vinl = 202.500mV
Vinh = 347.500mV
|   typ   min   max
|C_comp   0.655pF   0.605pF   0.705pF
C_comp_power_clamp   0.3275pF   0.3025pF   0.3525pF
C_comp_gnd_clamp   0.3275pF   0.3025pF   0.3525pF
[Model Spec]
| Input threshold voltage corners
Vinl   0.2025V   0.1925V   0.2200V
Vinh   0.3475V   0.3375V   0.3650V
| Dynamic Overshoot Parameters from LPDDR4_0P6 Specification
D_overshoot_ampl_h   0.30   NA   NA
D_overshoot_ampl_l   0.30   NA   NA
D_overshoot_area_h   0.1n   NA   NA
D_overshoot_area_l   0.1n   NA   NA
[Voltage Range]   1.1000V   1.0600V   1.1700V
[POWER Clamp Reference]   1.1000V   1.0600V   1.1700V
| Junction Temperature (Ambient temp is 35C typ 95C min -40C max)
[Temperature Range]   50.0   110.0   -40.0
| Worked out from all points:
|   GND clamp passes 1 mA (typ) near -0.45 V on its own axis
|   POWER clamp passes 1 mA (typ) near -0.92 V on its own axis
[GND Clamp]
|   Voltage   I(typ)   I(min)   I(max)
-1.1V     -22.11mA   -19.58mA   -26.08mA
-1.05V    -20.77mA   -17.78mA   -24.12mA
-1.004V   -19.22mA   -16.26mA   -22.13mA
-869mV    -13.99mA   -11.78mA   -16.09mA
-746.9mV  -9.248mA   -7.59mA    -10.94mA
-608.3mV  -4.602mA   -3.512mA   -5.492mA
-548.9mV  -2.952mA   -2.179mA   -3.475mA
-492.8mV  -1.696mA   -1.215mA   -1.913mA
-440mV    -859.5uA   -596uA     -886.2uA
-393.8mV  -405uA     -278.7uA   -371.1uA
-235.4mV  -8.873uA   -7.484uA   -4.094uA
2.2V      0A         0A         0A
[POWER Clamp]
|   Voltage   I(typ)   I(min)   I(max)
-1.1V     2.422mA    2.862mA    1.802mA
-1.054V   1.972mA    2.404mA    1.444mA
-987.8mV  1.422mA    1.797mA    1.06mA
-921.8mV  1.004mA    1.277mA    751.6uA
-872.3mV  757.8uA    962.5uA    583.3uA
-779.9mV  395.5uA    532.1uA    395.6uA
-710.6mV  222.7uA    284uA      272.7uA
-647.9mV  133.1uA    130.6uA    176.2uA
-585.2mV  72.04uA    52.92uA    97.83uA
-492.8mV  18.66uA    11.08uA    23.7uA
-383.9mV  1.563uA    1.038uA    1.242uA
2.2V      0A         0A         0A
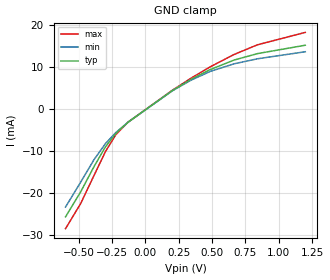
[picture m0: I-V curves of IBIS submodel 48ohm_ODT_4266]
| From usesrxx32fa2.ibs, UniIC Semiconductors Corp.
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| SUBMODEL 48ohm_ODT_4266
[Submodel]   48ohm_ODT_4266
Submodel_type   Dynamic_clamp
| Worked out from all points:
|   GND clamp passes 1 mA (typ) near -0.04 V on its own axis
[GND Clamp]
|   Voltage   I(typ)   I(min)   I(max)
-600mV    -25.65mA   -23.32mA   -28.46mA
-486.6mV  -19.73mA   -17.42mA   -22.51mA
-385.8mV  -13.68mA   -12.03mA   -15.79mA
-299.4mV  -8.959mA   -8.19mA    -10.09mA
-222mV    -5.807mA   -5.598mA   -6.104mA
-130.2mV  -3.144mA   -3.126mA   -3.113mA
201mV     4.355mA    4.294mA    4.43mA
337.8mV   6.966mA    6.776mA    7.235mA
487.2mV   9.392mA    8.942mA    10.04mA
665.4mV   11.63mA    10.74mA    12.96mA
841.8mV   13.17mA    11.94mA    15.27mA
1.2V      15.16mA    13.61mA    18.21mA
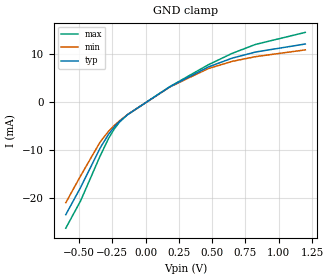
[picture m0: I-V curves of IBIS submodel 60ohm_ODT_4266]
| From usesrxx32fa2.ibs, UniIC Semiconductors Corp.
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| SUBMODEL 60ohm_ODT_4266
[Submodel]   60ohm_ODT_4266
Submodel_type   Dynamic_clamp
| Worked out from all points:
|   GND clamp passes 1 mA (typ) near -0.05 V on its own axis
[GND Clamp]
|   Voltage   I(typ)   I(min)   I(max)
-600mV    -23.55mA   -21.06mA   -26.38mA
-488.4mV  -17.85mA   -15.44mA   -20.66mA
-342.6mV  -9.66mA    -8.397mA   -11.33mA
-279.6mV  -6.802mA   -6.152mA   -7.68mA
-236.4mV  -5.248mA   -4.932mA   -5.669mA
-196.8mV  -4.097mA   -3.955mA   -4.227mA
-135.6mV  -2.653mA   -2.629mA   -2.63mA
181.2mV   3.158mA    3.12mA     3.198mA
469.2mV   7.291mA    6.967mA    7.755mA
651mV     9.169mA    8.494mA    10.17mA
825.6mV   10.44mA    9.472mA    12.03mA
1.2V      12.12mA    10.89mA    14.55mA
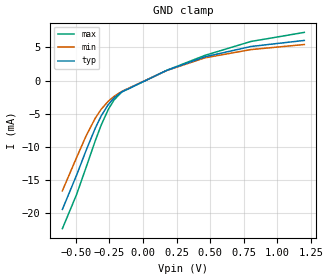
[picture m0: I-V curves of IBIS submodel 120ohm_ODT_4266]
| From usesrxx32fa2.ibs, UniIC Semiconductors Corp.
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| SUBMODEL 120ohm_ODT_4266
[Submodel]   120ohm_ODT_4266
Submodel_type   Dynamic_clamp
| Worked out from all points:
|   GND clamp passes 1 mA (typ) near -0.10 V on its own axis
[GND Clamp]
|   Voltage   I(typ)   I(min)   I(max)
-600mV    -19.41mA   -16.6mA    -22.31mA
-495.6mV  -14.31mA   -11.65mA   -17.23mA
-421.8mV  -10.43mA   -8.251mA   -12.98mA
-355.2mV  -7.163mA   -5.659mA   -9.056mA
-312mV    -5.347mA   -4.338mA   -6.736mA
-258mV    -3.598mA   -3.096mA   -4.316mA
-214.8mV  -2.59mA    -2.363mA   -2.9mA
-159mV    -1.693mA   -1.628mA   -1.732mA
177.6mV   1.546mA    1.53mA     1.565mA
460.2mV   3.586mA    3.434mA    3.803mA
802.2mV   5.143mA    4.678mA    5.899mA
1.2V      6.059mA    5.442mA    7.269mA
